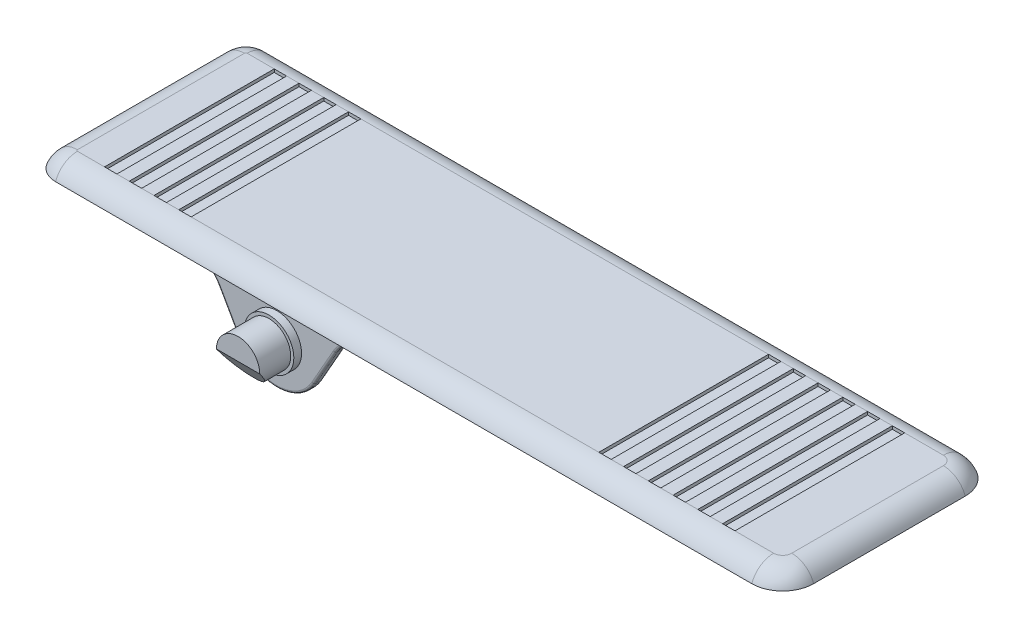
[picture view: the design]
ISO-10303-21;
HEADER;
FILE_DESCRIPTION(('STEP AP214'),'2;1');
FILE_NAME('part.step','',(''),(''),'','','');
FILE_SCHEMA(('AUTOMOTIVE_DESIGN { 1 0 10303 214 1 1 1 1 }'));
ENDSEC;
DATA;
#1=APPLICATION_CONTEXT('core data for automotive mechanical design processes');
#2=APPLICATION_PROTOCOL_DEFINITION('international standard','automotive_design',2000,#1);
#3=PRODUCT_CONTEXT('',#1,'mechanical');
#4=PRODUCT('Part','Part','',(#3));
#5=PRODUCT_RELATED_PRODUCT_CATEGORY('part','',(#4));
#6=PRODUCT_DEFINITION_FORMATION('','',#4);
#7=PRODUCT_DEFINITION_CONTEXT('part definition',#1,'design');
#8=PRODUCT_DEFINITION('design','',#6,#7);
#9=PRODUCT_DEFINITION_SHAPE('','',#8);
#10=(LENGTH_UNIT() NAMED_UNIT(*) SI_UNIT(.MILLI.,.METRE.));
#11=(NAMED_UNIT(*) PLANE_ANGLE_UNIT() SI_UNIT($,.RADIAN.));
#12=(NAMED_UNIT(*) SI_UNIT($,.STERADIAN.) SOLID_ANGLE_UNIT());
#13=UNCERTAINTY_MEASURE_WITH_UNIT(LENGTH_MEASURE(1.E-05),#10,'distance_accuracy_value','');
#14=(GEOMETRIC_REPRESENTATION_CONTEXT(3) GLOBAL_UNCERTAINTY_ASSIGNED_CONTEXT((#13)) GLOBAL_UNIT_ASSIGNED_CONTEXT((#10,
#11,#12)) REPRESENTATION_CONTEXT('',''));
#15=CARTESIAN_POINT('',(0.,0.,0.));
#16=DIRECTION('',(0.,0.,1.));
#17=DIRECTION('',(1.,0.,0.));
#18=AXIS2_PLACEMENT_3D('',#15,#16,#17);
#19=CARTESIAN_POINT('',(3.81,2.54,-3.81));
#20=DIRECTION('',(0.,1.,0.));
#21=DIRECTION('',(0.,0.,1.));
#22=AXIS2_PLACEMENT_3D('',#19,#20,#21);
#23=PLANE('',#22);
#24=DIRECTION('',(0.,0.,-1.));
#25=VECTOR('',#24,1.);
#26=CARTESIAN_POINT('',(22.479,2.54,-3.59210244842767));
#27=LINE('',#26,#25);
#28=CARTESIAN_POINT('',(22.479,2.54,-3.59210244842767));
#29=VERTEX_POINT('',#28);
#30=CARTESIAN_POINT('',(22.479,2.54,-31.4598975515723));
#31=VERTEX_POINT('',#30);
#32=EDGE_CURVE('E43',#29,#31,#27,.T.);
#33=ORIENTED_EDGE('',*,*,#32,.F.);
#34=DIRECTION('',(-1.,0.,0.));
#35=VECTOR('',#34,1.);
#36=CARTESIAN_POINT('',(118.11,2.54,-3.59210244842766));
#37=LINE('',#36,#35);
#38=CARTESIAN_POINT('',(89.408,2.54,-3.59210244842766));
#39=VERTEX_POINT('',#38);
#40=EDGE_CURVE('E1193',#29,#39,#37,.F.);
#41=ORIENTED_EDGE('',*,*,#40,.T.);
#42=DIRECTION('',(0.,0.,1.));
#43=VECTOR('',#42,1.);
#44=CARTESIAN_POINT('',(89.408,2.54,-31.4598975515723));
#45=LINE('',#44,#43);
#46=CARTESIAN_POINT('',(89.408,2.54,-31.4598975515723));
#47=VERTEX_POINT('',#46);
#48=EDGE_CURVE('E749',#47,#39,#45,.T.);
#49=ORIENTED_EDGE('',*,*,#48,.F.);
#50=DIRECTION('',(1.,0.,0.));
#51=VECTOR('',#50,1.);
#52=CARTESIAN_POINT('',(3.80999999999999,2.54,-31.4598975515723));
#53=LINE('',#52,#51);
#54=EDGE_CURVE('E690',#47,#31,#53,.F.);
#55=ORIENTED_EDGE('',*,*,#54,.T.);
#56=EDGE_LOOP('',(#33,#41,#49,#55));
#57=FACE_BOUND('',#56,.T.);
#58=ADVANCED_FACE('F28',(#57),#23,.T.);
#59=DIRECTION('',(0.,0.,1.));
#60=VECTOR('',#59,1.);
#61=CARTESIAN_POINT('',(20.447,2.54,-31.4598975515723));
#62=LINE('',#61,#60);
#63=CARTESIAN_POINT('',(20.447,2.54,-31.4598975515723));
#64=VERTEX_POINT('',#63);
#65=CARTESIAN_POINT('',(20.447,2.54,-3.59210244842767));
#66=VERTEX_POINT('',#65);
#67=EDGE_CURVE('E663',#64,#66,#62,.T.);
#68=ORIENTED_EDGE('',*,*,#67,.F.);
#69=CARTESIAN_POINT('',(18.415,2.54,-31.4598975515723));
#70=VERTEX_POINT('',#69);
#71=EDGE_CURVE('E51',#64,#70,#53,.F.);
#72=ORIENTED_EDGE('',*,*,#71,.T.);
#73=DIRECTION('',(0.,0.,-1.));
#74=VECTOR('',#73,1.);
#75=CARTESIAN_POINT('',(18.415,2.54,-3.59210244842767));
#76=LINE('',#75,#74);
#77=CARTESIAN_POINT('',(18.415,2.54,-3.59210244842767));
#78=VERTEX_POINT('',#77);
#79=EDGE_CURVE('E2952',#78,#70,#76,.T.);
#80=ORIENTED_EDGE('',*,*,#79,.F.);
#81=EDGE_CURVE('E682',#78,#66,#37,.F.);
#82=ORIENTED_EDGE('',*,*,#81,.T.);
#83=EDGE_LOOP('',(#68,#72,#80,#82));
#84=FACE_BOUND('',#83,.T.);
#85=ADVANCED_FACE('F680',(#84),#23,.T.);
#86=DIRECTION('',(0.,0.,1.));
#87=VECTOR('',#86,1.);
#88=CARTESIAN_POINT('',(16.383,2.54,-31.4598975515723));
#89=LINE('',#88,#87);
#90=CARTESIAN_POINT('',(16.383,2.54,-31.4598975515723));
#91=VERTEX_POINT('',#90);
#92=CARTESIAN_POINT('',(16.383,2.54,-3.59210244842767));
#93=VERTEX_POINT('',#92);
#94=EDGE_CURVE('E1310',#91,#93,#89,.T.);
#95=ORIENTED_EDGE('',*,*,#94,.F.);
#96=CARTESIAN_POINT('',(14.351,2.54,-31.4598975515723));
#97=VERTEX_POINT('',#96);
#98=EDGE_CURVE('E691',#91,#97,#53,.F.);
#99=ORIENTED_EDGE('',*,*,#98,.T.);
#100=DIRECTION('',(0.,0.,-1.));
#101=VECTOR('',#100,1.);
#102=CARTESIAN_POINT('',(14.351,2.54,-3.59210244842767));
#103=LINE('',#102,#101);
#104=CARTESIAN_POINT('',(14.351,2.54,-3.59210244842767));
#105=VERTEX_POINT('',#104);
#106=EDGE_CURVE('E1312',#105,#97,#103,.T.);
#107=ORIENTED_EDGE('',*,*,#106,.F.);
#108=EDGE_CURVE('E1302',#105,#93,#37,.F.);
#109=ORIENTED_EDGE('',*,*,#108,.T.);
#110=EDGE_LOOP('',(#95,#99,#107,#109));
#111=FACE_BOUND('',#110,.T.);
#112=ADVANCED_FACE('F1308',(#111),#23,.T.);
#113=DIRECTION('',(0.,0.,1.));
#114=VECTOR('',#113,1.);
#115=CARTESIAN_POINT('',(12.319,2.54,-31.4598975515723));
#116=LINE('',#115,#114);
#117=CARTESIAN_POINT('',(12.319,2.54,-31.4598975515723));
#118=VERTEX_POINT('',#117);
#119=CARTESIAN_POINT('',(12.319,2.54,-3.59210244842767));
#120=VERTEX_POINT('',#119);
#121=EDGE_CURVE('E1218',#118,#120,#116,.T.);
#122=ORIENTED_EDGE('',*,*,#121,.F.);
#123=CARTESIAN_POINT('',(10.287,2.54,-31.4598975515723));
#124=VERTEX_POINT('',#123);
#125=EDGE_CURVE('E696',#118,#124,#53,.F.);
#126=ORIENTED_EDGE('',*,*,#125,.T.);
#127=DIRECTION('',(0.,0.,-1.));
#128=VECTOR('',#127,1.);
#129=CARTESIAN_POINT('',(10.287,2.54,-3.59210244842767));
#130=LINE('',#129,#128);
#131=CARTESIAN_POINT('',(10.287,2.54,-3.59210244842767));
#132=VERTEX_POINT('',#131);
#133=EDGE_CURVE('E1215',#132,#124,#130,.T.);
#134=ORIENTED_EDGE('',*,*,#133,.F.);
#135=EDGE_CURVE('E1192',#132,#120,#37,.F.);
#136=ORIENTED_EDGE('',*,*,#135,.T.);
#137=EDGE_LOOP('',(#122,#126,#134,#136));
#138=FACE_BOUND('',#137,.T.);
#139=ADVANCED_FACE('F1213',(#138),#23,.T.);
#140=DIRECTION('',(0.,0.,-1.));
#141=VECTOR('',#140,1.);
#142=CARTESIAN_POINT('',(91.44,2.54,-3.59210244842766));
#143=LINE('',#142,#141);
#144=CARTESIAN_POINT('',(91.44,2.54,-3.59210244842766));
#145=VERTEX_POINT('',#144);
#146=CARTESIAN_POINT('',(91.44,2.54,-31.4598975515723));
#147=VERTEX_POINT('',#146);
#148=EDGE_CURVE('E736',#145,#147,#143,.T.);
#149=ORIENTED_EDGE('',*,*,#148,.F.);
#150=CARTESIAN_POINT('',(93.472,2.54,-3.59210244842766));
#151=VERTEX_POINT('',#150);
#152=EDGE_CURVE('E1300',#145,#151,#37,.F.);
#153=ORIENTED_EDGE('',*,*,#152,.T.);
#154=DIRECTION('',(0.,0.,1.));
#155=VECTOR('',#154,1.);
#156=CARTESIAN_POINT('',(93.472,2.54,-31.4598975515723));
#157=LINE('',#156,#155);
#158=CARTESIAN_POINT('',(93.472,2.54,-31.4598975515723));
#159=VERTEX_POINT('',#158);
#160=EDGE_CURVE('E739',#159,#151,#157,.T.);
#161=ORIENTED_EDGE('',*,*,#160,.F.);
#162=EDGE_CURVE('E694',#159,#147,#53,.F.);
#163=ORIENTED_EDGE('',*,*,#162,.T.);
#164=EDGE_LOOP('',(#149,#153,#161,#163));
#165=FACE_BOUND('',#164,.T.);
#166=ADVANCED_FACE('F735',(#165),#23,.T.);
#167=DIRECTION('',(0.,0.,-1.));
#168=VECTOR('',#167,1.);
#169=CARTESIAN_POINT('',(95.504,2.54,-3.59210244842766));
#170=LINE('',#169,#168);
#171=CARTESIAN_POINT('',(95.504,2.54,-3.59210244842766));
#172=VERTEX_POINT('',#171);
#173=CARTESIAN_POINT('',(95.504,2.54,-31.4598975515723));
#174=VERTEX_POINT('',#173);
#175=EDGE_CURVE('E773',#172,#174,#170,.T.);
#176=ORIENTED_EDGE('',*,*,#175,.F.);
#177=CARTESIAN_POINT('',(97.536,2.54,-3.59210244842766));
#178=VERTEX_POINT('',#177);
#179=EDGE_CURVE('E1298',#172,#178,#37,.F.);
#180=ORIENTED_EDGE('',*,*,#179,.T.);
#181=DIRECTION('',(0.,0.,1.));
#182=VECTOR('',#181,1.);
#183=CARTESIAN_POINT('',(97.536,2.54,-31.4598975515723));
#184=LINE('',#183,#182);
#185=CARTESIAN_POINT('',(97.536,2.54,-31.4598975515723));
#186=VERTEX_POINT('',#185);
#187=EDGE_CURVE('E811',#186,#178,#184,.T.);
#188=ORIENTED_EDGE('',*,*,#187,.F.);
#189=EDGE_CURVE('E720',#186,#174,#53,.F.);
#190=ORIENTED_EDGE('',*,*,#189,.T.);
#191=EDGE_LOOP('',(#176,#180,#188,#190));
#192=FACE_BOUND('',#191,.T.);
#193=ADVANCED_FACE('F2616',(#192),#23,.T.);
#194=DIRECTION('',(0.,0.,-1.));
#195=VECTOR('',#194,1.);
#196=CARTESIAN_POINT('',(99.568,2.54,-3.59210244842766));
#197=LINE('',#196,#195);
#198=CARTESIAN_POINT('',(99.568,2.54,-3.59210244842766));
#199=VERTEX_POINT('',#198);
#200=CARTESIAN_POINT('',(99.568,2.54,-31.4598975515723));
#201=VERTEX_POINT('',#200);
#202=EDGE_CURVE('E799',#199,#201,#197,.T.);
#203=ORIENTED_EDGE('',*,*,#202,.F.);
#204=CARTESIAN_POINT('',(101.6,2.54,-3.59210244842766));
#205=VERTEX_POINT('',#204);
#206=EDGE_CURVE('E1296',#199,#205,#37,.F.);
#207=ORIENTED_EDGE('',*,*,#206,.T.);
#208=DIRECTION('',(0.,0.,1.));
#209=VECTOR('',#208,1.);
#210=CARTESIAN_POINT('',(101.6,2.54,-31.4598975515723));
#211=LINE('',#210,#209);
#212=CARTESIAN_POINT('',(101.6,2.54,-31.4598975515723));
#213=VERTEX_POINT('',#212);
#214=EDGE_CURVE('E842',#213,#205,#211,.T.);
#215=ORIENTED_EDGE('',*,*,#214,.F.);
#216=EDGE_CURVE('E714',#213,#201,#53,.F.);
#217=ORIENTED_EDGE('',*,*,#216,.T.);
#218=EDGE_LOOP('',(#203,#207,#215,#217));
#219=FACE_BOUND('',#218,.T.);
#220=ADVANCED_FACE('F1426',(#219),#23,.T.);
#221=DIRECTION('',(0.,0.,-1.));
#222=VECTOR('',#221,1.);
#223=CARTESIAN_POINT('',(103.632,2.54,-3.59210244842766));
#224=LINE('',#223,#222);
#225=CARTESIAN_POINT('',(103.632,2.54,-3.59210244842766));
#226=VERTEX_POINT('',#225);
#227=CARTESIAN_POINT('',(103.632,2.54,-31.4598975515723));
#228=VERTEX_POINT('',#227);
#229=EDGE_CURVE('E830',#226,#228,#224,.T.);
#230=ORIENTED_EDGE('',*,*,#229,.F.);
#231=CARTESIAN_POINT('',(105.664,2.54,-3.59210244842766));
#232=VERTEX_POINT('',#231);
#233=EDGE_CURVE('E1294',#226,#232,#37,.F.);
#234=ORIENTED_EDGE('',*,*,#233,.T.);
#235=DIRECTION('',(0.,0.,1.));
#236=VECTOR('',#235,1.);
#237=CARTESIAN_POINT('',(105.664,2.54,-31.4598975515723));
#238=LINE('',#237,#236);
#239=CARTESIAN_POINT('',(105.664,2.54,-31.4598975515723));
#240=VERTEX_POINT('',#239);
#241=EDGE_CURVE('E873',#240,#232,#238,.T.);
#242=ORIENTED_EDGE('',*,*,#241,.F.);
#243=EDGE_CURVE('E708',#240,#228,#53,.F.);
#244=ORIENTED_EDGE('',*,*,#243,.T.);
#245=EDGE_LOOP('',(#230,#234,#242,#244));
#246=FACE_BOUND('',#245,.T.);
#247=ADVANCED_FACE('F1421',(#246),#23,.T.);
#248=DIRECTION('',(0.,0.,-1.));
#249=VECTOR('',#248,1.);
#250=CARTESIAN_POINT('',(107.696,2.54,-3.59210244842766));
#251=LINE('',#250,#249);
#252=CARTESIAN_POINT('',(107.696,2.54,-3.59210244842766));
#253=VERTEX_POINT('',#252);
#254=CARTESIAN_POINT('',(107.696,2.54,-31.4598975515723));
#255=VERTEX_POINT('',#254);
#256=EDGE_CURVE('E861',#253,#255,#251,.T.);
#257=ORIENTED_EDGE('',*,*,#256,.F.);
#258=CARTESIAN_POINT('',(109.728,2.54,-3.59210244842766));
#259=VERTEX_POINT('',#258);
#260=EDGE_CURVE('E1293',#253,#259,#37,.F.);
#261=ORIENTED_EDGE('',*,*,#260,.T.);
#262=DIRECTION('',(0.,0.,1.));
#263=VECTOR('',#262,1.);
#264=CARTESIAN_POINT('',(109.728,2.54,-31.4598975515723));
#265=LINE('',#264,#263);
#266=CARTESIAN_POINT('',(109.728,2.54,-31.4598975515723));
#267=VERTEX_POINT('',#266);
#268=EDGE_CURVE('E904',#267,#259,#265,.T.);
#269=ORIENTED_EDGE('',*,*,#268,.F.);
#270=EDGE_CURVE('E701',#267,#255,#53,.F.);
#271=ORIENTED_EDGE('',*,*,#270,.T.);
#272=EDGE_LOOP('',(#257,#261,#269,#271));
#273=FACE_BOUND('',#272,.T.);
#274=ADVANCED_FACE('F1411',(#273),#23,.T.);
#275=DIRECTION('',(0.,0.,-1.));
#276=VECTOR('',#275,1.);
#277=CARTESIAN_POINT('',(111.76,2.54,-3.59210244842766));
#278=LINE('',#277,#276);
#279=CARTESIAN_POINT('',(111.76,2.54,-3.59210244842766));
#280=VERTEX_POINT('',#279);
#281=CARTESIAN_POINT('',(111.76,2.54,-31.4598975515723));
#282=VERTEX_POINT('',#281);
#283=EDGE_CURVE('E892',#280,#282,#278,.T.);
#284=ORIENTED_EDGE('',*,*,#283,.F.);
#285=CARTESIAN_POINT('',(118.11,2.54,-3.59210244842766));
#286=VERTEX_POINT('',#285);
#287=EDGE_CURVE('E1187',#280,#286,#37,.F.);
#288=ORIENTED_EDGE('',*,*,#287,.T.);
#289=CARTESIAN_POINT('',(118.11,2.54,-5.08));
#290=DIRECTION('',(0.,1.,0.));
#291=DIRECTION('',(0.,0.,1.));
#292=AXIS2_PLACEMENT_3D('',#289,#290,#291);
#293=CIRCLE('',#292,1.48789755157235);
#294=CARTESIAN_POINT('',(119.597897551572,2.54,-5.08));
#295=VERTEX_POINT('',#294);
#296=EDGE_CURVE('E1191',#286,#295,#293,.T.);
#297=ORIENTED_EDGE('',*,*,#296,.T.);
#298=DIRECTION('',(0.,0.,-1.));
#299=VECTOR('',#298,1.);
#300=CARTESIAN_POINT('',(119.597897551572,2.54,-29.972));
#301=LINE('',#300,#299);
#302=CARTESIAN_POINT('',(119.597897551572,2.54,-29.972));
#303=VERTEX_POINT('',#302);
#304=EDGE_CURVE('E1197',#295,#303,#301,.T.);
#305=ORIENTED_EDGE('',*,*,#304,.T.);
#306=CARTESIAN_POINT('',(118.11,2.54,-29.972));
#307=DIRECTION('',(0.,1.,0.));
#308=DIRECTION('',(0.,0.,1.));
#309=AXIS2_PLACEMENT_3D('',#306,#307,#308);
#310=CIRCLE('',#309,1.48789755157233);
#311=CARTESIAN_POINT('',(118.11,2.54,-31.4598975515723));
#312=VERTEX_POINT('',#311);
#313=EDGE_CURVE('E1201',#303,#312,#310,.T.);
#314=ORIENTED_EDGE('',*,*,#313,.T.);
#315=EDGE_CURVE('E693',#312,#282,#53,.F.);
#316=ORIENTED_EDGE('',*,*,#315,.T.);
#317=EDGE_LOOP('',(#284,#288,#297,#305,#314,#316));
#318=FACE_BOUND('',#317,.T.);
#319=ADVANCED_FACE('F1291',(#318),#23,.T.);
#320=CARTESIAN_POINT('',(3.81,0.,-3.81));
#321=DIRECTION('',(0.,1.,0.));
#322=DIRECTION('',(0.,0.,1.));
#323=AXIS2_PLACEMENT_3D('',#320,#321,#322);
#324=PLANE('',#323);
#325=CARTESIAN_POINT('',(14.605,0.,-17.526));
#326=DIRECTION('',(0.,1.,0.));
#327=DIRECTION('',(0.,0.,1.));
#328=AXIS2_PLACEMENT_3D('',#325,#326,#327);
#329=CIRCLE('',#328,9.652);
#330=CARTESIAN_POINT('',(14.605,0.,-7.87400000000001));
#331=VERTEX_POINT('',#330);
#332=EDGE_CURVE('E1982',#331,#331,#329,.T.);
#333=ORIENTED_EDGE('',*,*,#332,.T.);
#334=EDGE_LOOP('',(#333));
#335=FACE_BOUND('',#334,.T.);
#336=CARTESIAN_POINT('',(5.842,0.,-4.064));
#337=DIRECTION('',(0.,1.,0.));
#338=DIRECTION('',(0.,0.,1.));
#339=AXIS2_PLACEMENT_3D('',#336,#337,#338);
#340=CIRCLE('',#339,1.143);
#341=CARTESIAN_POINT('',(4.699,0.,-4.064));
#342=VERTEX_POINT('',#341);
#343=CARTESIAN_POINT('',(5.842,0.,-2.921));
#344=VERTEX_POINT('',#343);
#345=EDGE_CURVE('E1988',#342,#344,#340,.T.);
#346=ORIENTED_EDGE('',*,*,#345,.T.);
#347=DIRECTION('',(1.,0.,0.));
#348=VECTOR('',#347,1.);
#349=CARTESIAN_POINT('',(110.236,0.,-2.921));
#350=LINE('',#349,#348);
#351=CARTESIAN_POINT('',(110.236,0.,-2.921));
#352=VERTEX_POINT('',#351);
#353=EDGE_CURVE('E1985',#344,#352,#350,.T.);
#354=ORIENTED_EDGE('',*,*,#353,.T.);
#355=CARTESIAN_POINT('',(110.236,0.,-4.064));
#356=DIRECTION('',(0.,1.,0.));
#357=DIRECTION('',(0.,0.,1.));
#358=AXIS2_PLACEMENT_3D('',#355,#356,#357);
#359=CIRCLE('',#358,1.143);
#360=CARTESIAN_POINT('',(111.379,0.,-4.064));
#361=VERTEX_POINT('',#360);
#362=EDGE_CURVE('E1990',#352,#361,#359,.T.);
#363=ORIENTED_EDGE('',*,*,#362,.T.);
#364=CARTESIAN_POINT('',(110.236,0.,-4.064));
#365=DIRECTION('',(0.,1.,0.));
#366=DIRECTION('',(0.,0.,1.));
#367=AXIS2_PLACEMENT_3D('',#364,#365,#366);
#368=CIRCLE('',#367,1.143);
#369=CARTESIAN_POINT('',(110.236,0.,-5.207));
#370=VERTEX_POINT('',#369);
#371=EDGE_CURVE('E1994',#361,#370,#368,.T.);
#372=ORIENTED_EDGE('',*,*,#371,.T.);
#373=DIRECTION('',(1.,0.,0.));
#374=VECTOR('',#373,1.);
#375=CARTESIAN_POINT('',(3.81,0.,-5.207));
#376=LINE('',#375,#374);
#377=CARTESIAN_POINT('',(5.842,0.,-5.207));
#378=VERTEX_POINT('',#377);
#379=EDGE_CURVE('E1996',#370,#378,#376,.F.);
#380=ORIENTED_EDGE('',*,*,#379,.T.);
#381=CARTESIAN_POINT('',(5.842,0.,-4.064));
#382=DIRECTION('',(0.,1.,0.));
#383=DIRECTION('',(0.,0.,1.));
#384=AXIS2_PLACEMENT_3D('',#381,#382,#383);
#385=CIRCLE('',#384,1.143);
#386=EDGE_CURVE('E1992',#378,#342,#385,.T.);
#387=ORIENTED_EDGE('',*,*,#386,.T.);
#388=EDGE_LOOP('',(#346,#354,#363,#372,#380,#387));
#389=FACE_BOUND('',#388,.T.);
#390=CARTESIAN_POINT('',(5.842,0.,-30.988));
#391=DIRECTION('',(0.,1.,0.));
#392=DIRECTION('',(0.,0.,1.));
#393=AXIS2_PLACEMENT_3D('',#390,#391,#392);
#394=CIRCLE('',#393,1.143);
#395=CARTESIAN_POINT('',(4.699,0.,-30.988));
#396=VERTEX_POINT('',#395);
#397=CARTESIAN_POINT('',(5.842,0.,-29.845));
#398=VERTEX_POINT('',#397);
#399=EDGE_CURVE('E2001',#396,#398,#394,.T.);
#400=ORIENTED_EDGE('',*,*,#399,.T.);
#401=DIRECTION('',(1.,0.,0.));
#402=VECTOR('',#401,1.);
#403=CARTESIAN_POINT('',(3.81,0.,-29.845));
#404=LINE('',#403,#402);
#405=CARTESIAN_POINT('',(110.236,0.,-29.845));
#406=VERTEX_POINT('',#405);
#407=EDGE_CURVE('E1998',#398,#406,#404,.T.);
#408=ORIENTED_EDGE('',*,*,#407,.T.);
#409=CARTESIAN_POINT('',(110.236,0.,-30.988));
#410=DIRECTION('',(0.,1.,0.));
#411=DIRECTION('',(0.,0.,1.));
#412=AXIS2_PLACEMENT_3D('',#409,#410,#411);
#413=CIRCLE('',#412,1.143);
#414=CARTESIAN_POINT('',(111.379,0.,-30.988));
#415=VERTEX_POINT('',#414);
#416=EDGE_CURVE('E2003',#406,#415,#413,.T.);
#417=ORIENTED_EDGE('',*,*,#416,.T.);
#418=CARTESIAN_POINT('',(110.236,0.,-30.988));
#419=DIRECTION('',(0.,1.,0.));
#420=DIRECTION('',(0.,0.,1.));
#421=AXIS2_PLACEMENT_3D('',#418,#419,#420);
#422=CIRCLE('',#421,1.143);
#423=CARTESIAN_POINT('',(110.236,0.,-32.131));
#424=VERTEX_POINT('',#423);
#425=EDGE_CURVE('E2007',#415,#424,#422,.T.);
#426=ORIENTED_EDGE('',*,*,#425,.T.);
#427=DIRECTION('',(1.,0.,0.));
#428=VECTOR('',#427,1.);
#429=CARTESIAN_POINT('',(5.842,0.,-32.131));
#430=LINE('',#429,#428);
#431=CARTESIAN_POINT('',(5.842,0.,-32.131));
#432=VERTEX_POINT('',#431);
#433=EDGE_CURVE('E2009',#424,#432,#430,.F.);
#434=ORIENTED_EDGE('',*,*,#433,.T.);
#435=CARTESIAN_POINT('',(5.842,0.,-30.988));
#436=DIRECTION('',(0.,1.,0.));
#437=DIRECTION('',(0.,0.,1.));
#438=AXIS2_PLACEMENT_3D('',#435,#436,#437);
#439=CIRCLE('',#438,1.143);
#440=EDGE_CURVE('E2005',#432,#396,#439,.T.);
#441=ORIENTED_EDGE('',*,*,#440,.T.);
#442=EDGE_LOOP('',(#400,#408,#417,#426,#434,#441));
#443=FACE_BOUND('',#442,.T.);
#444=DIRECTION('',(0.,0.,1.));
#445=VECTOR('',#444,1.);
#446=CARTESIAN_POINT('',(119.634,0.,-30.988));
#447=LINE('',#446,#445);
#448=CARTESIAN_POINT('',(119.634,0.,-30.988));
#449=VERTEX_POINT('',#448);
#450=CARTESIAN_POINT('',(119.634,0.,-4.064));
#451=VERTEX_POINT('',#450);
#452=EDGE_CURVE('E1067',#449,#451,#447,.T.);
#453=ORIENTED_EDGE('',*,*,#452,.F.);
#454=CARTESIAN_POINT('',(118.872,0.,-30.988));
#455=DIRECTION('',(0.,1.,0.));
#456=DIRECTION('',(0.,0.,1.));
#457=AXIS2_PLACEMENT_3D('',#454,#455,#456);
#458=CIRCLE('',#457,0.761999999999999);
#459=CARTESIAN_POINT('',(118.11,0.,-30.988));
#460=VERTEX_POINT('',#459);
#461=EDGE_CURVE('E1075',#449,#460,#458,.T.);
#462=ORIENTED_EDGE('',*,*,#461,.T.);
#463=DIRECTION('',(0.,0.,-1.));
#464=VECTOR('',#463,1.);
#465=CARTESIAN_POINT('',(118.11,0.,-4.064));
#466=LINE('',#465,#464);
#467=CARTESIAN_POINT('',(118.11,0.,-4.064));
#468=VERTEX_POINT('',#467);
#469=EDGE_CURVE('E1076',#468,#460,#466,.T.);
#470=ORIENTED_EDGE('',*,*,#469,.F.);
#471=CARTESIAN_POINT('',(118.872,0.,-4.064));
#472=DIRECTION('',(0.,1.,0.));
#473=DIRECTION('',(0.,0.,1.));
#474=AXIS2_PLACEMENT_3D('',#471,#472,#473);
#475=CIRCLE('',#474,0.761999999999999);
#476=EDGE_CURVE('E1072',#468,#451,#475,.T.);
#477=ORIENTED_EDGE('',*,*,#476,.T.);
#478=EDGE_LOOP('',(#453,#462,#470,#477));
#479=FACE_BOUND('',#478,.T.);
#480=CARTESIAN_POINT('',(3.81,0.,-3.81));
#481=DIRECTION('',(0.,1.,0.));
#482=DIRECTION('',(0.,0.,1.));
#483=AXIS2_PLACEMENT_3D('',#480,#481,#482);
#484=CIRCLE('',#483,3.81);
#485=CARTESIAN_POINT('',(0.,0.,-3.81000000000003));
#486=VERTEX_POINT('',#485);
#487=CARTESIAN_POINT('',(3.81000000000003,0.,0.));
#488=VERTEX_POINT('',#487);
#489=EDGE_CURVE('E1166',#486,#488,#484,.T.);
#490=ORIENTED_EDGE('',*,*,#489,.F.);
#491=DIRECTION('',(0.,0.,-1.));
#492=VECTOR('',#491,1.);
#493=CARTESIAN_POINT('',(0.,0.,-3.81000000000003));
#494=LINE('',#493,#492);
#495=CARTESIAN_POINT('',(0.,0.,-31.242));
#496=VERTEX_POINT('',#495);
#497=EDGE_CURVE('E1185',#486,#496,#494,.T.);
#498=ORIENTED_EDGE('',*,*,#497,.T.);
#499=CARTESIAN_POINT('',(3.81,0.,-31.242));
#500=DIRECTION('',(0.,1.,0.));
#501=DIRECTION('',(0.,0.,1.));
#502=AXIS2_PLACEMENT_3D('',#499,#500,#501);
#503=CIRCLE('',#502,3.81);
#504=CARTESIAN_POINT('',(3.81,0.,-35.052));
#505=VERTEX_POINT('',#504);
#506=EDGE_CURVE('E1182',#505,#496,#503,.T.);
#507=ORIENTED_EDGE('',*,*,#506,.F.);
#508=DIRECTION('',(-1.,0.,0.));
#509=VECTOR('',#508,1.);
#510=CARTESIAN_POINT('',(118.11,0.,-35.052));
#511=LINE('',#510,#509);
#512=CARTESIAN_POINT('',(118.11,0.,-35.052));
#513=VERTEX_POINT('',#512);
#514=EDGE_CURVE('E1179',#513,#505,#511,.T.);
#515=ORIENTED_EDGE('',*,*,#514,.F.);
#516=CARTESIAN_POINT('',(118.11,0.,-29.972));
#517=DIRECTION('',(0.,1.,0.));
#518=DIRECTION('',(0.,0.,1.));
#519=AXIS2_PLACEMENT_3D('',#516,#517,#518);
#520=CIRCLE('',#519,5.07999999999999);
#521=CARTESIAN_POINT('',(123.19,0.,-29.972));
#522=VERTEX_POINT('',#521);
#523=EDGE_CURVE('E1176',#522,#513,#520,.T.);
#524=ORIENTED_EDGE('',*,*,#523,.F.);
#525=DIRECTION('',(0.,0.,1.));
#526=VECTOR('',#525,1.);
#527=CARTESIAN_POINT('',(123.19,0.,-29.972));
#528=LINE('',#527,#526);
#529=CARTESIAN_POINT('',(123.19,0.,-5.08));
#530=VERTEX_POINT('',#529);
#531=EDGE_CURVE('E1174',#522,#530,#528,.T.);
#532=ORIENTED_EDGE('',*,*,#531,.T.);
#533=CARTESIAN_POINT('',(118.11,0.,-5.08));
#534=DIRECTION('',(0.,-1.,0.));
#535=DIRECTION('',(0.,0.,-1.));
#536=AXIS2_PLACEMENT_3D('',#533,#534,#535);
#537=CIRCLE('',#536,5.08000000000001);
#538=CARTESIAN_POINT('',(118.11,0.,0.));
#539=VERTEX_POINT('',#538);
#540=EDGE_CURVE('E1172',#530,#539,#537,.T.);
#541=ORIENTED_EDGE('',*,*,#540,.T.);
#542=DIRECTION('',(1.,0.,0.));
#543=VECTOR('',#542,1.);
#544=CARTESIAN_POINT('',(3.81000000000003,0.,0.));
#545=LINE('',#544,#543);
#546=EDGE_CURVE('E1169',#488,#539,#545,.T.);
#547=ORIENTED_EDGE('',*,*,#546,.F.);
#548=EDGE_LOOP('',(#490,#498,#507,#515,#524,#532,#541,#547));
#549=FACE_BOUND('',#548,.T.);
#550=ADVANCED_FACE('F1281',(#335,#389,#443,#479,#549),#324,.F.);
#551=CARTESIAN_POINT('',(36.83,-7.5184,3.048));
#552=DIRECTION('',(0.,0.,-1.));
#553=DIRECTION('',(-1.,0.,0.));
#554=AXIS2_PLACEMENT_3D('',#551,#552,#553);
#555=CYLINDRICAL_SURFACE('',#554,3.55600000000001);
#556=CARTESIAN_POINT('',(36.83,-7.5184,-2.032));
#557=DIRECTION('',(0.,0.,1.));
#558=DIRECTION('',(1.,0.,0.));
#559=AXIS2_PLACEMENT_3D('',#556,#557,#558);
#560=CIRCLE('',#559,3.55600000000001);
#561=CARTESIAN_POINT('',(40.386,-7.5184,-2.032));
#562=VERTEX_POINT('',#561);
#563=EDGE_CURVE('E1127',#562,#562,#560,.F.);
#564=ORIENTED_EDGE('',*,*,#563,.F.);
#565=EDGE_LOOP('',(#564));
#566=FACE_BOUND('',#565,.T.);
#567=CARTESIAN_POINT('',(36.83,-7.5184,3.048));
#568=DIRECTION('',(0.,0.,1.));
#569=DIRECTION('',(1.,0.,0.));
#570=AXIS2_PLACEMENT_3D('',#567,#568,#569);
#571=CIRCLE('',#570,3.55600000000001);
#572=CARTESIAN_POINT('',(40.386,-7.5184,3.048));
#573=VERTEX_POINT('',#572);
#574=CARTESIAN_POINT('',(33.274,-7.5184,3.048));
#575=VERTEX_POINT('',#574);
#576=EDGE_CURVE('E1124',#573,#575,#571,.T.);
#577=ORIENTED_EDGE('',*,*,#576,.F.);
#578=CARTESIAN_POINT('',(36.83,-7.5184,3.048));
#579=DIRECTION('',(0.,-0.581238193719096,0.813733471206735));
#580=DIRECTION('',(0.,-0.813733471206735,-0.581238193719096));
#581=AXIS2_PLACEMENT_3D('',#578,#579,#580);
#582=ELLIPSE('',#581,4.36998123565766,3.55600000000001);
#583=EDGE_CURVE('E1120',#575,#573,#582,.T.);
#584=ORIENTED_EDGE('',*,*,#583,.F.);
#585=EDGE_LOOP('',(#577,#584));
#586=FACE_BOUND('',#585,.T.);
#587=ADVANCED_FACE('F1417',(#566,#586),#555,.T.);
#588=CARTESIAN_POINT('',(36.83,-7.5184,3.048));
#589=DIRECTION('',(0.,0.,1.));
#590=DIRECTION('',(1.,0.,0.));
#591=AXIS2_PLACEMENT_3D('',#588,#589,#590);
#592=PLANE('',#591);
#593=ORIENTED_EDGE('',*,*,#576,.T.);
#594=DIRECTION('',(1.,0.,0.));
#595=VECTOR('',#594,1.);
#596=CARTESIAN_POINT('',(36.83,-7.5184,3.048));
#597=LINE('',#596,#595);
#598=EDGE_CURVE('E2164',#575,#573,#597,.T.);
#599=ORIENTED_EDGE('',*,*,#598,.T.);
#600=EDGE_LOOP('',(#593,#599));
#601=FACE_BOUND('',#600,.T.);
#602=ADVANCED_FACE('F1805',(#601),#592,.T.);
#603=CARTESIAN_POINT('',(36.83,-7.5184,-2.032));
#604=DIRECTION('',(0.,0.,1.));
#605=DIRECTION('',(1.,0.,0.));
#606=AXIS2_PLACEMENT_3D('',#603,#604,#605);
#607=PLANE('',#606);
#608=CARTESIAN_POINT('',(36.83,-7.5184,-2.032));
#609=DIRECTION('',(0.,0.,1.));
#610=DIRECTION('',(1.,0.,0.));
#611=AXIS2_PLACEMENT_3D('',#608,#609,#610);
#612=CIRCLE('',#611,4.064);
#613=CARTESIAN_POINT('',(40.894,-7.5184,-2.032));
#614=VERTEX_POINT('',#613);
#615=EDGE_CURVE('E1128',#614,#614,#612,.T.);
#616=ORIENTED_EDGE('',*,*,#615,.T.);
#617=EDGE_LOOP('',(#616));
#618=FACE_BOUND('',#617,.T.);
#619=ORIENTED_EDGE('',*,*,#563,.T.);
#620=EDGE_LOOP('',(#619));
#621=FACE_BOUND('',#620,.T.);
#622=ADVANCED_FACE('F1407',(#618,#621),#607,.T.);
#623=CARTESIAN_POINT('',(36.83,-7.5184,-3.302));
#624=DIRECTION('',(0.,0.,-1.));
#625=DIRECTION('',(-1.,0.,0.));
#626=AXIS2_PLACEMENT_3D('',#623,#624,#625);
#627=PLANE('',#626);
#628=DIRECTION('',(0.,-1.,0.));
#629=VECTOR('',#628,1.);
#630=CARTESIAN_POINT('',(110.236,-7.5184,-3.302));
#631=LINE('',#630,#629);
#632=CARTESIAN_POINT('',(110.236,-1.143,-3.302));
#633=VERTEX_POINT('',#632);
#634=CARTESIAN_POINT('',(110.236,-0.381,-3.302));
#635=VERTEX_POINT('',#634);
#636=EDGE_CURVE('E2175',#633,#635,#631,.F.);
#637=ORIENTED_EDGE('',*,*,#636,.T.);
#638=DIRECTION('',(1.,0.,0.));
#639=VECTOR('',#638,1.);
#640=CARTESIAN_POINT('',(5.842,-0.381,-3.302));
#641=LINE('',#640,#639);
#642=CARTESIAN_POINT('',(5.842,-0.381,-3.302));
#643=VERTEX_POINT('',#642);
#644=EDGE_CURVE('E2075',#635,#643,#641,.F.);
#645=ORIENTED_EDGE('',*,*,#644,.T.);
#646=DIRECTION('',(0.,-1.,0.));
#647=VECTOR('',#646,1.);
#648=CARTESIAN_POINT('',(5.842,-1.524,-3.302));
#649=LINE('',#648,#647);
#650=CARTESIAN_POINT('',(5.842,-1.143,-3.302));
#651=VERTEX_POINT('',#650);
#652=EDGE_CURVE('E2172',#643,#651,#649,.T.);
#653=ORIENTED_EDGE('',*,*,#652,.T.);
#654=DIRECTION('',(1.,0.,0.));
#655=VECTOR('',#654,1.);
#656=CARTESIAN_POINT('',(21.7012517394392,-1.143,-3.302));
#657=LINE('',#656,#655);
#658=CARTESIAN_POINT('',(21.7012517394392,-1.143,-3.302));
#659=VERTEX_POINT('',#658);
#660=EDGE_CURVE('E2078',#651,#659,#657,.T.);
#661=ORIENTED_EDGE('',*,*,#660,.T.);
#662=CARTESIAN_POINT('',(21.7012517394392,-7.874,-3.302));
#663=DIRECTION('',(0.,0.,-1.));
#664=DIRECTION('',(-1.,0.,0.));
#665=AXIS2_PLACEMENT_3D('',#662,#663,#664);
#666=CIRCLE('',#665,6.731);
#667=CARTESIAN_POINT('',(27.5561355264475,-4.55335294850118,-3.302));
#668=VERTEX_POINT('',#667);
#669=EDGE_CURVE('E2080',#659,#668,#666,.T.);
#670=ORIENTED_EDGE('',*,*,#669,.T.);
#671=DIRECTION('',(-0.493336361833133,0.869838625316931,0.));
#672=VECTOR('',#671,1.);
#673=CARTESIAN_POINT('',(31.085585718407,-10.776393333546,-3.302));
#674=LINE('',#673,#672);
#675=CARTESIAN_POINT('',(31.085585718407,-10.776393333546,-3.302));
#676=VERTEX_POINT('',#675);
#677=EDGE_CURVE('E2082',#668,#676,#674,.F.);
#678=ORIENTED_EDGE('',*,*,#677,.T.);
#679=CARTESIAN_POINT('',(36.83,-7.5184,-3.302));
#680=DIRECTION('',(0.,0.,-1.));
#681=DIRECTION('',(-1.,0.,0.));
#682=AXIS2_PLACEMENT_3D('',#679,#680,#681);
#683=CIRCLE('',#682,6.60399999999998);
#684=CARTESIAN_POINT('',(42.574414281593,-10.776393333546,-3.302));
#685=VERTEX_POINT('',#684);
#686=EDGE_CURVE('E2084',#676,#685,#683,.F.);
#687=ORIENTED_EDGE('',*,*,#686,.T.);
#688=DIRECTION('',(0.493336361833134,0.86983862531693,0.));
#689=VECTOR('',#688,1.);
#690=CARTESIAN_POINT('',(46.1038644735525,-4.55335294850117,-3.302));
#691=LINE('',#690,#689);
#692=CARTESIAN_POINT('',(46.1038644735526,-4.55335294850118,-3.302));
#693=VERTEX_POINT('',#692);
#694=EDGE_CURVE('E2086',#685,#693,#691,.T.);
#695=ORIENTED_EDGE('',*,*,#694,.T.);
#696=CARTESIAN_POINT('',(51.9587482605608,-7.874,-3.302));
#697=DIRECTION('',(0.,0.,-1.));
#698=DIRECTION('',(-1.,0.,0.));
#699=AXIS2_PLACEMENT_3D('',#696,#697,#698);
#700=CIRCLE('',#699,6.731);
#701=CARTESIAN_POINT('',(51.9587482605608,-1.143,-3.302));
#702=VERTEX_POINT('',#701);
#703=EDGE_CURVE('E2090',#693,#702,#700,.T.);
#704=ORIENTED_EDGE('',*,*,#703,.T.);
#705=DIRECTION('',(1.,0.,0.));
#706=VECTOR('',#705,1.);
#707=CARTESIAN_POINT('',(110.236,-1.143,-3.302));
#708=LINE('',#707,#706);
#709=EDGE_CURVE('E2088',#702,#633,#708,.T.);
#710=ORIENTED_EDGE('',*,*,#709,.T.);
#711=EDGE_LOOP('',(#637,#645,#653,#661,#670,#678,#687,#695,#704,#710));
#712=FACE_BOUND('',#711,.T.);
#713=CARTESIAN_POINT('',(36.83,-7.5184,-3.302));
#714=DIRECTION('',(0.,0.,-1.));
#715=DIRECTION('',(-1.,0.,0.));
#716=AXIS2_PLACEMENT_3D('',#713,#714,#715);
#717=CIRCLE('',#716,4.064);
#718=CARTESIAN_POINT('',(32.766,-7.5184,-3.302));
#719=VERTEX_POINT('',#718);
#720=EDGE_CURVE('E2167',#719,#719,#717,.F.);
#721=ORIENTED_EDGE('',*,*,#720,.F.);
#722=EDGE_LOOP('',(#721));
#723=FACE_BOUND('',#722,.T.);
#724=ADVANCED_FACE('F1399',(#712,#723),#627,.F.);
#725=DIRECTION('',(0.,0.,1.));
#726=VECTOR('',#725,1.);
#727=CARTESIAN_POINT('',(8.255,2.54,-31.4598975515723));
#728=LINE('',#727,#726);
#729=CARTESIAN_POINT('',(8.255,2.54,-31.4598975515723));
#730=VERTEX_POINT('',#729);
#731=CARTESIAN_POINT('',(8.255,2.54,-3.59210244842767));
#732=VERTEX_POINT('',#731);
#733=EDGE_CURVE('E1239',#730,#732,#728,.T.);
#734=ORIENTED_EDGE('',*,*,#733,.F.);
#735=CARTESIAN_POINT('',(3.81,2.54,-31.4598975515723));
#736=VERTEX_POINT('',#735);
#737=EDGE_CURVE('E695',#730,#736,#53,.F.);
#738=ORIENTED_EDGE('',*,*,#737,.T.);
#739=CARTESIAN_POINT('',(3.81,2.54,-31.242));
#740=DIRECTION('',(0.,1.,0.));
#741=DIRECTION('',(0.,0.,1.));
#742=AXIS2_PLACEMENT_3D('',#739,#740,#741);
#743=CIRCLE('',#742,0.217897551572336);
#744=CARTESIAN_POINT('',(3.59210244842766,2.54,-31.242));
#745=VERTEX_POINT('',#744);
#746=EDGE_CURVE('E1202',#736,#745,#743,.T.);
#747=ORIENTED_EDGE('',*,*,#746,.T.);
#748=DIRECTION('',(0.,0.,1.));
#749=VECTOR('',#748,1.);
#750=CARTESIAN_POINT('',(3.59210244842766,2.54,-3.81000000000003));
#751=LINE('',#750,#749);
#752=CARTESIAN_POINT('',(3.59210244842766,2.54,-3.81));
#753=VERTEX_POINT('',#752);
#754=EDGE_CURVE('E1199',#745,#753,#751,.T.);
#755=ORIENTED_EDGE('',*,*,#754,.T.);
#756=CARTESIAN_POINT('',(3.81,2.54,-3.81));
#757=DIRECTION('',(0.,1.,0.));
#758=DIRECTION('',(0.,0.,1.));
#759=AXIS2_PLACEMENT_3D('',#756,#757,#758);
#760=CIRCLE('',#759,0.217897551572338);
#761=CARTESIAN_POINT('',(3.81000000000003,2.54,-3.59210244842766));
#762=VERTEX_POINT('',#761);
#763=EDGE_CURVE('E1195',#753,#762,#760,.T.);
#764=ORIENTED_EDGE('',*,*,#763,.T.);
#765=EDGE_CURVE('E1188',#762,#732,#37,.F.);
#766=ORIENTED_EDGE('',*,*,#765,.T.);
#767=EDGE_LOOP('',(#734,#738,#747,#755,#764,#766));
#768=FACE_BOUND('',#767,.T.);
#769=ADVANCED_FACE('F30',(#768),#23,.T.);
#770=CARTESIAN_POINT('',(3.81000000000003,-1.27,-3.59210244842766));
#771=DIRECTION('',(1.,0.,0.));
#772=DIRECTION('',(0.,0.,-1.));
#773=AXIS2_PLACEMENT_3D('',#770,#771,#772);
#774=CYLINDRICAL_SURFACE('',#773,3.81);
#775=CARTESIAN_POINT('',(3.81000000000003,-1.27,-3.59210244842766));
#776=DIRECTION('',(-1.,0.,0.));
#777=DIRECTION('',(0.,0.,1.));
#778=AXIS2_PLACEMENT_3D('',#775,#776,#777);
#779=CIRCLE('',#778,3.81);
#780=EDGE_CURVE('E1160',#488,#762,#779,.T.);
#781=ORIENTED_EDGE('',*,*,#780,.F.);
#782=ORIENTED_EDGE('',*,*,#546,.T.);
#783=CARTESIAN_POINT('',(118.11,-1.27,-3.59210244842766));
#784=DIRECTION('',(1.,0.,0.));
#785=DIRECTION('',(0.,0.,-1.));
#786=AXIS2_PLACEMENT_3D('',#783,#784,#785);
#787=CIRCLE('',#786,3.81);
#788=EDGE_CURVE('E1163',#286,#539,#787,.T.);
#789=ORIENTED_EDGE('',*,*,#788,.F.);
#790=ORIENTED_EDGE('',*,*,#287,.F.);
#791=DIRECTION('',(-1.,0.,0.));
#792=VECTOR('',#791,1.);
#793=CARTESIAN_POINT('',(111.76,2.54,-3.59210244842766));
#794=LINE('',#793,#792);
#795=EDGE_CURVE('E907',#280,#259,#794,.T.);
#796=ORIENTED_EDGE('',*,*,#795,.T.);
#797=ORIENTED_EDGE('',*,*,#260,.F.);
#798=DIRECTION('',(-1.,0.,0.));
#799=VECTOR('',#798,1.);
#800=CARTESIAN_POINT('',(107.696,2.54,-3.59210244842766));
#801=LINE('',#800,#799);
#802=EDGE_CURVE('E876',#253,#232,#801,.T.);
#803=ORIENTED_EDGE('',*,*,#802,.T.);
#804=ORIENTED_EDGE('',*,*,#233,.F.);
#805=DIRECTION('',(-1.,0.,0.));
#806=VECTOR('',#805,1.);
#807=CARTESIAN_POINT('',(103.632,2.54,-3.59210244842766));
#808=LINE('',#807,#806);
#809=EDGE_CURVE('E845',#226,#205,#808,.T.);
#810=ORIENTED_EDGE('',*,*,#809,.T.);
#811=ORIENTED_EDGE('',*,*,#206,.F.);
#812=DIRECTION('',(-1.,0.,0.));
#813=VECTOR('',#812,1.);
#814=CARTESIAN_POINT('',(99.568,2.54,-3.59210244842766));
#815=LINE('',#814,#813);
#816=EDGE_CURVE('E814',#199,#178,#815,.T.);
#817=ORIENTED_EDGE('',*,*,#816,.T.);
#818=ORIENTED_EDGE('',*,*,#179,.F.);
#819=DIRECTION('',(-1.,0.,0.));
#820=VECTOR('',#819,1.);
#821=CARTESIAN_POINT('',(95.504,2.54,-3.59210244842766));
#822=LINE('',#821,#820);
#823=EDGE_CURVE('E783',#172,#151,#822,.T.);
#824=ORIENTED_EDGE('',*,*,#823,.T.);
#825=ORIENTED_EDGE('',*,*,#152,.F.);
#826=DIRECTION('',(-1.,0.,0.));
#827=VECTOR('',#826,1.);
#828=CARTESIAN_POINT('',(91.44,2.54,-3.59210244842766));
#829=LINE('',#828,#827);
#830=EDGE_CURVE('E752',#145,#39,#829,.T.);
#831=ORIENTED_EDGE('',*,*,#830,.T.);
#832=ORIENTED_EDGE('',*,*,#40,.F.);
#833=DIRECTION('',(-1.,0.,0.));
#834=VECTOR('',#833,1.);
#835=CARTESIAN_POINT('',(22.479,2.54,-3.59210244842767));
#836=LINE('',#835,#834);
#837=EDGE_CURVE('E683',#29,#66,#836,.T.);
#838=ORIENTED_EDGE('',*,*,#837,.T.);
#839=ORIENTED_EDGE('',*,*,#81,.F.);
#840=DIRECTION('',(-1.,0.,0.));
#841=VECTOR('',#840,1.);
#842=CARTESIAN_POINT('',(18.415,2.54,-3.59210244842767));
#843=LINE('',#842,#841);
#844=EDGE_CURVE('E1317',#78,#93,#843,.T.);
#845=ORIENTED_EDGE('',*,*,#844,.T.);
#846=ORIENTED_EDGE('',*,*,#108,.F.);
#847=DIRECTION('',(-1.,0.,0.));
#848=VECTOR('',#847,1.);
#849=CARTESIAN_POINT('',(14.351,2.54,-3.59210244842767));
#850=LINE('',#849,#848);
#851=EDGE_CURVE('E1315',#105,#120,#850,.T.);
#852=ORIENTED_EDGE('',*,*,#851,.T.);
#853=ORIENTED_EDGE('',*,*,#135,.F.);
#854=DIRECTION('',(-1.,0.,0.));
#855=VECTOR('',#854,1.);
#856=CARTESIAN_POINT('',(10.287,2.54,-3.59210244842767));
#857=LINE('',#856,#855);
#858=EDGE_CURVE('E1242',#132,#732,#857,.T.);
#859=ORIENTED_EDGE('',*,*,#858,.T.);
#860=ORIENTED_EDGE('',*,*,#765,.F.);
#861=EDGE_LOOP('',(#781,#782,#789,#790,#796,#797,#803,#804,#810,#811,#817,#818,#824,#825,#831,
#832,#838,#839,#845,#846,#852,#853,#859,#860));
#862=FACE_BOUND('',#861,.T.);
#863=ADVANCED_FACE('F1270',(#862),#774,.T.);
#864=CARTESIAN_POINT('',(118.11,-1.27,-5.08));
#865=DIRECTION('',(0.,-1.,0.));
#866=DIRECTION('',(0.,0.,-1.));
#867=AXIS2_PLACEMENT_3D('',#864,#865,#866);
#868=DEGENERATE_TOROIDAL_SURFACE('',#867,1.48789755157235,3.81,.T.);
#869=ORIENTED_EDGE('',*,*,#788,.T.);
#870=ORIENTED_EDGE('',*,*,#540,.F.);
#871=CARTESIAN_POINT('',(119.597897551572,-1.27,-5.08));
#872=DIRECTION('',(0.,0.,-1.));
#873=DIRECTION('',(-1.,0.,0.));
#874=AXIS2_PLACEMENT_3D('',#871,#872,#873);
#875=CIRCLE('',#874,3.81);
#876=EDGE_CURVE('E1157',#295,#530,#875,.T.);
#877=ORIENTED_EDGE('',*,*,#876,.F.);
#878=ORIENTED_EDGE('',*,*,#296,.F.);
#879=EDGE_LOOP('',(#869,#870,#877,#878));
#880=FACE_BOUND('',#879,.T.);
#881=ADVANCED_FACE('F1288',(#880),#868,.T.);
#882=CARTESIAN_POINT('',(3.81,-1.27,-3.81));
#883=DIRECTION('',(0.,-1.,0.));
#884=DIRECTION('',(0.,0.,-1.));
#885=AXIS2_PLACEMENT_3D('',#882,#883,#884);
#886=DEGENERATE_TOROIDAL_SURFACE('',#885,0.217897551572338,3.81,.T.);
#887=ORIENTED_EDGE('',*,*,#780,.T.);
#888=ORIENTED_EDGE('',*,*,#763,.F.);
#889=CARTESIAN_POINT('',(3.59210244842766,-1.27,-3.81));
#890=DIRECTION('',(0.,0.,-1.));
#891=DIRECTION('',(-1.,0.,0.));
#892=AXIS2_PLACEMENT_3D('',#889,#890,#891);
#893=CIRCLE('',#892,3.81);
#894=EDGE_CURVE('E1154',#486,#753,#893,.T.);
#895=ORIENTED_EDGE('',*,*,#894,.F.);
#896=ORIENTED_EDGE('',*,*,#489,.T.);
#897=EDGE_LOOP('',(#887,#888,#895,#896));
#898=FACE_BOUND('',#897,.T.);
#899=ADVANCED_FACE('F1275',(#898),#886,.T.);
#900=CARTESIAN_POINT('',(119.597897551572,-1.27,-29.972));
#901=DIRECTION('',(0.,0.,1.));
#902=DIRECTION('',(1.,0.,0.));
#903=AXIS2_PLACEMENT_3D('',#900,#901,#902);
#904=CYLINDRICAL_SURFACE('',#903,3.81);
#905=ORIENTED_EDGE('',*,*,#876,.T.);
#906=ORIENTED_EDGE('',*,*,#531,.F.);
#907=CARTESIAN_POINT('',(119.597897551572,-1.27,-29.972));
#908=DIRECTION('',(0.,0.,-1.));
#909=DIRECTION('',(-1.,0.,0.));
#910=AXIS2_PLACEMENT_3D('',#907,#908,#909);
#911=CIRCLE('',#910,3.81);
#912=EDGE_CURVE('E1151',#303,#522,#911,.T.);
#913=ORIENTED_EDGE('',*,*,#912,.F.);
#914=ORIENTED_EDGE('',*,*,#304,.F.);
#915=EDGE_LOOP('',(#905,#906,#913,#914));
#916=FACE_BOUND('',#915,.T.);
#917=ADVANCED_FACE('F1870',(#916),#904,.T.);
#918=CARTESIAN_POINT('',(3.59210244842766,-1.27,-3.81000000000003));
#919=DIRECTION('',(0.,0.,-1.));
#920=DIRECTION('',(-1.,0.,0.));
#921=AXIS2_PLACEMENT_3D('',#918,#919,#920);
#922=CYLINDRICAL_SURFACE('',#921,3.81);
#923=ORIENTED_EDGE('',*,*,#894,.T.);
#924=ORIENTED_EDGE('',*,*,#754,.F.);
#925=CARTESIAN_POINT('',(3.59210244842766,-1.27,-31.242));
#926=DIRECTION('',(0.,0.,-1.));
#927=DIRECTION('',(-1.,0.,0.));
#928=AXIS2_PLACEMENT_3D('',#925,#926,#927);
#929=CIRCLE('',#928,3.81);
#930=EDGE_CURVE('E1148',#496,#745,#929,.T.);
#931=ORIENTED_EDGE('',*,*,#930,.F.);
#932=ORIENTED_EDGE('',*,*,#497,.F.);
#933=EDGE_LOOP('',(#923,#924,#931,#932));
#934=FACE_BOUND('',#933,.T.);
#935=ADVANCED_FACE('F1278',(#934),#922,.T.);
#936=CARTESIAN_POINT('',(118.11,-1.27,-29.972));
#937=DIRECTION('',(0.,-1.,0.));
#938=DIRECTION('',(0.,0.,-1.));
#939=AXIS2_PLACEMENT_3D('',#936,#937,#938);
#940=DEGENERATE_TOROIDAL_SURFACE('',#939,1.48789755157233,3.81,.T.);
#941=ORIENTED_EDGE('',*,*,#912,.T.);
#942=ORIENTED_EDGE('',*,*,#523,.T.);
#943=CARTESIAN_POINT('',(118.11,-1.27,-31.4598975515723));
#944=DIRECTION('',(-1.,0.,0.));
#945=DIRECTION('',(0.,0.,1.));
#946=AXIS2_PLACEMENT_3D('',#943,#944,#945);
#947=CIRCLE('',#946,3.81);
#948=EDGE_CURVE('E1146',#312,#513,#947,.T.);
#949=ORIENTED_EDGE('',*,*,#948,.F.);
#950=ORIENTED_EDGE('',*,*,#313,.F.);
#951=EDGE_LOOP('',(#941,#942,#949,#950));
#952=FACE_BOUND('',#951,.T.);
#953=ADVANCED_FACE('F1863',(#952),#940,.T.);
#954=CARTESIAN_POINT('',(3.81,-1.27,-31.242));
#955=DIRECTION('',(0.,-1.,0.));
#956=DIRECTION('',(0.,0.,-1.));
#957=AXIS2_PLACEMENT_3D('',#954,#955,#956);
#958=DEGENERATE_TOROIDAL_SURFACE('',#957,0.217897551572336,3.81,.T.);
#959=ORIENTED_EDGE('',*,*,#930,.T.);
#960=ORIENTED_EDGE('',*,*,#746,.F.);
#961=CARTESIAN_POINT('',(3.81,-1.27,-31.4598975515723));
#962=DIRECTION('',(1.,0.,0.));
#963=DIRECTION('',(0.,0.,-1.));
#964=AXIS2_PLACEMENT_3D('',#961,#962,#963);
#965=CIRCLE('',#964,3.81);
#966=EDGE_CURVE('E1141',#505,#736,#965,.T.);
#967=ORIENTED_EDGE('',*,*,#966,.F.);
#968=ORIENTED_EDGE('',*,*,#506,.T.);
#969=EDGE_LOOP('',(#959,#960,#967,#968));
#970=FACE_BOUND('',#969,.T.);
#971=ADVANCED_FACE('F1860',(#970),#958,.T.);
#972=CARTESIAN_POINT('',(118.11,-1.27,-31.4598975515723));
#973=DIRECTION('',(-1.,0.,0.));
#974=DIRECTION('',(0.,0.,1.));
#975=AXIS2_PLACEMENT_3D('',#972,#973,#974);
#976=CYLINDRICAL_SURFACE('',#975,3.81);
#977=ORIENTED_EDGE('',*,*,#948,.T.);
#978=ORIENTED_EDGE('',*,*,#514,.T.);
#979=ORIENTED_EDGE('',*,*,#966,.T.);
#980=ORIENTED_EDGE('',*,*,#737,.F.);
#981=DIRECTION('',(1.,0.,0.));
#982=VECTOR('',#981,1.);
#983=CARTESIAN_POINT('',(8.255,2.54,-31.4598975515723));
#984=LINE('',#983,#982);
#985=EDGE_CURVE('E1229',#730,#124,#984,.T.);
#986=ORIENTED_EDGE('',*,*,#985,.T.);
#987=ORIENTED_EDGE('',*,*,#125,.F.);
#988=DIRECTION('',(1.,0.,0.));
#989=VECTOR('',#988,1.);
#990=CARTESIAN_POINT('',(12.319,2.54,-31.4598975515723));
#991=LINE('',#990,#989);
#992=EDGE_CURVE('E1343',#118,#97,#991,.T.);
#993=ORIENTED_EDGE('',*,*,#992,.T.);
#994=ORIENTED_EDGE('',*,*,#98,.F.);
#995=DIRECTION('',(1.,0.,0.));
#996=VECTOR('',#995,1.);
#997=CARTESIAN_POINT('',(16.383,2.54,-31.4598975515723));
#998=LINE('',#997,#996);
#999=EDGE_CURVE('E689',#91,#70,#998,.T.);
#1000=ORIENTED_EDGE('',*,*,#999,.T.);
#1001=ORIENTED_EDGE('',*,*,#71,.F.);
#1002=DIRECTION('',(1.,0.,0.));
#1003=VECTOR('',#1002,1.);
#1004=CARTESIAN_POINT('',(20.447,2.54,-31.4598975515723));
#1005=LINE('',#1004,#1003);
#1006=EDGE_CURVE('E673',#64,#31,#1005,.T.);
#1007=ORIENTED_EDGE('',*,*,#1006,.T.);
#1008=ORIENTED_EDGE('',*,*,#54,.F.);
#1009=DIRECTION('',(1.,0.,0.));
#1010=VECTOR('',#1009,1.);
#1011=CARTESIAN_POINT('',(89.408,2.54,-31.4598975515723));
#1012=LINE('',#1011,#1010);
#1013=EDGE_CURVE('E745',#47,#147,#1012,.T.);
#1014=ORIENTED_EDGE('',*,*,#1013,.T.);
#1015=ORIENTED_EDGE('',*,*,#162,.F.);
#1016=DIRECTION('',(1.,0.,0.));
#1017=VECTOR('',#1016,1.);
#1018=CARTESIAN_POINT('',(93.472,2.54,-31.4598975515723));
#1019=LINE('',#1018,#1017);
#1020=EDGE_CURVE('E743',#159,#174,#1019,.T.);
#1021=ORIENTED_EDGE('',*,*,#1020,.T.);
#1022=ORIENTED_EDGE('',*,*,#189,.F.);
#1023=DIRECTION('',(1.,0.,0.));
#1024=VECTOR('',#1023,1.);
#1025=CARTESIAN_POINT('',(97.536,2.54,-31.4598975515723));
#1026=LINE('',#1025,#1024);
#1027=EDGE_CURVE('E808',#186,#201,#1026,.T.);
#1028=ORIENTED_EDGE('',*,*,#1027,.T.);
#1029=ORIENTED_EDGE('',*,*,#216,.F.);
#1030=DIRECTION('',(1.,0.,0.));
#1031=VECTOR('',#1030,1.);
#1032=CARTESIAN_POINT('',(101.6,2.54,-31.4598975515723));
#1033=LINE('',#1032,#1031);
#1034=EDGE_CURVE('E839',#213,#228,#1033,.T.);
#1035=ORIENTED_EDGE('',*,*,#1034,.T.);
#1036=ORIENTED_EDGE('',*,*,#243,.F.);
#1037=DIRECTION('',(1.,0.,0.));
#1038=VECTOR('',#1037,1.);
#1039=CARTESIAN_POINT('',(105.664,2.54,-31.4598975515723));
#1040=LINE('',#1039,#1038);
#1041=EDGE_CURVE('E870',#240,#255,#1040,.T.);
#1042=ORIENTED_EDGE('',*,*,#1041,.T.);
#1043=ORIENTED_EDGE('',*,*,#270,.F.);
#1044=DIRECTION('',(1.,0.,0.));
#1045=VECTOR('',#1044,1.);
#1046=CARTESIAN_POINT('',(109.728,2.54,-31.4598975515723));
#1047=LINE('',#1046,#1045);
#1048=EDGE_CURVE('E901',#267,#282,#1047,.T.);
#1049=ORIENTED_EDGE('',*,*,#1048,.T.);
#1050=ORIENTED_EDGE('',*,*,#315,.F.);
#1051=EDGE_LOOP('',(#977,#978,#979,#980,#986,#987,#993,#994,#1000,#1001,#1007,#1008,#1014,#1015,
#1021,#1022,#1028,#1029,#1035,#1036,#1042,#1043,#1049,#1050));
#1052=FACE_BOUND('',#1051,.T.);
#1053=ADVANCED_FACE('F686',(#1052),#976,.T.);
#1054=CARTESIAN_POINT('',(48.26,-1.524,-4.826));
#1055=DIRECTION('',(0.,-1.,0.));
#1056=DIRECTION('',(1.,0.,0.));
#1057=AXIS2_PLACEMENT_3D('',#1054,#1055,#1056);
#1058=PLANE('',#1057);
#1059=CARTESIAN_POINT('',(110.236,-1.524,-4.064));
#1060=DIRECTION('',(0.,-1.,0.));
#1061=DIRECTION('',(1.,0.,0.));
#1062=AXIS2_PLACEMENT_3D('',#1059,#1060,#1061);
#1063=CIRCLE('',#1062,0.381);
#1064=CARTESIAN_POINT('',(110.617,-1.524,-4.064));
#1065=VERTEX_POINT('',#1064);
#1066=CARTESIAN_POINT('',(110.236,-1.524,-3.683));
#1067=VERTEX_POINT('',#1066);
#1068=EDGE_CURVE('E1972',#1065,#1067,#1063,.T.);
#1069=ORIENTED_EDGE('',*,*,#1068,.T.);
#1070=DIRECTION('',(1.,0.,0.));
#1071=VECTOR('',#1070,1.);
#1072=CARTESIAN_POINT('',(51.9587482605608,-1.524,-3.683));
#1073=LINE('',#1072,#1071);
#1074=CARTESIAN_POINT('',(51.9587482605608,-1.524,-3.683));
#1075=VERTEX_POINT('',#1074);
#1076=EDGE_CURVE('E1970',#1067,#1075,#1073,.F.);
#1077=ORIENTED_EDGE('',*,*,#1076,.T.);
#1078=DIRECTION('',(0.,0.,1.));
#1079=VECTOR('',#1078,1.);
#1080=CARTESIAN_POINT('',(51.9587482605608,-1.524,-4.826));
#1081=LINE('',#1080,#1079);
#1082=CARTESIAN_POINT('',(51.9587482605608,-1.524,-4.445));
#1083=VERTEX_POINT('',#1082);
#1084=EDGE_CURVE('E2152',#1075,#1083,#1081,.F.);
#1085=ORIENTED_EDGE('',*,*,#1084,.T.);
#1086=DIRECTION('',(1.,0.,0.));
#1087=VECTOR('',#1086,1.);
#1088=CARTESIAN_POINT('',(48.26,-1.524,-4.445));
#1089=LINE('',#1088,#1087);
#1090=CARTESIAN_POINT('',(110.236,-1.524,-4.445));
#1091=VERTEX_POINT('',#1090);
#1092=EDGE_CURVE('E1976',#1083,#1091,#1089,.T.);
#1093=ORIENTED_EDGE('',*,*,#1092,.T.);
#1094=CARTESIAN_POINT('',(110.236,-1.524,-4.064));
#1095=DIRECTION('',(0.,-1.,0.));
#1096=DIRECTION('',(1.,0.,0.));
#1097=AXIS2_PLACEMENT_3D('',#1094,#1095,#1096);
#1098=CIRCLE('',#1097,0.381);
#1099=EDGE_CURVE('E1974',#1091,#1065,#1098,.T.);
#1100=ORIENTED_EDGE('',*,*,#1099,.T.);
#1101=EDGE_LOOP('',(#1069,#1077,#1085,#1093,#1100));
#1102=FACE_BOUND('',#1101,.T.);
#1103=ADVANCED_FACE('F1839',(#1102),#1058,.T.);
#1104=CARTESIAN_POINT('',(42.9058227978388,-10.9643544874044,-4.826));
#1105=DIRECTION('',(0.86983862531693,-0.493336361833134,0.));
#1106=DIRECTION('',(0.493336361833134,0.86983862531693,0.));
#1107=AXIS2_PLACEMENT_3D('',#1104,#1105,#1106);
#1108=PLANE('',#1107);
#1109=DIRECTION('',(0.,0.,1.));
#1110=VECTOR('',#1109,1.);
#1111=CARTESIAN_POINT('',(46.4352729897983,-4.7413141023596,-3.302));
#1112=LINE('',#1111,#1110);
#1113=CARTESIAN_POINT('',(46.4352729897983,-4.7413141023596,-4.445));
#1114=VERTEX_POINT('',#1113);
#1115=CARTESIAN_POINT('',(46.4352729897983,-4.7413141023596,-3.683));
#1116=VERTEX_POINT('',#1115);
#1117=EDGE_CURVE('E2155',#1114,#1116,#1112,.T.);
#1118=ORIENTED_EDGE('',*,*,#1117,.T.);
#1119=DIRECTION('',(0.493336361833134,0.86983862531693,0.));
#1120=VECTOR('',#1119,1.);
#1121=CARTESIAN_POINT('',(42.9058227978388,-10.9643544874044,-3.683));
#1122=LINE('',#1121,#1120);
#1123=CARTESIAN_POINT('',(42.9058227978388,-10.9643544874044,-3.683));
#1124=VERTEX_POINT('',#1123);
#1125=EDGE_CURVE('E1929',#1116,#1124,#1122,.F.);
#1126=ORIENTED_EDGE('',*,*,#1125,.T.);
#1127=DIRECTION('',(0.,0.,1.));
#1128=VECTOR('',#1127,1.);
#1129=CARTESIAN_POINT('',(42.9058227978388,-10.9643544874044,-4.826));
#1130=LINE('',#1129,#1128);
#1131=CARTESIAN_POINT('',(42.9058227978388,-10.9643544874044,-4.445));
#1132=VERTEX_POINT('',#1131);
#1133=EDGE_CURVE('E1138',#1132,#1124,#1130,.T.);
#1134=ORIENTED_EDGE('',*,*,#1133,.F.);
#1135=DIRECTION('',(0.493336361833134,0.86983862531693,0.));
#1136=VECTOR('',#1135,1.);
#1137=CARTESIAN_POINT('',(42.9058227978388,-10.9643544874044,-4.445));
#1138=LINE('',#1137,#1136);
#1139=EDGE_CURVE('E1932',#1132,#1114,#1138,.T.);
#1140=ORIENTED_EDGE('',*,*,#1139,.T.);
#1141=EDGE_LOOP('',(#1118,#1126,#1134,#1140));
#1142=FACE_BOUND('',#1141,.T.);
#1143=ADVANCED_FACE('F1842',(#1142),#1108,.T.);
#1144=CARTESIAN_POINT('',(36.83,-7.5184,-4.826));
#1145=DIRECTION('',(0.,0.,1.));
#1146=DIRECTION('',(1.,0.,0.));
#1147=AXIS2_PLACEMENT_3D('',#1144,#1145,#1146);
#1148=CYLINDRICAL_SURFACE('',#1147,6.98499999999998);
#1149=ORIENTED_EDGE('',*,*,#1133,.T.);
#1150=CARTESIAN_POINT('',(36.83,-7.5184,-3.683));
#1151=DIRECTION('',(0.,0.,-1.));
#1152=DIRECTION('',(-1.,0.,0.));
#1153=AXIS2_PLACEMENT_3D('',#1150,#1151,#1152);
#1154=CIRCLE('',#1153,6.98499999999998);
#1155=CARTESIAN_POINT('',(30.7541772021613,-10.9643544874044,-3.683));
#1156=VERTEX_POINT('',#1155);
#1157=EDGE_CURVE('E1978',#1124,#1156,#1154,.T.);
#1158=ORIENTED_EDGE('',*,*,#1157,.T.);
#1159=DIRECTION('',(0.,0.,1.));
#1160=VECTOR('',#1159,1.);
#1161=CARTESIAN_POINT('',(30.7541772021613,-10.9643544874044,-4.826));
#1162=LINE('',#1161,#1160);
#1163=CARTESIAN_POINT('',(30.7541772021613,-10.9643544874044,-4.445));
#1164=VERTEX_POINT('',#1163);
#1165=EDGE_CURVE('E1137',#1164,#1156,#1162,.T.);
#1166=ORIENTED_EDGE('',*,*,#1165,.F.);
#1167=CARTESIAN_POINT('',(36.83,-7.5184,-4.445));
#1168=DIRECTION('',(0.,0.,-1.));
#1169=DIRECTION('',(-1.,0.,0.));
#1170=AXIS2_PLACEMENT_3D('',#1167,#1168,#1169);
#1171=CIRCLE('',#1170,6.98499999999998);
#1172=EDGE_CURVE('E1980',#1164,#1132,#1171,.F.);
#1173=ORIENTED_EDGE('',*,*,#1172,.T.);
#1174=EDGE_LOOP('',(#1149,#1158,#1166,#1173));
#1175=FACE_BOUND('',#1174,.T.);
#1176=ADVANCED_FACE('F1846',(#1175),#1148,.T.);
#1177=CARTESIAN_POINT('',(30.7541772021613,-10.9643544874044,-4.826));
#1178=DIRECTION('',(0.869838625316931,0.493336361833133,0.));
#1179=DIRECTION('',(-0.493336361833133,0.869838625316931,0.));
#1180=AXIS2_PLACEMENT_3D('',#1177,#1178,#1179);
#1181=PLANE('',#1180);
#1182=ORIENTED_EDGE('',*,*,#1165,.T.);
#1183=DIRECTION('',(-0.493336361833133,0.869838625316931,0.));
#1184=VECTOR('',#1183,1.);
#1185=CARTESIAN_POINT('',(30.7541772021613,-10.9643544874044,-3.683));
#1186=LINE('',#1185,#1184);
#1187=CARTESIAN_POINT('',(27.2247270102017,-4.7413141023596,-3.683));
#1188=VERTEX_POINT('',#1187);
#1189=EDGE_CURVE('E2015',#1156,#1188,#1186,.T.);
#1190=ORIENTED_EDGE('',*,*,#1189,.T.);
#1191=DIRECTION('',(0.,0.,1.));
#1192=VECTOR('',#1191,1.);
#1193=CARTESIAN_POINT('',(27.2247270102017,-4.7413141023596,-4.826));
#1194=LINE('',#1193,#1192);
#1195=CARTESIAN_POINT('',(27.2247270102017,-4.7413141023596,-4.445));
#1196=VERTEX_POINT('',#1195);
#1197=EDGE_CURVE('E2158',#1188,#1196,#1194,.F.);
#1198=ORIENTED_EDGE('',*,*,#1197,.T.);
#1199=DIRECTION('',(-0.493336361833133,0.869838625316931,0.));
#1200=VECTOR('',#1199,1.);
#1201=CARTESIAN_POINT('',(30.7541772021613,-10.9643544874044,-4.445));
#1202=LINE('',#1201,#1200);
#1203=EDGE_CURVE('E2017',#1196,#1164,#1202,.F.);
#1204=ORIENTED_EDGE('',*,*,#1203,.T.);
#1205=EDGE_LOOP('',(#1182,#1190,#1198,#1204));
#1206=FACE_BOUND('',#1205,.T.);
#1207=ADVANCED_FACE('F1850',(#1206),#1181,.F.);
#1208=CARTESIAN_POINT('',(5.08,-1.524,-4.826));
#1209=DIRECTION('',(0.,-1.,0.));
#1210=DIRECTION('',(1.,0.,0.));
#1211=AXIS2_PLACEMENT_3D('',#1208,#1209,#1210);
#1212=PLANE('',#1211);
#1213=DIRECTION('',(0.,0.,1.));
#1214=VECTOR('',#1213,1.);
#1215=CARTESIAN_POINT('',(21.7012517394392,-1.524,-4.826));
#1216=LINE('',#1215,#1214);
#1217=CARTESIAN_POINT('',(21.7012517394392,-1.524,-4.445));
#1218=VERTEX_POINT('',#1217);
#1219=CARTESIAN_POINT('',(21.7012517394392,-1.524,-3.683));
#1220=VERTEX_POINT('',#1219);
#1221=EDGE_CURVE('E2161',#1218,#1220,#1216,.T.);
#1222=ORIENTED_EDGE('',*,*,#1221,.T.);
#1223=DIRECTION('',(1.,0.,0.));
#1224=VECTOR('',#1223,1.);
#1225=CARTESIAN_POINT('',(5.842,-1.524,-3.683));
#1226=LINE('',#1225,#1224);
#1227=CARTESIAN_POINT('',(5.842,-1.524,-3.683));
#1228=VERTEX_POINT('',#1227);
#1229=EDGE_CURVE('E2119',#1220,#1228,#1226,.F.);
#1230=ORIENTED_EDGE('',*,*,#1229,.T.);
#1231=CARTESIAN_POINT('',(5.842,-1.524,-4.064));
#1232=DIRECTION('',(0.,-1.,0.));
#1233=DIRECTION('',(1.,0.,0.));
#1234=AXIS2_PLACEMENT_3D('',#1231,#1232,#1233);
#1235=CIRCLE('',#1234,0.381);
#1236=CARTESIAN_POINT('',(5.461,-1.524,-4.064));
#1237=VERTEX_POINT('',#1236);
#1238=EDGE_CURVE('E2121',#1228,#1237,#1235,.T.);
#1239=ORIENTED_EDGE('',*,*,#1238,.T.);
#1240=CARTESIAN_POINT('',(5.842,-1.524,-4.064));
#1241=DIRECTION('',(0.,-1.,0.));
#1242=DIRECTION('',(1.,0.,0.));
#1243=AXIS2_PLACEMENT_3D('',#1240,#1241,#1242);
#1244=CIRCLE('',#1243,0.381);
#1245=CARTESIAN_POINT('',(5.842,-1.524,-4.445));
#1246=VERTEX_POINT('',#1245);
#1247=EDGE_CURVE('E2124',#1237,#1246,#1244,.T.);
#1248=ORIENTED_EDGE('',*,*,#1247,.T.);
#1249=DIRECTION('',(1.,0.,0.));
#1250=VECTOR('',#1249,1.);
#1251=CARTESIAN_POINT('',(5.08,-1.524,-4.445));
#1252=LINE('',#1251,#1250);
#1253=EDGE_CURVE('E1922',#1246,#1218,#1252,.T.);
#1254=ORIENTED_EDGE('',*,*,#1253,.T.);
#1255=EDGE_LOOP('',(#1222,#1230,#1239,#1248,#1254));
#1256=FACE_BOUND('',#1255,.T.);
#1257=ADVANCED_FACE('F1837',(#1256),#1212,.T.);
#1258=CARTESIAN_POINT('',(36.83,-7.5184,-4.826));
#1259=DIRECTION('',(0.,0.,-1.));
#1260=DIRECTION('',(-1.,0.,0.));
#1261=AXIS2_PLACEMENT_3D('',#1258,#1259,#1260);
#1262=PLANE('',#1261);
#1263=CARTESIAN_POINT('',(21.7012517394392,-7.874,-4.826));
#1264=DIRECTION('',(0.,0.,-1.));
#1265=DIRECTION('',(-1.,0.,0.));
#1266=AXIS2_PLACEMENT_3D('',#1263,#1264,#1265);
#1267=CIRCLE('',#1266,6.731);
#1268=CARTESIAN_POINT('',(27.5561355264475,-4.55335294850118,-4.826));
#1269=VERTEX_POINT('',#1268);
#1270=CARTESIAN_POINT('',(21.7012517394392,-1.143,-4.826));
#1271=VERTEX_POINT('',#1270);
#1272=EDGE_CURVE('E2061',#1269,#1271,#1267,.F.);
#1273=ORIENTED_EDGE('',*,*,#1272,.T.);
#1274=DIRECTION('',(1.,0.,0.));
#1275=VECTOR('',#1274,1.);
#1276=CARTESIAN_POINT('',(36.83,-1.143,-4.826));
#1277=LINE('',#1276,#1275);
#1278=CARTESIAN_POINT('',(5.842,-1.143,-4.826));
#1279=VERTEX_POINT('',#1278);
#1280=EDGE_CURVE('E2059',#1271,#1279,#1277,.F.);
#1281=ORIENTED_EDGE('',*,*,#1280,.T.);
#1282=DIRECTION('',(0.,-1.,0.));
#1283=VECTOR('',#1282,1.);
#1284=CARTESIAN_POINT('',(5.842,-7.51839999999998,-4.826));
#1285=LINE('',#1284,#1283);
#1286=CARTESIAN_POINT('',(5.842,-0.381,-4.826));
#1287=VERTEX_POINT('',#1286);
#1288=EDGE_CURVE('E706',#1279,#1287,#1285,.F.);
#1289=ORIENTED_EDGE('',*,*,#1288,.T.);
#1290=DIRECTION('',(1.,0.,0.));
#1291=VECTOR('',#1290,1.);
#1292=CARTESIAN_POINT('',(36.83,-0.381,-4.826));
#1293=LINE('',#1292,#1291);
#1294=CARTESIAN_POINT('',(110.236,-0.381,-4.826));
#1295=VERTEX_POINT('',#1294);
#1296=EDGE_CURVE('E2073',#1287,#1295,#1293,.T.);
#1297=ORIENTED_EDGE('',*,*,#1296,.T.);
#1298=DIRECTION('',(0.,-1.,0.));
#1299=VECTOR('',#1298,1.);
#1300=CARTESIAN_POINT('',(110.236,-1.524,-4.826));
#1301=LINE('',#1300,#1299);
#1302=CARTESIAN_POINT('',(110.236,-1.143,-4.826));
#1303=VERTEX_POINT('',#1302);
#1304=EDGE_CURVE('E700',#1295,#1303,#1301,.T.);
#1305=ORIENTED_EDGE('',*,*,#1304,.T.);
#1306=DIRECTION('',(1.,0.,0.));
#1307=VECTOR('',#1306,1.);
#1308=CARTESIAN_POINT('',(36.83,-1.143,-4.826));
#1309=LINE('',#1308,#1307);
#1310=CARTESIAN_POINT('',(51.9587482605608,-1.143,-4.826));
#1311=VERTEX_POINT('',#1310);
#1312=EDGE_CURVE('E2067',#1303,#1311,#1309,.F.);
#1313=ORIENTED_EDGE('',*,*,#1312,.T.);
#1314=CARTESIAN_POINT('',(51.9587482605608,-7.874,-4.826));
#1315=DIRECTION('',(0.,0.,-1.));
#1316=DIRECTION('',(-1.,0.,0.));
#1317=AXIS2_PLACEMENT_3D('',#1314,#1315,#1316);
#1318=CIRCLE('',#1317,6.731);
#1319=CARTESIAN_POINT('',(46.1038644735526,-4.55335294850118,-4.826));
#1320=VERTEX_POINT('',#1319);
#1321=EDGE_CURVE('E2071',#1311,#1320,#1318,.F.);
#1322=ORIENTED_EDGE('',*,*,#1321,.T.);
#1323=DIRECTION('',(0.493336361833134,0.86983862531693,0.));
#1324=VECTOR('',#1323,1.);
#1325=CARTESIAN_POINT('',(42.574414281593,-10.776393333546,-4.826));
#1326=LINE('',#1325,#1324);
#1327=CARTESIAN_POINT('',(42.574414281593,-10.776393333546,-4.826));
#1328=VERTEX_POINT('',#1327);
#1329=EDGE_CURVE('E2069',#1320,#1328,#1326,.F.);
#1330=ORIENTED_EDGE('',*,*,#1329,.T.);
#1331=CARTESIAN_POINT('',(36.83,-7.5184,-4.826));
#1332=DIRECTION('',(0.,0.,-1.));
#1333=DIRECTION('',(-1.,0.,0.));
#1334=AXIS2_PLACEMENT_3D('',#1331,#1332,#1333);
#1335=CIRCLE('',#1334,6.60399999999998);
#1336=CARTESIAN_POINT('',(31.085585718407,-10.776393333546,-4.826));
#1337=VERTEX_POINT('',#1336);
#1338=EDGE_CURVE('E2065',#1328,#1337,#1335,.T.);
#1339=ORIENTED_EDGE('',*,*,#1338,.T.);
#1340=DIRECTION('',(-0.493336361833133,0.869838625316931,0.));
#1341=VECTOR('',#1340,1.);
#1342=CARTESIAN_POINT('',(27.5561355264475,-4.55335294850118,-4.826));
#1343=LINE('',#1342,#1341);
#1344=EDGE_CURVE('E2063',#1337,#1269,#1343,.T.);
#1345=ORIENTED_EDGE('',*,*,#1344,.T.);
#1346=EDGE_LOOP('',(#1273,#1281,#1289,#1297,#1305,#1313,#1322,#1330,#1339,#1345));
#1347=FACE_BOUND('',#1346,.T.);
#1348=ADVANCED_FACE('F1832',(#1347),#1262,.T.);
#1349=CARTESIAN_POINT('',(5.842,-7.51839999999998,-4.064));
#1350=DIRECTION('',(0.,1.,0.));
#1351=DIRECTION('',(-1.,0.,0.));
#1352=AXIS2_PLACEMENT_3D('',#1349,#1350,#1351);
#1353=CYLINDRICAL_SURFACE('',#1352,0.762);
#1354=DIRECTION('',(0.,-1.,0.));
#1355=VECTOR('',#1354,1.);
#1356=CARTESIAN_POINT('',(5.08,0.,-4.064));
#1357=LINE('',#1356,#1355);
#1358=CARTESIAN_POINT('',(5.08,-1.143,-4.064));
#1359=VERTEX_POINT('',#1358);
#1360=CARTESIAN_POINT('',(5.08,-0.381,-4.064));
#1361=VERTEX_POINT('',#1360);
#1362=EDGE_CURVE('E1134',#1359,#1361,#1357,.F.);
#1363=ORIENTED_EDGE('',*,*,#1362,.F.);
#1364=CARTESIAN_POINT('',(5.842,-1.143,-4.064));
#1365=DIRECTION('',(0.,-1.,0.));
#1366=DIRECTION('',(1.,0.,0.));
#1367=AXIS2_PLACEMENT_3D('',#1364,#1365,#1366);
#1368=CIRCLE('',#1367,0.762);
#1369=EDGE_CURVE('E2114',#1359,#651,#1368,.F.);
#1370=ORIENTED_EDGE('',*,*,#1369,.T.);
#1371=ORIENTED_EDGE('',*,*,#652,.F.);
#1372=CARTESIAN_POINT('',(5.842,-0.381,-4.064));
#1373=DIRECTION('',(0.,1.,0.));
#1374=DIRECTION('',(0.,0.,1.));
#1375=AXIS2_PLACEMENT_3D('',#1372,#1373,#1374);
#1376=CIRCLE('',#1375,0.762);
#1377=EDGE_CURVE('E2117',#643,#1361,#1376,.F.);
#1378=ORIENTED_EDGE('',*,*,#1377,.T.);
#1379=EDGE_LOOP('',(#1363,#1370,#1371,#1378));
#1380=FACE_BOUND('',#1379,.T.);
#1381=ADVANCED_FACE('F1829',(#1380),#1353,.T.);
#1382=CARTESIAN_POINT('',(5.842,0.,-4.064));
#1383=DIRECTION('',(0.,-1.,0.));
#1384=DIRECTION('',(1.,0.,0.));
#1385=AXIS2_PLACEMENT_3D('',#1382,#1383,#1384);
#1386=CYLINDRICAL_SURFACE('',#1385,0.762);
#1387=ORIENTED_EDGE('',*,*,#1288,.F.);
#1388=CARTESIAN_POINT('',(5.842,-1.143,-4.064));
#1389=DIRECTION('',(0.,-1.,0.));
#1390=DIRECTION('',(1.,0.,0.));
#1391=AXIS2_PLACEMENT_3D('',#1388,#1389,#1390);
#1392=CIRCLE('',#1391,0.762);
#1393=EDGE_CURVE('E2110',#1279,#1359,#1392,.F.);
#1394=ORIENTED_EDGE('',*,*,#1393,.T.);
#1395=ORIENTED_EDGE('',*,*,#1362,.T.);
#1396=CARTESIAN_POINT('',(5.842,-0.381,-4.064));
#1397=DIRECTION('',(0.,1.,0.));
#1398=DIRECTION('',(0.,0.,1.));
#1399=AXIS2_PLACEMENT_3D('',#1396,#1397,#1398);
#1400=CIRCLE('',#1399,0.762);
#1401=EDGE_CURVE('E2112',#1361,#1287,#1400,.F.);
#1402=ORIENTED_EDGE('',*,*,#1401,.T.);
#1403=EDGE_LOOP('',(#1387,#1394,#1395,#1402));
#1404=FACE_BOUND('',#1403,.T.);
#1405=ADVANCED_FACE('F1825',(#1404),#1386,.T.);
#1406=CARTESIAN_POINT('',(110.236,-7.5184,-4.064));
#1407=DIRECTION('',(0.,1.,0.));
#1408=DIRECTION('',(0.,0.,1.));
#1409=AXIS2_PLACEMENT_3D('',#1406,#1407,#1408);
#1410=CYLINDRICAL_SURFACE('',#1409,0.762);
#1411=DIRECTION('',(0.,-1.,0.));
#1412=VECTOR('',#1411,1.);
#1413=CARTESIAN_POINT('',(110.998,0.,-4.064));
#1414=LINE('',#1413,#1412);
#1415=CARTESIAN_POINT('',(110.998,-1.143,-4.064));
#1416=VERTEX_POINT('',#1415);
#1417=CARTESIAN_POINT('',(110.998,-0.381,-4.064));
#1418=VERTEX_POINT('',#1417);
#1419=EDGE_CURVE('E1131',#1416,#1418,#1414,.F.);
#1420=ORIENTED_EDGE('',*,*,#1419,.F.);
#1421=CARTESIAN_POINT('',(110.236,-1.143,-4.064));
#1422=DIRECTION('',(0.,-1.,0.));
#1423=DIRECTION('',(1.,0.,0.));
#1424=AXIS2_PLACEMENT_3D('',#1421,#1422,#1423);
#1425=CIRCLE('',#1424,0.762);
#1426=EDGE_CURVE('E1962',#1416,#1303,#1425,.F.);
#1427=ORIENTED_EDGE('',*,*,#1426,.T.);
#1428=ORIENTED_EDGE('',*,*,#1304,.F.);
#1429=CARTESIAN_POINT('',(110.236,-0.381,-4.064));
#1430=DIRECTION('',(0.,1.,0.));
#1431=DIRECTION('',(0.,0.,1.));
#1432=AXIS2_PLACEMENT_3D('',#1429,#1430,#1431);
#1433=CIRCLE('',#1432,0.762);
#1434=EDGE_CURVE('E1964',#1295,#1418,#1433,.F.);
#1435=ORIENTED_EDGE('',*,*,#1434,.T.);
#1436=EDGE_LOOP('',(#1420,#1427,#1428,#1435));
#1437=FACE_BOUND('',#1436,.T.);
#1438=ADVANCED_FACE('F1821',(#1437),#1410,.T.);
#1439=CARTESIAN_POINT('',(110.236,0.,-4.064));
#1440=DIRECTION('',(0.,-1.,0.));
#1441=DIRECTION('',(0.,0.,-1.));
#1442=AXIS2_PLACEMENT_3D('',#1439,#1440,#1441);
#1443=CYLINDRICAL_SURFACE('',#1442,0.762);
#1444=ORIENTED_EDGE('',*,*,#636,.F.);
#1445=CARTESIAN_POINT('',(110.236,-1.143,-4.064));
#1446=DIRECTION('',(0.,-1.,0.));
#1447=DIRECTION('',(1.,0.,0.));
#1448=AXIS2_PLACEMENT_3D('',#1445,#1446,#1447);
#1449=CIRCLE('',#1448,0.762);
#1450=EDGE_CURVE('E1966',#633,#1416,#1449,.F.);
#1451=ORIENTED_EDGE('',*,*,#1450,.T.);
#1452=ORIENTED_EDGE('',*,*,#1419,.T.);
#1453=CARTESIAN_POINT('',(110.236,-0.381,-4.064));
#1454=DIRECTION('',(0.,1.,0.));
#1455=DIRECTION('',(0.,0.,1.));
#1456=AXIS2_PLACEMENT_3D('',#1453,#1454,#1455);
#1457=CIRCLE('',#1456,0.762);
#1458=EDGE_CURVE('E1968',#1418,#635,#1457,.F.);
#1459=ORIENTED_EDGE('',*,*,#1458,.T.);
#1460=EDGE_LOOP('',(#1444,#1451,#1452,#1459));
#1461=FACE_BOUND('',#1460,.T.);
#1462=ADVANCED_FACE('F1817',(#1461),#1443,.T.);
#1463=CARTESIAN_POINT('',(36.83,-7.5184,-2.032));
#1464=DIRECTION('',(0.,0.,-1.));
#1465=DIRECTION('',(-1.,0.,0.));
#1466=AXIS2_PLACEMENT_3D('',#1463,#1464,#1465);
#1467=CYLINDRICAL_SURFACE('',#1466,4.064);
#1468=ORIENTED_EDGE('',*,*,#615,.F.);
#1469=EDGE_LOOP('',(#1468));
#1470=FACE_BOUND('',#1469,.T.);
#1471=ORIENTED_EDGE('',*,*,#720,.T.);
#1472=EDGE_LOOP('',(#1471));
#1473=FACE_BOUND('',#1472,.T.);
#1474=ADVANCED_FACE('F1803',(#1470,#1473),#1467,.T.);
#1475=CARTESIAN_POINT('',(0.,-7.5184,3.048));
#1476=DIRECTION('',(0.,-0.581238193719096,0.813733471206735));
#1477=DIRECTION('',(0.,-0.813733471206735,-0.581238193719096));
#1478=AXIS2_PLACEMENT_3D('',#1475,#1476,#1477);
#1479=PLANE('',#1478);
#1480=ORIENTED_EDGE('',*,*,#583,.T.);
#1481=ORIENTED_EDGE('',*,*,#598,.F.);
#1482=EDGE_LOOP('',(#1480,#1481));
#1483=FACE_BOUND('',#1482,.T.);
#1484=ADVANCED_FACE('F1799',(#1483),#1479,.T.);
#1485=CARTESIAN_POINT('',(21.7012517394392,-7.874,-4.826));
#1486=DIRECTION('',(0.,0.,1.));
#1487=DIRECTION('',(1.,0.,0.));
#1488=AXIS2_PLACEMENT_3D('',#1485,#1486,#1487);
#1489=CYLINDRICAL_SURFACE('',#1488,6.35);
#1490=ORIENTED_EDGE('',*,*,#1197,.F.);
#1491=CARTESIAN_POINT('',(21.7012517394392,-7.874,-3.683));
#1492=DIRECTION('',(0.,0.,-1.));
#1493=DIRECTION('',(-1.,0.,0.));
#1494=AXIS2_PLACEMENT_3D('',#1491,#1492,#1493);
#1495=CIRCLE('',#1494,6.35);
#1496=EDGE_CURVE('E2023',#1188,#1220,#1495,.F.);
#1497=ORIENTED_EDGE('',*,*,#1496,.T.);
#1498=ORIENTED_EDGE('',*,*,#1221,.F.);
#1499=CARTESIAN_POINT('',(21.7012517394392,-7.874,-4.445));
#1500=DIRECTION('',(0.,0.,-1.));
#1501=DIRECTION('',(-1.,0.,0.));
#1502=AXIS2_PLACEMENT_3D('',#1499,#1500,#1501);
#1503=CIRCLE('',#1502,6.35);
#1504=EDGE_CURVE('E2025',#1218,#1196,#1503,.T.);
#1505=ORIENTED_EDGE('',*,*,#1504,.T.);
#1506=EDGE_LOOP('',(#1490,#1497,#1498,#1505));
#1507=FACE_BOUND('',#1506,.T.);
#1508=ADVANCED_FACE('F1795',(#1507),#1489,.F.);
#1509=CARTESIAN_POINT('',(51.9587482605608,-7.874,-4.826));
#1510=DIRECTION('',(0.,0.,-1.));
#1511=DIRECTION('',(-1.,0.,0.));
#1512=AXIS2_PLACEMENT_3D('',#1509,#1510,#1511);
#1513=CYLINDRICAL_SURFACE('',#1512,6.35);
#1514=ORIENTED_EDGE('',*,*,#1084,.F.);
#1515=CARTESIAN_POINT('',(51.9587482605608,-7.874,-3.683));
#1516=DIRECTION('',(0.,0.,-1.));
#1517=DIRECTION('',(-1.,0.,0.));
#1518=AXIS2_PLACEMENT_3D('',#1515,#1516,#1517);
#1519=CIRCLE('',#1518,6.35);
#1520=EDGE_CURVE('E1906',#1075,#1116,#1519,.F.);
#1521=ORIENTED_EDGE('',*,*,#1520,.T.);
#1522=ORIENTED_EDGE('',*,*,#1117,.F.);
#1523=CARTESIAN_POINT('',(51.9587482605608,-7.874,-4.445));
#1524=DIRECTION('',(0.,0.,-1.));
#1525=DIRECTION('',(-1.,0.,0.));
#1526=AXIS2_PLACEMENT_3D('',#1523,#1524,#1525);
#1527=CIRCLE('',#1526,6.35);
#1528=EDGE_CURVE('E1904',#1114,#1083,#1527,.T.);
#1529=ORIENTED_EDGE('',*,*,#1528,.T.);
#1530=EDGE_LOOP('',(#1514,#1521,#1522,#1529));
#1531=FACE_BOUND('',#1530,.T.);
#1532=ADVANCED_FACE('F1777',(#1531),#1513,.F.);
#1533=CARTESIAN_POINT('',(5.08,-1.524,-30.226));
#1534=DIRECTION('',(0.,1.,0.));
#1535=DIRECTION('',(-1.,0.,0.));
#1536=AXIS2_PLACEMENT_3D('',#1533,#1534,#1535);
#1537=PLANE('',#1536);
#1538=CARTESIAN_POINT('',(5.842,-1.524,-30.988));
#1539=DIRECTION('',(0.,1.,0.));
#1540=DIRECTION('',(-1.,0.,0.));
#1541=AXIS2_PLACEMENT_3D('',#1538,#1539,#1540);
#1542=CIRCLE('',#1541,0.381);
#1543=CARTESIAN_POINT('',(5.461,-1.524,-30.988));
#1544=VERTEX_POINT('',#1543);
#1545=CARTESIAN_POINT('',(5.842,-1.524,-31.369));
#1546=VERTEX_POINT('',#1545);
#1547=EDGE_CURVE('E2103',#1544,#1546,#1542,.F.);
#1548=ORIENTED_EDGE('',*,*,#1547,.T.);
#1549=DIRECTION('',(1.,0.,0.));
#1550=VECTOR('',#1549,1.);
#1551=CARTESIAN_POINT('',(5.08,-1.524,-31.369));
#1552=LINE('',#1551,#1550);
#1553=CARTESIAN_POINT('',(21.7012517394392,-1.524,-31.369));
#1554=VERTEX_POINT('',#1553);
#1555=EDGE_CURVE('E2101',#1546,#1554,#1552,.T.);
#1556=ORIENTED_EDGE('',*,*,#1555,.T.);
#1557=DIRECTION('',(0.,0.,-1.));
#1558=VECTOR('',#1557,1.);
#1559=CARTESIAN_POINT('',(21.7012517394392,-1.524,-30.226));
#1560=LINE('',#1559,#1558);
#1561=CARTESIAN_POINT('',(21.7012517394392,-1.524,-30.607));
#1562=VERTEX_POINT('',#1561);
#1563=EDGE_CURVE('E2128',#1554,#1562,#1560,.F.);
#1564=ORIENTED_EDGE('',*,*,#1563,.T.);
#1565=DIRECTION('',(1.,0.,0.));
#1566=VECTOR('',#1565,1.);
#1567=CARTESIAN_POINT('',(5.842,-1.524,-30.607));
#1568=LINE('',#1567,#1566);
#1569=CARTESIAN_POINT('',(5.842,-1.524,-30.607));
#1570=VERTEX_POINT('',#1569);
#1571=EDGE_CURVE('E2108',#1562,#1570,#1568,.F.);
#1572=ORIENTED_EDGE('',*,*,#1571,.T.);
#1573=CARTESIAN_POINT('',(5.842,-1.524,-30.988));
#1574=DIRECTION('',(0.,1.,0.));
#1575=DIRECTION('',(-1.,0.,0.));
#1576=AXIS2_PLACEMENT_3D('',#1573,#1574,#1575);
#1577=CIRCLE('',#1576,0.381);
#1578=EDGE_CURVE('E2106',#1570,#1544,#1577,.F.);
#1579=ORIENTED_EDGE('',*,*,#1578,.T.);
#1580=EDGE_LOOP('',(#1548,#1556,#1564,#1572,#1579));
#1581=FACE_BOUND('',#1580,.T.);
#1582=ADVANCED_FACE('F1773',(#1581),#1537,.F.);
#1583=CARTESIAN_POINT('',(30.7541772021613,-10.9643544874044,-30.226));
#1584=DIRECTION('',(-0.869838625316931,-0.493336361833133,0.));
#1585=DIRECTION('',(0.493336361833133,-0.869838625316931,0.));
#1586=AXIS2_PLACEMENT_3D('',#1583,#1584,#1585);
#1587=PLANE('',#1586);
#1588=DIRECTION('',(0.,0.,-1.));
#1589=VECTOR('',#1588,1.);
#1590=CARTESIAN_POINT('',(27.2247270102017,-4.7413141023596,-30.226));
#1591=LINE('',#1590,#1589);
#1592=CARTESIAN_POINT('',(27.2247270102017,-4.7413141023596,-30.607));
#1593=VERTEX_POINT('',#1592);
#1594=CARTESIAN_POINT('',(27.2247270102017,-4.7413141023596,-31.369));
#1595=VERTEX_POINT('',#1594);
#1596=EDGE_CURVE('E2131',#1593,#1595,#1591,.T.);
#1597=ORIENTED_EDGE('',*,*,#1596,.T.);
#1598=DIRECTION('',(-0.493336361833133,0.869838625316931,0.));
#1599=VECTOR('',#1598,1.);
#1600=CARTESIAN_POINT('',(30.7541772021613,-10.9643544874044,-31.369));
#1601=LINE('',#1600,#1599);
#1602=CARTESIAN_POINT('',(30.7541772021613,-10.9643544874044,-31.369));
#1603=VERTEX_POINT('',#1602);
#1604=EDGE_CURVE('E2011',#1595,#1603,#1601,.F.);
#1605=ORIENTED_EDGE('',*,*,#1604,.T.);
#1606=DIRECTION('',(0.,0.,-1.));
#1607=VECTOR('',#1606,1.);
#1608=CARTESIAN_POINT('',(30.7541772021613,-10.9643544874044,-30.226));
#1609=LINE('',#1608,#1607);
#1610=CARTESIAN_POINT('',(30.7541772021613,-10.9643544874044,-30.607));
#1611=VERTEX_POINT('',#1610);
#1612=EDGE_CURVE('E1117',#1611,#1603,#1609,.T.);
#1613=ORIENTED_EDGE('',*,*,#1612,.F.);
#1614=DIRECTION('',(-0.493336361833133,0.869838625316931,0.));
#1615=VECTOR('',#1614,1.);
#1616=CARTESIAN_POINT('',(30.7541772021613,-10.9643544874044,-30.607));
#1617=LINE('',#1616,#1615);
#1618=EDGE_CURVE('E2013',#1611,#1593,#1617,.T.);
#1619=ORIENTED_EDGE('',*,*,#1618,.T.);
#1620=EDGE_LOOP('',(#1597,#1605,#1613,#1619));
#1621=FACE_BOUND('',#1620,.T.);
#1622=ADVANCED_FACE('F1776',(#1621),#1587,.T.);
#1623=CARTESIAN_POINT('',(36.83,-7.5184,-30.226));
#1624=DIRECTION('',(0.,0.,-1.));
#1625=DIRECTION('',(-1.,0.,0.));
#1626=AXIS2_PLACEMENT_3D('',#1623,#1624,#1625);
#1627=CYLINDRICAL_SURFACE('',#1626,6.98499999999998);
#1628=ORIENTED_EDGE('',*,*,#1612,.T.);
#1629=CARTESIAN_POINT('',(36.83,-7.5184,-31.369));
#1630=DIRECTION('',(0.,0.,1.));
#1631=DIRECTION('',(1.,0.,0.));
#1632=AXIS2_PLACEMENT_3D('',#1629,#1630,#1631);
#1633=CIRCLE('',#1632,6.98499999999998);
#1634=CARTESIAN_POINT('',(42.9058227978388,-10.9643544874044,-31.369));
#1635=VERTEX_POINT('',#1634);
#1636=EDGE_CURVE('E1946',#1603,#1635,#1633,.T.);
#1637=ORIENTED_EDGE('',*,*,#1636,.T.);
#1638=DIRECTION('',(0.,0.,-1.));
#1639=VECTOR('',#1638,1.);
#1640=CARTESIAN_POINT('',(42.9058227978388,-10.9643544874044,-30.226));
#1641=LINE('',#1640,#1639);
#1642=CARTESIAN_POINT('',(42.9058227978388,-10.9643544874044,-30.607));
#1643=VERTEX_POINT('',#1642);
#1644=EDGE_CURVE('E1116',#1643,#1635,#1641,.T.);
#1645=ORIENTED_EDGE('',*,*,#1644,.F.);
#1646=CARTESIAN_POINT('',(36.83,-7.5184,-30.607));
#1647=DIRECTION('',(0.,0.,1.));
#1648=DIRECTION('',(1.,0.,0.));
#1649=AXIS2_PLACEMENT_3D('',#1646,#1647,#1648);
#1650=CIRCLE('',#1649,6.98499999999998);
#1651=EDGE_CURVE('E1948',#1643,#1611,#1650,.F.);
#1652=ORIENTED_EDGE('',*,*,#1651,.T.);
#1653=EDGE_LOOP('',(#1628,#1637,#1645,#1652));
#1654=FACE_BOUND('',#1653,.T.);
#1655=ADVANCED_FACE('F1781',(#1654),#1627,.T.);
#1656=CARTESIAN_POINT('',(42.9058227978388,-10.9643544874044,-30.226));
#1657=DIRECTION('',(-0.86983862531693,0.493336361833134,0.));
#1658=DIRECTION('',(-0.493336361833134,-0.86983862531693,0.));
#1659=AXIS2_PLACEMENT_3D('',#1656,#1657,#1658);
#1660=PLANE('',#1659);
#1661=ORIENTED_EDGE('',*,*,#1644,.T.);
#1662=DIRECTION('',(0.493336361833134,0.86983862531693,0.));
#1663=VECTOR('',#1662,1.);
#1664=CARTESIAN_POINT('',(42.9058227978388,-10.9643544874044,-31.369));
#1665=LINE('',#1664,#1663);
#1666=CARTESIAN_POINT('',(46.4352729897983,-4.7413141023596,-31.369));
#1667=VERTEX_POINT('',#1666);
#1668=EDGE_CURVE('E1921',#1635,#1667,#1665,.T.);
#1669=ORIENTED_EDGE('',*,*,#1668,.T.);
#1670=DIRECTION('',(0.,0.,-1.));
#1671=VECTOR('',#1670,1.);
#1672=CARTESIAN_POINT('',(46.4352729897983,-4.7413141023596,-30.226));
#1673=LINE('',#1672,#1671);
#1674=CARTESIAN_POINT('',(46.4352729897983,-4.7413141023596,-30.607));
#1675=VERTEX_POINT('',#1674);
#1676=EDGE_CURVE('E1911',#1667,#1675,#1673,.F.);
#1677=ORIENTED_EDGE('',*,*,#1676,.T.);
#1678=DIRECTION('',(0.493336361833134,0.86983862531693,0.));
#1679=VECTOR('',#1678,1.);
#1680=CARTESIAN_POINT('',(42.9058227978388,-10.9643544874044,-30.607));
#1681=LINE('',#1680,#1679);
#1682=EDGE_CURVE('E1918',#1675,#1643,#1681,.F.);
#1683=ORIENTED_EDGE('',*,*,#1682,.T.);
#1684=EDGE_LOOP('',(#1661,#1669,#1677,#1683));
#1685=FACE_BOUND('',#1684,.T.);
#1686=ADVANCED_FACE('F1785',(#1685),#1660,.F.);
#1687=CARTESIAN_POINT('',(48.26,-1.524,-30.226));
#1688=DIRECTION('',(0.,1.,0.));
#1689=DIRECTION('',(-1.,0.,0.));
#1690=AXIS2_PLACEMENT_3D('',#1687,#1688,#1689);
#1691=PLANE('',#1690);
#1692=DIRECTION('',(0.,0.,-1.));
#1693=VECTOR('',#1692,1.);
#1694=CARTESIAN_POINT('',(51.9587482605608,-1.524,-31.75));
#1695=LINE('',#1694,#1693);
#1696=CARTESIAN_POINT('',(51.9587482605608,-1.524,-30.607));
#1697=VERTEX_POINT('',#1696);
#1698=CARTESIAN_POINT('',(51.9587482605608,-1.524,-31.369));
#1699=VERTEX_POINT('',#1698);
#1700=EDGE_CURVE('E1914',#1697,#1699,#1695,.T.);
#1701=ORIENTED_EDGE('',*,*,#1700,.T.);
#1702=DIRECTION('',(1.,0.,0.));
#1703=VECTOR('',#1702,1.);
#1704=CARTESIAN_POINT('',(48.26,-1.524,-31.369));
#1705=LINE('',#1704,#1703);
#1706=CARTESIAN_POINT('',(110.236,-1.524,-31.369));
#1707=VERTEX_POINT('',#1706);
#1708=EDGE_CURVE('E1954',#1699,#1707,#1705,.T.);
#1709=ORIENTED_EDGE('',*,*,#1708,.T.);
#1710=CARTESIAN_POINT('',(110.236,-1.524,-30.988));
#1711=DIRECTION('',(0.,1.,0.));
#1712=DIRECTION('',(-1.,0.,0.));
#1713=AXIS2_PLACEMENT_3D('',#1710,#1711,#1712);
#1714=CIRCLE('',#1713,0.381);
#1715=CARTESIAN_POINT('',(110.617,-1.524,-30.988));
#1716=VERTEX_POINT('',#1715);
#1717=EDGE_CURVE('E1956',#1707,#1716,#1714,.F.);
#1718=ORIENTED_EDGE('',*,*,#1717,.T.);
#1719=CARTESIAN_POINT('',(110.236,-1.524,-30.988));
#1720=DIRECTION('',(0.,1.,0.));
#1721=DIRECTION('',(-1.,0.,0.));
#1722=AXIS2_PLACEMENT_3D('',#1719,#1720,#1721);
#1723=CIRCLE('',#1722,0.381);
#1724=CARTESIAN_POINT('',(110.236,-1.524,-30.607));
#1725=VERTEX_POINT('',#1724);
#1726=EDGE_CURVE('E1958',#1716,#1725,#1723,.F.);
#1727=ORIENTED_EDGE('',*,*,#1726,.T.);
#1728=DIRECTION('',(1.,0.,0.));
#1729=VECTOR('',#1728,1.);
#1730=CARTESIAN_POINT('',(51.9587482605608,-1.524,-30.607));
#1731=LINE('',#1730,#1729);
#1732=EDGE_CURVE('E1960',#1725,#1697,#1731,.F.);
#1733=ORIENTED_EDGE('',*,*,#1732,.T.);
#1734=EDGE_LOOP('',(#1701,#1709,#1718,#1727,#1733));
#1735=FACE_BOUND('',#1734,.T.);
#1736=ADVANCED_FACE('F1771',(#1735),#1691,.F.);
#1737=CARTESIAN_POINT('',(36.83,-7.5184,-30.226));
#1738=DIRECTION('',(0.,0.,1.));
#1739=DIRECTION('',(-1.,0.,0.));
#1740=AXIS2_PLACEMENT_3D('',#1737,#1738,#1739);
#1741=PLANE('',#1740);
#1742=DIRECTION('',(0.,-1.,0.));
#1743=VECTOR('',#1742,1.);
#1744=CARTESIAN_POINT('',(110.236,-7.5184,-30.226));
#1745=LINE('',#1744,#1743);
#1746=CARTESIAN_POINT('',(110.236,-1.143,-30.226));
#1747=VERTEX_POINT('',#1746);
#1748=CARTESIAN_POINT('',(110.236,-0.381,-30.226));
#1749=VERTEX_POINT('',#1748);
#1750=EDGE_CURVE('E2149',#1747,#1749,#1745,.F.);
#1751=ORIENTED_EDGE('',*,*,#1750,.T.);
#1752=DIRECTION('',(1.,0.,0.));
#1753=VECTOR('',#1752,1.);
#1754=CARTESIAN_POINT('',(36.83,-0.381,-30.226));
#1755=LINE('',#1754,#1753);
#1756=CARTESIAN_POINT('',(5.842,-0.381,-30.226));
#1757=VERTEX_POINT('',#1756);
#1758=EDGE_CURVE('E2027',#1749,#1757,#1755,.F.);
#1759=ORIENTED_EDGE('',*,*,#1758,.T.);
#1760=DIRECTION('',(0.,-1.,0.));
#1761=VECTOR('',#1760,1.);
#1762=CARTESIAN_POINT('',(5.842,-1.524,-30.226));
#1763=LINE('',#1762,#1761);
#1764=CARTESIAN_POINT('',(5.842,-1.143,-30.226));
#1765=VERTEX_POINT('',#1764);
#1766=EDGE_CURVE('E2146',#1757,#1765,#1763,.T.);
#1767=ORIENTED_EDGE('',*,*,#1766,.T.);
#1768=DIRECTION('',(1.,0.,0.));
#1769=VECTOR('',#1768,1.);
#1770=CARTESIAN_POINT('',(21.7012517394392,-1.143,-30.226));
#1771=LINE('',#1770,#1769);
#1772=CARTESIAN_POINT('',(21.7012517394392,-1.143,-30.226));
#1773=VERTEX_POINT('',#1772);
#1774=EDGE_CURVE('E2030',#1765,#1773,#1771,.T.);
#1775=ORIENTED_EDGE('',*,*,#1774,.T.);
#1776=CARTESIAN_POINT('',(21.7012517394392,-7.874,-30.226));
#1777=DIRECTION('',(0.,0.,1.));
#1778=DIRECTION('',(1.,0.,0.));
#1779=AXIS2_PLACEMENT_3D('',#1776,#1777,#1778);
#1780=CIRCLE('',#1779,6.731);
#1781=CARTESIAN_POINT('',(27.5561355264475,-4.55335294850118,-30.226));
#1782=VERTEX_POINT('',#1781);
#1783=EDGE_CURVE('E2032',#1773,#1782,#1780,.F.);
#1784=ORIENTED_EDGE('',*,*,#1783,.T.);
#1785=DIRECTION('',(-0.493336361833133,0.869838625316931,0.));
#1786=VECTOR('',#1785,1.);
#1787=CARTESIAN_POINT('',(31.085585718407,-10.776393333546,-30.226));
#1788=LINE('',#1787,#1786);
#1789=CARTESIAN_POINT('',(31.085585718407,-10.776393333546,-30.226));
#1790=VERTEX_POINT('',#1789);
#1791=EDGE_CURVE('E2034',#1782,#1790,#1788,.F.);
#1792=ORIENTED_EDGE('',*,*,#1791,.T.);
#1793=CARTESIAN_POINT('',(36.83,-7.5184,-30.226));
#1794=DIRECTION('',(0.,0.,1.));
#1795=DIRECTION('',(1.,0.,0.));
#1796=AXIS2_PLACEMENT_3D('',#1793,#1794,#1795);
#1797=CIRCLE('',#1796,6.60399999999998);
#1798=CARTESIAN_POINT('',(42.574414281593,-10.776393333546,-30.226));
#1799=VERTEX_POINT('',#1798);
#1800=EDGE_CURVE('E2036',#1790,#1799,#1797,.T.);
#1801=ORIENTED_EDGE('',*,*,#1800,.T.);
#1802=DIRECTION('',(0.493336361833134,0.86983862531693,0.));
#1803=VECTOR('',#1802,1.);
#1804=CARTESIAN_POINT('',(46.1038644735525,-4.55335294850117,-30.226));
#1805=LINE('',#1804,#1803);
#1806=CARTESIAN_POINT('',(46.1038644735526,-4.55335294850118,-30.226));
#1807=VERTEX_POINT('',#1806);
#1808=EDGE_CURVE('E2038',#1799,#1807,#1805,.T.);
#1809=ORIENTED_EDGE('',*,*,#1808,.T.);
#1810=CARTESIAN_POINT('',(51.9587482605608,-7.874,-30.226));
#1811=DIRECTION('',(0.,0.,1.));
#1812=DIRECTION('',(1.,0.,0.));
#1813=AXIS2_PLACEMENT_3D('',#1810,#1811,#1812);
#1814=CIRCLE('',#1813,6.731);
#1815=CARTESIAN_POINT('',(51.9587482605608,-1.143,-30.226));
#1816=VERTEX_POINT('',#1815);
#1817=EDGE_CURVE('E1925',#1807,#1816,#1814,.F.);
#1818=ORIENTED_EDGE('',*,*,#1817,.T.);
#1819=DIRECTION('',(1.,0.,0.));
#1820=VECTOR('',#1819,1.);
#1821=CARTESIAN_POINT('',(110.236,-1.143,-30.226));
#1822=LINE('',#1821,#1820);
#1823=EDGE_CURVE('E2040',#1816,#1747,#1822,.T.);
#1824=ORIENTED_EDGE('',*,*,#1823,.T.);
#1825=EDGE_LOOP('',(#1751,#1759,#1767,#1775,#1784,#1792,#1801,#1809,#1818,#1824));
#1826=FACE_BOUND('',#1825,.T.);
#1827=ADVANCED_FACE('F1767',(#1826),#1741,.T.);
#1828=CARTESIAN_POINT('',(36.83,-7.5184,-31.75));
#1829=DIRECTION('',(0.,0.,1.));
#1830=DIRECTION('',(-1.,0.,0.));
#1831=AXIS2_PLACEMENT_3D('',#1828,#1829,#1830);
#1832=PLANE('',#1831);
#1833=CARTESIAN_POINT('',(36.83,-7.5184,-31.75));
#1834=DIRECTION('',(0.,0.,1.));
#1835=DIRECTION('',(1.,0.,0.));
#1836=AXIS2_PLACEMENT_3D('',#1833,#1834,#1835);
#1837=CIRCLE('',#1836,4.064);
#1838=CARTESIAN_POINT('',(40.894,-7.5184,-31.75));
#1839=VERTEX_POINT('',#1838);
#1840=EDGE_CURVE('E1104',#1839,#1839,#1837,.T.);
#1841=ORIENTED_EDGE('',*,*,#1840,.T.);
#1842=EDGE_LOOP('',(#1841));
#1843=FACE_BOUND('',#1842,.T.);
#1844=CARTESIAN_POINT('',(21.7012517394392,-7.874,-31.75));
#1845=DIRECTION('',(0.,0.,1.));
#1846=DIRECTION('',(1.,0.,0.));
#1847=AXIS2_PLACEMENT_3D('',#1844,#1845,#1846);
#1848=CIRCLE('',#1847,6.731);
#1849=CARTESIAN_POINT('',(27.5561355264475,-4.55335294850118,-31.75));
#1850=VERTEX_POINT('',#1849);
#1851=CARTESIAN_POINT('',(21.7012517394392,-1.143,-31.75));
#1852=VERTEX_POINT('',#1851);
#1853=EDGE_CURVE('E2045',#1850,#1852,#1848,.T.);
#1854=ORIENTED_EDGE('',*,*,#1853,.T.);
#1855=DIRECTION('',(1.,0.,0.));
#1856=VECTOR('',#1855,1.);
#1857=CARTESIAN_POINT('',(36.83,-1.143,-31.75));
#1858=LINE('',#1857,#1856);
#1859=CARTESIAN_POINT('',(5.842,-1.143,-31.75));
#1860=VERTEX_POINT('',#1859);
#1861=EDGE_CURVE('E2043',#1852,#1860,#1858,.F.);
#1862=ORIENTED_EDGE('',*,*,#1861,.T.);
#1863=DIRECTION('',(0.,-1.,0.));
#1864=VECTOR('',#1863,1.);
#1865=CARTESIAN_POINT('',(5.842,-7.51839999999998,-31.75));
#1866=LINE('',#1865,#1864);
#1867=CARTESIAN_POINT('',(5.842,-0.381,-31.75));
#1868=VERTEX_POINT('',#1867);
#1869=EDGE_CURVE('E2140',#1860,#1868,#1866,.F.);
#1870=ORIENTED_EDGE('',*,*,#1869,.T.);
#1871=DIRECTION('',(1.,0.,0.));
#1872=VECTOR('',#1871,1.);
#1873=CARTESIAN_POINT('',(110.236,-0.381,-31.75));
#1874=LINE('',#1873,#1872);
#1875=CARTESIAN_POINT('',(110.236,-0.381,-31.75));
#1876=VERTEX_POINT('',#1875);
#1877=EDGE_CURVE('E2057',#1868,#1876,#1874,.T.);
#1878=ORIENTED_EDGE('',*,*,#1877,.T.);
#1879=DIRECTION('',(0.,-1.,0.));
#1880=VECTOR('',#1879,1.);
#1881=CARTESIAN_POINT('',(110.236,-1.524,-31.75));
#1882=LINE('',#1881,#1880);
#1883=CARTESIAN_POINT('',(110.236,-1.143,-31.75));
#1884=VERTEX_POINT('',#1883);
#1885=EDGE_CURVE('E2143',#1876,#1884,#1882,.T.);
#1886=ORIENTED_EDGE('',*,*,#1885,.T.);
#1887=DIRECTION('',(1.,0.,0.));
#1888=VECTOR('',#1887,1.);
#1889=CARTESIAN_POINT('',(36.83,-1.143,-31.75));
#1890=LINE('',#1889,#1888);
#1891=CARTESIAN_POINT('',(51.9587482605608,-1.143,-31.75));
#1892=VERTEX_POINT('',#1891);
#1893=EDGE_CURVE('E2051',#1884,#1892,#1890,.F.);
#1894=ORIENTED_EDGE('',*,*,#1893,.T.);
#1895=CARTESIAN_POINT('',(51.9587482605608,-7.874,-31.75));
#1896=DIRECTION('',(0.,0.,1.));
#1897=DIRECTION('',(1.,0.,0.));
#1898=AXIS2_PLACEMENT_3D('',#1895,#1896,#1897);
#1899=CIRCLE('',#1898,6.731);
#1900=CARTESIAN_POINT('',(46.1038644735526,-4.55335294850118,-31.75));
#1901=VERTEX_POINT('',#1900);
#1902=EDGE_CURVE('E2055',#1892,#1901,#1899,.T.);
#1903=ORIENTED_EDGE('',*,*,#1902,.T.);
#1904=DIRECTION('',(0.493336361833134,0.86983862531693,0.));
#1905=VECTOR('',#1904,1.);
#1906=CARTESIAN_POINT('',(42.574414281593,-10.776393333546,-31.75));
#1907=LINE('',#1906,#1905);
#1908=CARTESIAN_POINT('',(42.574414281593,-10.776393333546,-31.75));
#1909=VERTEX_POINT('',#1908);
#1910=EDGE_CURVE('E2053',#1901,#1909,#1907,.F.);
#1911=ORIENTED_EDGE('',*,*,#1910,.T.);
#1912=CARTESIAN_POINT('',(36.83,-7.5184,-31.75));
#1913=DIRECTION('',(0.,0.,1.));
#1914=DIRECTION('',(1.,0.,0.));
#1915=AXIS2_PLACEMENT_3D('',#1912,#1913,#1914);
#1916=CIRCLE('',#1915,6.60399999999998);
#1917=CARTESIAN_POINT('',(31.085585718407,-10.776393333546,-31.75));
#1918=VERTEX_POINT('',#1917);
#1919=EDGE_CURVE('E2049',#1909,#1918,#1916,.F.);
#1920=ORIENTED_EDGE('',*,*,#1919,.T.);
#1921=DIRECTION('',(-0.493336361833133,0.869838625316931,0.));
#1922=VECTOR('',#1921,1.);
#1923=CARTESIAN_POINT('',(27.5561355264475,-4.55335294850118,-31.75));
#1924=LINE('',#1923,#1922);
#1925=EDGE_CURVE('E2047',#1918,#1850,#1924,.T.);
#1926=ORIENTED_EDGE('',*,*,#1925,.T.);
#1927=EDGE_LOOP('',(#1854,#1862,#1870,#1878,#1886,#1894,#1903,#1911,#1920,#1926));
#1928=FACE_BOUND('',#1927,.T.);
#1929=ADVANCED_FACE('F1763',(#1843,#1928),#1832,.F.);
#1930=CARTESIAN_POINT('',(5.842,0.,-30.988));
#1931=DIRECTION('',(0.,-1.,0.));
#1932=DIRECTION('',(1.,0.,0.));
#1933=AXIS2_PLACEMENT_3D('',#1930,#1931,#1932);
#1934=CYLINDRICAL_SURFACE('',#1933,0.762);
#1935=ORIENTED_EDGE('',*,*,#1869,.F.);
#1936=CARTESIAN_POINT('',(5.842,-1.143,-30.988));
#1937=DIRECTION('',(0.,1.,0.));
#1938=DIRECTION('',(-1.,0.,0.));
#1939=AXIS2_PLACEMENT_3D('',#1936,#1937,#1938);
#1940=CIRCLE('',#1939,0.762);
#1941=CARTESIAN_POINT('',(5.08,-1.143,-30.988));
#1942=VERTEX_POINT('',#1941);
#1943=EDGE_CURVE('E2096',#1860,#1942,#1940,.T.);
#1944=ORIENTED_EDGE('',*,*,#1943,.T.);
#1945=DIRECTION('',(0.,-1.,0.));
#1946=VECTOR('',#1945,1.);
#1947=CARTESIAN_POINT('',(5.08,0.,-30.988));
#1948=LINE('',#1947,#1946);
#1949=CARTESIAN_POINT('',(5.08,-0.381,-30.988));
#1950=VERTEX_POINT('',#1949);
#1951=EDGE_CURVE('E1113',#1950,#1942,#1948,.T.);
#1952=ORIENTED_EDGE('',*,*,#1951,.F.);
#1953=CARTESIAN_POINT('',(5.842,-0.381,-30.988));
#1954=DIRECTION('',(0.,1.,0.));
#1955=DIRECTION('',(0.,0.,1.));
#1956=AXIS2_PLACEMENT_3D('',#1953,#1954,#1955);
#1957=CIRCLE('',#1956,0.762);
#1958=EDGE_CURVE('E2099',#1950,#1868,#1957,.F.);
#1959=ORIENTED_EDGE('',*,*,#1958,.T.);
#1960=EDGE_LOOP('',(#1935,#1944,#1952,#1959));
#1961=FACE_BOUND('',#1960,.T.);
#1962=ADVANCED_FACE('F1759',(#1961),#1934,.T.);
#1963=CARTESIAN_POINT('',(5.842,-7.51839999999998,-30.988));
#1964=DIRECTION('',(0.,1.,0.));
#1965=DIRECTION('',(-1.,0.,0.));
#1966=AXIS2_PLACEMENT_3D('',#1963,#1964,#1965);
#1967=CYLINDRICAL_SURFACE('',#1966,0.762);
#1968=ORIENTED_EDGE('',*,*,#1951,.T.);
#1969=CARTESIAN_POINT('',(5.842,-1.143,-30.988));
#1970=DIRECTION('',(0.,1.,0.));
#1971=DIRECTION('',(-1.,0.,0.));
#1972=AXIS2_PLACEMENT_3D('',#1969,#1970,#1971);
#1973=CIRCLE('',#1972,0.762);
#1974=EDGE_CURVE('E2092',#1942,#1765,#1973,.T.);
#1975=ORIENTED_EDGE('',*,*,#1974,.T.);
#1976=ORIENTED_EDGE('',*,*,#1766,.F.);
#1977=CARTESIAN_POINT('',(5.842,-0.381,-30.988));
#1978=DIRECTION('',(0.,1.,0.));
#1979=DIRECTION('',(0.,0.,1.));
#1980=AXIS2_PLACEMENT_3D('',#1977,#1978,#1979);
#1981=CIRCLE('',#1980,0.762);
#1982=EDGE_CURVE('E2094',#1757,#1950,#1981,.F.);
#1983=ORIENTED_EDGE('',*,*,#1982,.T.);
#1984=EDGE_LOOP('',(#1968,#1975,#1976,#1983));
#1985=FACE_BOUND('',#1984,.T.);
#1986=ADVANCED_FACE('F1755',(#1985),#1967,.T.);
#1987=CARTESIAN_POINT('',(110.236,0.,-30.988));
#1988=DIRECTION('',(0.,-1.,0.));
#1989=DIRECTION('',(0.,0.,-1.));
#1990=AXIS2_PLACEMENT_3D('',#1987,#1988,#1989);
#1991=CYLINDRICAL_SURFACE('',#1990,0.762);
#1992=ORIENTED_EDGE('',*,*,#1750,.F.);
#1993=CARTESIAN_POINT('',(110.236,-1.143,-30.988));
#1994=DIRECTION('',(0.,1.,0.));
#1995=DIRECTION('',(-1.,0.,0.));
#1996=AXIS2_PLACEMENT_3D('',#1993,#1994,#1995);
#1997=CIRCLE('',#1996,0.762);
#1998=CARTESIAN_POINT('',(110.998,-1.143,-30.988));
#1999=VERTEX_POINT('',#1998);
#2000=EDGE_CURVE('E1942',#1747,#1999,#1997,.T.);
#2001=ORIENTED_EDGE('',*,*,#2000,.T.);
#2002=DIRECTION('',(0.,-1.,0.));
#2003=VECTOR('',#2002,1.);
#2004=CARTESIAN_POINT('',(110.998,0.,-30.988));
#2005=LINE('',#2004,#2003);
#2006=CARTESIAN_POINT('',(110.998,-0.381,-30.988));
#2007=VERTEX_POINT('',#2006);
#2008=EDGE_CURVE('E1110',#2007,#1999,#2005,.T.);
#2009=ORIENTED_EDGE('',*,*,#2008,.F.);
#2010=CARTESIAN_POINT('',(110.236,-0.381,-30.988));
#2011=DIRECTION('',(0.,1.,0.));
#2012=DIRECTION('',(0.,0.,1.));
#2013=AXIS2_PLACEMENT_3D('',#2010,#2011,#2012);
#2014=CIRCLE('',#2013,0.762);
#2015=EDGE_CURVE('E1944',#2007,#1749,#2014,.F.);
#2016=ORIENTED_EDGE('',*,*,#2015,.T.);
#2017=EDGE_LOOP('',(#1992,#2001,#2009,#2016));
#2018=FACE_BOUND('',#2017,.T.);
#2019=ADVANCED_FACE('F1751',(#2018),#1991,.T.);
#2020=CARTESIAN_POINT('',(110.236,-7.5184,-30.988));
#2021=DIRECTION('',(0.,1.,0.));
#2022=DIRECTION('',(0.,0.,1.));
#2023=AXIS2_PLACEMENT_3D('',#2020,#2021,#2022);
#2024=CYLINDRICAL_SURFACE('',#2023,0.762);
#2025=ORIENTED_EDGE('',*,*,#2008,.T.);
#2026=CARTESIAN_POINT('',(110.236,-1.143,-30.988));
#2027=DIRECTION('',(0.,1.,0.));
#2028=DIRECTION('',(-1.,0.,0.));
#2029=AXIS2_PLACEMENT_3D('',#2026,#2027,#2028);
#2030=CIRCLE('',#2029,0.762);
#2031=EDGE_CURVE('E1950',#1999,#1884,#2030,.T.);
#2032=ORIENTED_EDGE('',*,*,#2031,.T.);
#2033=ORIENTED_EDGE('',*,*,#1885,.F.);
#2034=CARTESIAN_POINT('',(110.236,-0.381,-30.988));
#2035=DIRECTION('',(0.,1.,0.));
#2036=DIRECTION('',(0.,0.,1.));
#2037=AXIS2_PLACEMENT_3D('',#2034,#2035,#2036);
#2038=CIRCLE('',#2037,0.762);
#2039=EDGE_CURVE('E1952',#1876,#2007,#2038,.F.);
#2040=ORIENTED_EDGE('',*,*,#2039,.T.);
#2041=EDGE_LOOP('',(#2025,#2032,#2033,#2040));
#2042=FACE_BOUND('',#2041,.T.);
#2043=ADVANCED_FACE('F1747',(#2042),#2024,.T.);
#2044=CARTESIAN_POINT('',(36.83,-7.5184,-33.02));
#2045=DIRECTION('',(0.,0.,1.));
#2046=DIRECTION('',(1.,0.,0.));
#2047=AXIS2_PLACEMENT_3D('',#2044,#2045,#2046);
#2048=CYLINDRICAL_SURFACE('',#2047,4.064);
#2049=CARTESIAN_POINT('',(36.83,-7.5184,-33.02));
#2050=DIRECTION('',(0.,0.,1.));
#2051=DIRECTION('',(1.,0.,0.));
#2052=AXIS2_PLACEMENT_3D('',#2049,#2050,#2051);
#2053=CIRCLE('',#2052,4.064);
#2054=CARTESIAN_POINT('',(40.894,-7.5184,-33.02));
#2055=VERTEX_POINT('',#2054);
#2056=EDGE_CURVE('E1107',#2055,#2055,#2053,.T.);
#2057=ORIENTED_EDGE('',*,*,#2056,.T.);
#2058=EDGE_LOOP('',(#2057));
#2059=FACE_BOUND('',#2058,.T.);
#2060=ORIENTED_EDGE('',*,*,#1840,.F.);
#2061=EDGE_LOOP('',(#2060));
#2062=FACE_BOUND('',#2061,.T.);
#2063=ADVANCED_FACE('F1743',(#2059,#2062),#2048,.T.);
#2064=CARTESIAN_POINT('',(36.83,-7.5184,-33.02));
#2065=DIRECTION('',(0.,0.,-1.));
#2066=DIRECTION('',(1.,0.,0.));
#2067=AXIS2_PLACEMENT_3D('',#2064,#2065,#2066);
#2068=PLANE('',#2067);
#2069=CARTESIAN_POINT('',(36.83,-7.5184,-33.02));
#2070=DIRECTION('',(0.,0.,-1.));
#2071=DIRECTION('',(-1.,0.,0.));
#2072=AXIS2_PLACEMENT_3D('',#2069,#2070,#2071);
#2073=CIRCLE('',#2072,3.55600000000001);
#2074=CARTESIAN_POINT('',(33.274,-7.5184,-33.02));
#2075=VERTEX_POINT('',#2074);
#2076=EDGE_CURVE('E2137',#2075,#2075,#2073,.T.);
#2077=ORIENTED_EDGE('',*,*,#2076,.F.);
#2078=EDGE_LOOP('',(#2077));
#2079=FACE_BOUND('',#2078,.T.);
#2080=ORIENTED_EDGE('',*,*,#2056,.F.);
#2081=EDGE_LOOP('',(#2080));
#2082=FACE_BOUND('',#2081,.T.);
#2083=ADVANCED_FACE('F1739',(#2079,#2082),#2068,.T.);
#2084=CARTESIAN_POINT('',(36.83,-7.5184,-38.1));
#2085=DIRECTION('',(0.,0.,1.));
#2086=DIRECTION('',(1.,0.,0.));
#2087=AXIS2_PLACEMENT_3D('',#2084,#2085,#2086);
#2088=CYLINDRICAL_SURFACE('',#2087,3.55600000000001);
#2089=CARTESIAN_POINT('',(36.83,-7.5184,-38.1));
#2090=DIRECTION('',(0.,0.,1.));
#2091=DIRECTION('',(1.,0.,0.));
#2092=AXIS2_PLACEMENT_3D('',#2089,#2090,#2091);
#2093=CIRCLE('',#2092,3.55600000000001);
#2094=CARTESIAN_POINT('',(40.386,-7.5184,-38.1));
#2095=VERTEX_POINT('',#2094);
#2096=CARTESIAN_POINT('',(33.274,-7.5184,-38.1));
#2097=VERTEX_POINT('',#2096);
#2098=EDGE_CURVE('E1101',#2095,#2097,#2093,.T.);
#2099=ORIENTED_EDGE('',*,*,#2098,.T.);
#2100=CARTESIAN_POINT('',(36.83,-7.5184,-38.1));
#2101=DIRECTION('',(0.,0.581238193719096,0.813733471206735));
#2102=DIRECTION('',(0.,-0.813733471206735,0.581238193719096));
#2103=AXIS2_PLACEMENT_3D('',#2100,#2101,#2102);
#2104=ELLIPSE('',#2103,4.36998123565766,3.55600000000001);
#2105=EDGE_CURVE('E1091',#2095,#2097,#2104,.F.);
#2106=ORIENTED_EDGE('',*,*,#2105,.F.);
#2107=EDGE_LOOP('',(#2099,#2106));
#2108=FACE_BOUND('',#2107,.T.);
#2109=ORIENTED_EDGE('',*,*,#2076,.T.);
#2110=EDGE_LOOP('',(#2109));
#2111=FACE_BOUND('',#2110,.T.);
#2112=ADVANCED_FACE('F1735',(#2108,#2111),#2088,.T.);
#2113=CARTESIAN_POINT('',(36.83,-7.5184,-38.1));
#2114=DIRECTION('',(0.,0.,-1.));
#2115=DIRECTION('',(1.,0.,0.));
#2116=AXIS2_PLACEMENT_3D('',#2113,#2114,#2115);
#2117=PLANE('',#2116);
#2118=DIRECTION('',(1.,0.,0.));
#2119=VECTOR('',#2118,1.);
#2120=CARTESIAN_POINT('',(36.83,-7.5184,-38.1));
#2121=LINE('',#2120,#2119);
#2122=EDGE_CURVE('E2134',#2097,#2095,#2121,.T.);
#2123=ORIENTED_EDGE('',*,*,#2122,.F.);
#2124=ORIENTED_EDGE('',*,*,#2098,.F.);
#2125=EDGE_LOOP('',(#2123,#2124));
#2126=FACE_BOUND('',#2125,.T.);
#2127=ADVANCED_FACE('F1731',(#2126),#2117,.T.);
#2128=CARTESIAN_POINT('',(0.,-7.5184,-38.1));
#2129=DIRECTION('',(0.,0.581238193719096,0.813733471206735));
#2130=DIRECTION('',(0.,-0.813733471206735,0.581238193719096));
#2131=AXIS2_PLACEMENT_3D('',#2128,#2129,#2130);
#2132=PLANE('',#2131);
#2133=ORIENTED_EDGE('',*,*,#2105,.T.);
#2134=ORIENTED_EDGE('',*,*,#2122,.T.);
#2135=EDGE_LOOP('',(#2133,#2134));
#2136=FACE_BOUND('',#2135,.T.);
#2137=ADVANCED_FACE('F1727',(#2136),#2132,.F.);
#2138=CARTESIAN_POINT('',(21.7012517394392,-7.874,-30.226));
#2139=DIRECTION('',(0.,0.,-1.));
#2140=DIRECTION('',(-1.,0.,0.));
#2141=AXIS2_PLACEMENT_3D('',#2138,#2139,#2140);
#2142=CYLINDRICAL_SURFACE('',#2141,6.35);
#2143=ORIENTED_EDGE('',*,*,#1563,.F.);
#2144=CARTESIAN_POINT('',(21.7012517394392,-7.874,-31.369));
#2145=DIRECTION('',(0.,0.,1.));
#2146=DIRECTION('',(1.,0.,0.));
#2147=AXIS2_PLACEMENT_3D('',#2144,#2145,#2146);
#2148=CIRCLE('',#2147,6.35);
#2149=EDGE_CURVE('E2019',#1554,#1595,#2148,.F.);
#2150=ORIENTED_EDGE('',*,*,#2149,.T.);
#2151=ORIENTED_EDGE('',*,*,#1596,.F.);
#2152=CARTESIAN_POINT('',(21.7012517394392,-7.874,-30.607));
#2153=DIRECTION('',(0.,0.,1.));
#2154=DIRECTION('',(1.,0.,0.));
#2155=AXIS2_PLACEMENT_3D('',#2152,#2153,#2154);
#2156=CIRCLE('',#2155,6.35);
#2157=EDGE_CURVE('E2021',#1593,#1562,#2156,.T.);
#2158=ORIENTED_EDGE('',*,*,#2157,.T.);
#2159=EDGE_LOOP('',(#2143,#2150,#2151,#2158));
#2160=FACE_BOUND('',#2159,.T.);
#2161=ADVANCED_FACE('F1723',(#2160),#2142,.F.);
#2162=CARTESIAN_POINT('',(51.9587482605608,-7.874,-30.226));
#2163=DIRECTION('',(0.,0.,1.));
#2164=DIRECTION('',(1.,0.,0.));
#2165=AXIS2_PLACEMENT_3D('',#2162,#2163,#2164);
#2166=CYLINDRICAL_SURFACE('',#2165,6.35);
#2167=ORIENTED_EDGE('',*,*,#1676,.F.);
#2168=CARTESIAN_POINT('',(51.9587482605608,-7.874,-31.369));
#2169=DIRECTION('',(0.,0.,1.));
#2170=DIRECTION('',(1.,0.,0.));
#2171=AXIS2_PLACEMENT_3D('',#2168,#2169,#2170);
#2172=CIRCLE('',#2171,6.35);
#2173=EDGE_CURVE('E11',#1667,#1699,#2172,.F.);
#2174=ORIENTED_EDGE('',*,*,#2173,.T.);
#2175=ORIENTED_EDGE('',*,*,#1700,.F.);
#2176=CARTESIAN_POINT('',(51.9587482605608,-7.874,-30.607));
#2177=DIRECTION('',(0.,0.,1.));
#2178=DIRECTION('',(1.,0.,0.));
#2179=AXIS2_PLACEMENT_3D('',#2176,#2177,#2178);
#2180=CIRCLE('',#2179,6.35);
#2181=EDGE_CURVE('E36',#1697,#1675,#2180,.T.);
#2182=ORIENTED_EDGE('',*,*,#2181,.T.);
#2183=EDGE_LOOP('',(#2167,#2174,#2175,#2182));
#2184=FACE_BOUND('',#2183,.T.);
#2185=ADVANCED_FACE('F1716',(#2184),#2166,.F.);
#2186=CARTESIAN_POINT('',(118.872,-30.0127921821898,-30.988));
#2187=DIRECTION('',(0.,1.,0.));
#2188=DIRECTION('',(0.,0.,1.));
#2189=AXIS2_PLACEMENT_3D('',#2186,#2187,#2188);
#2190=CYLINDRICAL_SURFACE('',#2189,0.761999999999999);
#2191=DIRECTION('',(0.,1.,0.));
#2192=VECTOR('',#2191,1.);
#2193=CARTESIAN_POINT('',(119.634,-30.0127921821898,-30.988));
#2194=LINE('',#2193,#2192);
#2195=CARTESIAN_POINT('',(119.634,-1.524,-30.988));
#2196=VERTEX_POINT('',#2195);
#2197=EDGE_CURVE('E1071',#2196,#449,#2194,.T.);
#2198=ORIENTED_EDGE('',*,*,#2197,.F.);
#2199=CARTESIAN_POINT('',(118.872,-1.524,-30.988));
#2200=DIRECTION('',(0.,-1.,0.));
#2201=DIRECTION('',(1.,0.,0.));
#2202=AXIS2_PLACEMENT_3D('',#2199,#2200,#2201);
#2203=CIRCLE('',#2202,0.761999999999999);
#2204=CARTESIAN_POINT('',(118.11,-1.524,-30.988));
#2205=VERTEX_POINT('',#2204);
#2206=EDGE_CURVE('E1066',#2196,#2205,#2203,.F.);
#2207=ORIENTED_EDGE('',*,*,#2206,.T.);
#2208=DIRECTION('',(0.,1.,0.));
#2209=VECTOR('',#2208,1.);
#2210=CARTESIAN_POINT('',(118.11,-30.0127921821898,-30.988));
#2211=LINE('',#2210,#2209);
#2212=EDGE_CURVE('E1088',#2205,#460,#2211,.T.);
#2213=ORIENTED_EDGE('',*,*,#2212,.T.);
#2214=ORIENTED_EDGE('',*,*,#461,.F.);
#2215=EDGE_LOOP('',(#2198,#2207,#2213,#2214));
#2216=FACE_BOUND('',#2215,.T.);
#2217=ADVANCED_FACE('F1712',(#2216),#2190,.T.);
#2218=CARTESIAN_POINT('',(119.634,-30.0127921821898,-30.988));
#2219=DIRECTION('',(-1.,0.,0.));
#2220=DIRECTION('',(0.,0.,1.));
#2221=AXIS2_PLACEMENT_3D('',#2218,#2219,#2220);
#2222=PLANE('',#2221);
#2223=DIRECTION('',(0.,0.,1.));
#2224=VECTOR('',#2223,1.);
#2225=CARTESIAN_POINT('',(119.634,-1.524,-30.988));
#2226=LINE('',#2225,#2224);
#2227=CARTESIAN_POINT('',(119.634,-1.524,-4.064));
#2228=VERTEX_POINT('',#2227);
#2229=EDGE_CURVE('E1074',#2196,#2228,#2226,.T.);
#2230=ORIENTED_EDGE('',*,*,#2229,.F.);
#2231=ORIENTED_EDGE('',*,*,#2197,.T.);
#2232=ORIENTED_EDGE('',*,*,#452,.T.);
#2233=DIRECTION('',(0.,1.,0.));
#2234=VECTOR('',#2233,1.);
#2235=CARTESIAN_POINT('',(119.634,-30.0127921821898,-4.064));
#2236=LINE('',#2235,#2234);
#2237=EDGE_CURVE('E1082',#2228,#451,#2236,.T.);
#2238=ORIENTED_EDGE('',*,*,#2237,.F.);
#2239=EDGE_LOOP('',(#2230,#2231,#2232,#2238));
#2240=FACE_BOUND('',#2239,.T.);
#2241=ADVANCED_FACE('F1708',(#2240),#2222,.F.);
#2242=CARTESIAN_POINT('',(118.872,-30.0127921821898,-4.064));
#2243=DIRECTION('',(0.,1.,0.));
#2244=DIRECTION('',(0.,0.,1.));
#2245=AXIS2_PLACEMENT_3D('',#2242,#2243,#2244);
#2246=CYLINDRICAL_SURFACE('',#2245,0.761999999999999);
#2247=DIRECTION('',(0.,1.,0.));
#2248=VECTOR('',#2247,1.);
#2249=CARTESIAN_POINT('',(118.11,-30.0127921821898,-4.064));
#2250=LINE('',#2249,#2248);
#2251=CARTESIAN_POINT('',(118.11,-1.524,-4.064));
#2252=VERTEX_POINT('',#2251);
#2253=EDGE_CURVE('E1079',#2252,#468,#2250,.T.);
#2254=ORIENTED_EDGE('',*,*,#2253,.F.);
#2255=CARTESIAN_POINT('',(118.872,-1.524,-4.064));
#2256=DIRECTION('',(0.,-1.,0.));
#2257=DIRECTION('',(1.,0.,0.));
#2258=AXIS2_PLACEMENT_3D('',#2255,#2256,#2257);
#2259=CIRCLE('',#2258,0.761999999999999);
#2260=EDGE_CURVE('E1070',#2252,#2228,#2259,.F.);
#2261=ORIENTED_EDGE('',*,*,#2260,.T.);
#2262=ORIENTED_EDGE('',*,*,#2237,.T.);
#2263=ORIENTED_EDGE('',*,*,#476,.F.);
#2264=EDGE_LOOP('',(#2254,#2261,#2262,#2263));
#2265=FACE_BOUND('',#2264,.T.);
#2266=ADVANCED_FACE('F1704',(#2265),#2246,.T.);
#2267=CARTESIAN_POINT('',(118.11,-30.0127921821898,-4.064));
#2268=DIRECTION('',(1.,0.,0.));
#2269=DIRECTION('',(0.,0.,-1.));
#2270=AXIS2_PLACEMENT_3D('',#2267,#2268,#2269);
#2271=PLANE('',#2270);
#2272=DIRECTION('',(0.,0.,-1.));
#2273=VECTOR('',#2272,1.);
#2274=CARTESIAN_POINT('',(118.11,-1.524,-4.064));
#2275=LINE('',#2274,#2273);
#2276=EDGE_CURVE('E1085',#2252,#2205,#2275,.T.);
#2277=ORIENTED_EDGE('',*,*,#2276,.F.);
#2278=ORIENTED_EDGE('',*,*,#2253,.T.);
#2279=ORIENTED_EDGE('',*,*,#469,.T.);
#2280=ORIENTED_EDGE('',*,*,#2212,.F.);
#2281=EDGE_LOOP('',(#2277,#2278,#2279,#2280));
#2282=FACE_BOUND('',#2281,.T.);
#2283=ADVANCED_FACE('F1701',(#2282),#2271,.F.);
#2284=CARTESIAN_POINT('',(48.26,-1.524,-4.826));
#2285=DIRECTION('',(0.,-1.,0.));
#2286=DIRECTION('',(1.,0.,0.));
#2287=AXIS2_PLACEMENT_3D('',#2284,#2285,#2286);
#2288=PLANE('',#2287);
#2289=ORIENTED_EDGE('',*,*,#2206,.F.);
#2290=ORIENTED_EDGE('',*,*,#2229,.T.);
#2291=ORIENTED_EDGE('',*,*,#2260,.F.);
#2292=ORIENTED_EDGE('',*,*,#2276,.T.);
#2293=EDGE_LOOP('',(#2289,#2290,#2291,#2292));
#2294=FACE_BOUND('',#2293,.T.);
#2295=ADVANCED_FACE('F1699',(#2294),#2288,.T.);
#2296=CARTESIAN_POINT('',(48.26,-1.524,-4.826));
#2297=DIRECTION('',(0.,-1.,0.));
#2298=DIRECTION('',(1.,0.,0.));
#2299=AXIS2_PLACEMENT_3D('',#2296,#2297,#2298);
#2300=PLANE('',#2299);
#2301=CARTESIAN_POINT('',(14.605,-1.524,-17.526));
#2302=DIRECTION('',(0.,-1.,0.));
#2303=DIRECTION('',(1.,0.,0.));
#2304=AXIS2_PLACEMENT_3D('',#2301,#2302,#2303);
#2305=CIRCLE('',#2304,8.382);
#2306=CARTESIAN_POINT('',(22.987,-1.524,-17.526));
#2307=VERTEX_POINT('',#2306);
#2308=EDGE_CURVE('E1901',#2307,#2307,#2305,.F.);
#2309=ORIENTED_EDGE('',*,*,#2308,.T.);
#2310=EDGE_LOOP('',(#2309));
#2311=FACE_BOUND('',#2310,.T.);
#2312=CARTESIAN_POINT('',(14.605,-1.524,-17.526));
#2313=DIRECTION('',(0.,-1.,0.));
#2314=DIRECTION('',(1.,0.,0.));
#2315=AXIS2_PLACEMENT_3D('',#2312,#2313,#2314);
#2316=CIRCLE('',#2315,8.89);
#2317=CARTESIAN_POINT('',(23.495,-1.524,-17.526));
#2318=VERTEX_POINT('',#2317);
#2319=EDGE_CURVE('E1898',#2318,#2318,#2316,.T.);
#2320=ORIENTED_EDGE('',*,*,#2319,.T.);
#2321=EDGE_LOOP('',(#2320));
#2322=FACE_BOUND('',#2321,.T.);
#2323=ADVANCED_FACE('F1695',(#2311,#2322),#2300,.T.);
#2324=CARTESIAN_POINT('',(14.605,-27.7463478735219,-17.526));
#2325=DIRECTION('',(0.,1.,0.));
#2326=DIRECTION('',(0.,0.,1.));
#2327=AXIS2_PLACEMENT_3D('',#2324,#2325,#2326);
#2328=CYLINDRICAL_SURFACE('',#2327,9.271);
#2329=CARTESIAN_POINT('',(14.605,-0.381,-17.526));
#2330=DIRECTION('',(0.,1.,0.));
#2331=DIRECTION('',(0.,0.,1.));
#2332=AXIS2_PLACEMENT_3D('',#2329,#2330,#2331);
#2333=CIRCLE('',#2332,9.271);
#2334=CARTESIAN_POINT('',(14.605,-0.381,-8.25500000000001));
#2335=VERTEX_POINT('',#2334);
#2336=EDGE_CURVE('E1886',#2335,#2335,#2333,.F.);
#2337=ORIENTED_EDGE('',*,*,#2336,.T.);
#2338=EDGE_LOOP('',(#2337));
#2339=FACE_BOUND('',#2338,.T.);
#2340=CARTESIAN_POINT('',(14.605,-1.143,-17.526));
#2341=DIRECTION('',(0.,-1.,0.));
#2342=DIRECTION('',(1.,0.,0.));
#2343=AXIS2_PLACEMENT_3D('',#2340,#2341,#2342);
#2344=CIRCLE('',#2343,9.271);
#2345=CARTESIAN_POINT('',(23.876,-1.143,-17.526));
#2346=VERTEX_POINT('',#2345);
#2347=EDGE_CURVE('E1892',#2346,#2346,#2344,.F.);
#2348=ORIENTED_EDGE('',*,*,#2347,.T.);
#2349=EDGE_LOOP('',(#2348));
#2350=FACE_BOUND('',#2349,.T.);
#2351=ADVANCED_FACE('F1691',(#2339,#2350),#2328,.T.);
#2352=CARTESIAN_POINT('',(14.605,-27.7463478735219,-17.526));
#2353=DIRECTION('',(0.,1.,0.));
#2354=DIRECTION('',(0.,0.,1.));
#2355=AXIS2_PLACEMENT_3D('',#2352,#2353,#2354);
#2356=CYLINDRICAL_SURFACE('',#2355,8.001);
#2357=CARTESIAN_POINT('',(14.605,-0.381,-17.526));
#2358=DIRECTION('',(0.,1.,0.));
#2359=DIRECTION('',(0.,0.,1.));
#2360=AXIS2_PLACEMENT_3D('',#2357,#2358,#2359);
#2361=CIRCLE('',#2360,8.001);
#2362=CARTESIAN_POINT('',(14.605,-0.381,-9.52500000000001));
#2363=VERTEX_POINT('',#2362);
#2364=EDGE_CURVE('E1889',#2363,#2363,#2361,.T.);
#2365=ORIENTED_EDGE('',*,*,#2364,.T.);
#2366=EDGE_LOOP('',(#2365));
#2367=FACE_BOUND('',#2366,.T.);
#2368=CARTESIAN_POINT('',(14.605,-1.143,-17.526));
#2369=DIRECTION('',(0.,-1.,0.));
#2370=DIRECTION('',(1.,0.,0.));
#2371=AXIS2_PLACEMENT_3D('',#2368,#2369,#2370);
#2372=CIRCLE('',#2371,8.001);
#2373=CARTESIAN_POINT('',(22.606,-1.143,-17.526));
#2374=VERTEX_POINT('',#2373);
#2375=EDGE_CURVE('E1885',#2374,#2374,#2372,.T.);
#2376=ORIENTED_EDGE('',*,*,#2375,.T.);
#2377=EDGE_LOOP('',(#2376));
#2378=FACE_BOUND('',#2377,.T.);
#2379=ADVANCED_FACE('F1688',(#2367,#2378),#2356,.F.);
#2380=CARTESIAN_POINT('',(14.605,0.,-17.526));
#2381=DIRECTION('',(0.,1.,0.));
#2382=DIRECTION('',(0.,0.,1.));
#2383=AXIS2_PLACEMENT_3D('',#2380,#2381,#2382);
#2384=CIRCLE('',#2383,7.62);
#2385=CARTESIAN_POINT('',(14.605,0.,-9.90600000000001));
#2386=VERTEX_POINT('',#2385);
#2387=EDGE_CURVE('E1883',#2386,#2386,#2384,.F.);
#2388=ORIENTED_EDGE('',*,*,#2387,.T.);
#2389=EDGE_LOOP('',(#2388));
#2390=FACE_BOUND('',#2389,.T.);
#2391=ADVANCED_FACE('F1419',(#2390),#324,.F.);
#2392=CARTESIAN_POINT('',(110.236,-1.143,-4.064));
#2393=DIRECTION('',(0.,-1.,0.));
#2394=DIRECTION('',(1.,0.,0.));
#2395=AXIS2_PLACEMENT_3D('',#2392,#2393,#2394);
#2396=DEGENERATE_TOROIDAL_SURFACE('',#2395,0.381,0.381,.T.);
#2397=CARTESIAN_POINT('',(110.236,-1.143,-4.445));
#2398=DIRECTION('',(-1.,0.,0.));
#2399=DIRECTION('',(0.,0.,1.));
#2400=AXIS2_PLACEMENT_3D('',#2397,#2398,#2399);
#2401=CIRCLE('',#2400,0.381);
#2402=EDGE_CURVE('E1060',#1303,#1091,#2401,.T.);
#2403=ORIENTED_EDGE('',*,*,#2402,.F.);
#2404=ORIENTED_EDGE('',*,*,#1426,.F.);
#2405=CARTESIAN_POINT('',(110.617,-1.143,-4.064));
#2406=DIRECTION('',(0.,0.,1.));
#2407=DIRECTION('',(1.,0.,0.));
#2408=AXIS2_PLACEMENT_3D('',#2405,#2406,#2407);
#2409=CIRCLE('',#2408,0.381);
#2410=EDGE_CURVE('E1063',#1065,#1416,#2409,.T.);
#2411=ORIENTED_EDGE('',*,*,#2410,.F.);
#2412=ORIENTED_EDGE('',*,*,#1099,.F.);
#2413=EDGE_LOOP('',(#2403,#2404,#2411,#2412));
#2414=FACE_BOUND('',#2413,.T.);
#2415=ADVANCED_FACE('F1683',(#2414),#2396,.T.);
#2416=CARTESIAN_POINT('',(110.236,-1.143,-4.064));
#2417=DIRECTION('',(0.,-1.,0.));
#2418=DIRECTION('',(1.,0.,0.));
#2419=AXIS2_PLACEMENT_3D('',#2416,#2417,#2418);
#2420=DEGENERATE_TOROIDAL_SURFACE('',#2419,0.381,0.381,.T.);
#2421=ORIENTED_EDGE('',*,*,#2410,.T.);
#2422=ORIENTED_EDGE('',*,*,#1450,.F.);
#2423=CARTESIAN_POINT('',(110.236,-1.143,-3.683));
#2424=DIRECTION('',(-1.,0.,0.));
#2425=DIRECTION('',(0.,0.,1.));
#2426=AXIS2_PLACEMENT_3D('',#2423,#2424,#2425);
#2427=CIRCLE('',#2426,0.381);
#2428=EDGE_CURVE('E1057',#1067,#633,#2427,.T.);
#2429=ORIENTED_EDGE('',*,*,#2428,.F.);
#2430=ORIENTED_EDGE('',*,*,#1068,.F.);
#2431=EDGE_LOOP('',(#2421,#2422,#2429,#2430));
#2432=FACE_BOUND('',#2431,.T.);
#2433=ADVANCED_FACE('F1679',(#2432),#2420,.T.);
#2434=CARTESIAN_POINT('',(48.26,-1.143,-4.445));
#2435=DIRECTION('',(1.,0.,0.));
#2436=DIRECTION('',(0.,1.,0.));
#2437=AXIS2_PLACEMENT_3D('',#2434,#2435,#2436);
#2438=CYLINDRICAL_SURFACE('',#2437,0.381);
#2439=ORIENTED_EDGE('',*,*,#2402,.T.);
#2440=ORIENTED_EDGE('',*,*,#1092,.F.);
#2441=CARTESIAN_POINT('',(51.9587482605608,-1.143,-4.445));
#2442=DIRECTION('',(-1.,0.,0.));
#2443=DIRECTION('',(0.,0.,1.));
#2444=AXIS2_PLACEMENT_3D('',#2441,#2442,#2443);
#2445=CIRCLE('',#2444,0.381);
#2446=EDGE_CURVE('E1054',#1311,#1083,#2445,.T.);
#2447=ORIENTED_EDGE('',*,*,#2446,.F.);
#2448=ORIENTED_EDGE('',*,*,#1312,.F.);
#2449=EDGE_LOOP('',(#2439,#2440,#2447,#2448));
#2450=FACE_BOUND('',#2449,.T.);
#2451=ADVANCED_FACE('F1675',(#2450),#2438,.T.);
#2452=CARTESIAN_POINT('',(36.83,-1.143,-3.683));
#2453=DIRECTION('',(-1.,0.,0.));
#2454=DIRECTION('',(0.,-1.,0.));
#2455=AXIS2_PLACEMENT_3D('',#2452,#2453,#2454);
#2456=CYLINDRICAL_SURFACE('',#2455,0.381);
#2457=ORIENTED_EDGE('',*,*,#2428,.T.);
#2458=ORIENTED_EDGE('',*,*,#709,.F.);
#2459=CARTESIAN_POINT('',(51.9587482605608,-1.143,-3.683));
#2460=DIRECTION('',(-1.,0.,0.));
#2461=DIRECTION('',(0.,0.,1.));
#2462=AXIS2_PLACEMENT_3D('',#2459,#2460,#2461);
#2463=CIRCLE('',#2462,0.381);
#2464=EDGE_CURVE('E1051',#1075,#702,#2463,.T.);
#2465=ORIENTED_EDGE('',*,*,#2464,.F.);
#2466=ORIENTED_EDGE('',*,*,#1076,.F.);
#2467=EDGE_LOOP('',(#2457,#2458,#2465,#2466));
#2468=FACE_BOUND('',#2467,.T.);
#2469=ADVANCED_FACE('F1671',(#2468),#2456,.T.);
#2470=CARTESIAN_POINT('',(51.9587482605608,-7.874,-4.445));
#2471=DIRECTION('',(0.,0.,-1.));
#2472=DIRECTION('',(-1.,0.,0.));
#2473=AXIS2_PLACEMENT_3D('',#2470,#2471,#2472);
#2474=TOROIDAL_SURFACE('',#2473,6.731,0.381);
#2475=ORIENTED_EDGE('',*,*,#2446,.T.);
#2476=ORIENTED_EDGE('',*,*,#1528,.F.);
#2477=CARTESIAN_POINT('',(46.1038644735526,-4.55335294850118,-4.445));
#2478=DIRECTION('',(-0.493336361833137,-0.869838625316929,0.));
#2479=DIRECTION('',(0.869838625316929,-0.493336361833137,0.));
#2480=AXIS2_PLACEMENT_3D('',#2477,#2478,#2479);
#2481=CIRCLE('',#2480,0.381);
#2482=EDGE_CURVE('E1048',#1320,#1114,#2481,.T.);
#2483=ORIENTED_EDGE('',*,*,#2482,.F.);
#2484=ORIENTED_EDGE('',*,*,#1321,.F.);
#2485=EDGE_LOOP('',(#2475,#2476,#2483,#2484));
#2486=FACE_BOUND('',#2485,.T.);
#2487=ADVANCED_FACE('F1667',(#2486),#2474,.T.);
#2488=CARTESIAN_POINT('',(51.9587482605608,-7.874,-3.683));
#2489=DIRECTION('',(0.,0.,-1.));
#2490=DIRECTION('',(-1.,0.,0.));
#2491=AXIS2_PLACEMENT_3D('',#2488,#2489,#2490);
#2492=TOROIDAL_SURFACE('',#2491,6.731,0.381);
#2493=ORIENTED_EDGE('',*,*,#2464,.T.);
#2494=ORIENTED_EDGE('',*,*,#703,.F.);
#2495=CARTESIAN_POINT('',(46.1038644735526,-4.55335294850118,-3.683));
#2496=DIRECTION('',(-0.493336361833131,-0.869838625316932,0.));
#2497=DIRECTION('',(0.869838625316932,-0.493336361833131,0.));
#2498=AXIS2_PLACEMENT_3D('',#2495,#2496,#2497);
#2499=CIRCLE('',#2498,0.381);
#2500=EDGE_CURVE('E1045',#1116,#693,#2499,.T.);
#2501=ORIENTED_EDGE('',*,*,#2500,.F.);
#2502=ORIENTED_EDGE('',*,*,#1520,.F.);
#2503=EDGE_LOOP('',(#2493,#2494,#2501,#2502));
#2504=FACE_BOUND('',#2503,.T.);
#2505=ADVANCED_FACE('F1663',(#2504),#2492,.T.);
#2506=CARTESIAN_POINT('',(42.574414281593,-10.776393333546,-4.445));
#2507=DIRECTION('',(0.493336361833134,0.86983862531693,0.));
#2508=DIRECTION('',(-0.86983862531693,0.493336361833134,0.));
#2509=AXIS2_PLACEMENT_3D('',#2506,#2507,#2508);
#2510=CYLINDRICAL_SURFACE('',#2509,0.381);
#2511=ORIENTED_EDGE('',*,*,#2482,.T.);
#2512=ORIENTED_EDGE('',*,*,#1139,.F.);
#2513=CARTESIAN_POINT('',(42.574414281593,-10.776393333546,-4.445));
#2514=DIRECTION('',(-0.493336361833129,-0.869838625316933,0.));
#2515=DIRECTION('',(0.869838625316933,-0.493336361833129,0.));
#2516=AXIS2_PLACEMENT_3D('',#2513,#2514,#2515);
#2517=CIRCLE('',#2516,0.381);
#2518=EDGE_CURVE('E1042',#1328,#1132,#2517,.T.);
#2519=ORIENTED_EDGE('',*,*,#2518,.F.);
#2520=ORIENTED_EDGE('',*,*,#1329,.F.);
#2521=EDGE_LOOP('',(#2511,#2512,#2519,#2520));
#2522=FACE_BOUND('',#2521,.T.);
#2523=ADVANCED_FACE('F1659',(#2522),#2510,.T.);
#2524=CARTESIAN_POINT('',(42.574414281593,-10.776393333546,-3.683));
#2525=DIRECTION('',(-0.493336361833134,-0.86983862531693,0.));
#2526=DIRECTION('',(0.86983862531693,-0.493336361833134,0.));
#2527=AXIS2_PLACEMENT_3D('',#2524,#2525,#2526);
#2528=CYLINDRICAL_SURFACE('',#2527,0.381);
#2529=ORIENTED_EDGE('',*,*,#2500,.T.);
#2530=ORIENTED_EDGE('',*,*,#694,.F.);
#2531=CARTESIAN_POINT('',(42.574414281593,-10.776393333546,-3.683));
#2532=DIRECTION('',(-0.493336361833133,-0.869838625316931,0.));
#2533=DIRECTION('',(0.869838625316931,-0.493336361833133,0.));
#2534=AXIS2_PLACEMENT_3D('',#2531,#2532,#2533);
#2535=CIRCLE('',#2534,0.381);
#2536=EDGE_CURVE('E1039',#1124,#685,#2535,.T.);
#2537=ORIENTED_EDGE('',*,*,#2536,.F.);
#2538=ORIENTED_EDGE('',*,*,#1125,.F.);
#2539=EDGE_LOOP('',(#2529,#2530,#2537,#2538));
#2540=FACE_BOUND('',#2539,.T.);
#2541=ADVANCED_FACE('F1655',(#2540),#2528,.T.);
#2542=CARTESIAN_POINT('',(36.83,-7.5184,-4.445));
#2543=DIRECTION('',(0.,0.,-1.));
#2544=DIRECTION('',(-1.,0.,0.));
#2545=AXIS2_PLACEMENT_3D('',#2542,#2543,#2544);
#2546=TOROIDAL_SURFACE('',#2545,6.60399999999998,0.381);
#2547=ORIENTED_EDGE('',*,*,#2518,.T.);
#2548=ORIENTED_EDGE('',*,*,#1172,.F.);
#2549=CARTESIAN_POINT('',(31.085585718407,-10.776393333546,-4.445));
#2550=DIRECTION('',(-0.493336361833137,0.869838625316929,0.));
#2551=DIRECTION('',(-0.869838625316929,-0.493336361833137,0.));
#2552=AXIS2_PLACEMENT_3D('',#2549,#2550,#2551);
#2553=CIRCLE('',#2552,0.381);
#2554=EDGE_CURVE('E1036',#1337,#1164,#2553,.T.);
#2555=ORIENTED_EDGE('',*,*,#2554,.F.);
#2556=ORIENTED_EDGE('',*,*,#1338,.F.);
#2557=EDGE_LOOP('',(#2547,#2548,#2555,#2556));
#2558=FACE_BOUND('',#2557,.T.);
#2559=ADVANCED_FACE('F1651',(#2558),#2546,.T.);
#2560=CARTESIAN_POINT('',(36.83,-7.5184,-3.683));
#2561=DIRECTION('',(0.,0.,-1.));
#2562=DIRECTION('',(-1.,0.,0.));
#2563=AXIS2_PLACEMENT_3D('',#2560,#2561,#2562);
#2564=TOROIDAL_SURFACE('',#2563,6.60399999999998,0.381);
#2565=ORIENTED_EDGE('',*,*,#2536,.T.);
#2566=ORIENTED_EDGE('',*,*,#686,.F.);
#2567=CARTESIAN_POINT('',(31.085585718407,-10.776393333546,-3.683));
#2568=DIRECTION('',(-0.493336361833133,0.869838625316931,0.));
#2569=DIRECTION('',(-0.869838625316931,-0.493336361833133,0.));
#2570=AXIS2_PLACEMENT_3D('',#2567,#2568,#2569);
#2571=CIRCLE('',#2570,0.381);
#2572=EDGE_CURVE('E1033',#1156,#676,#2571,.T.);
#2573=ORIENTED_EDGE('',*,*,#2572,.F.);
#2574=ORIENTED_EDGE('',*,*,#1157,.F.);
#2575=EDGE_LOOP('',(#2565,#2566,#2573,#2574));
#2576=FACE_BOUND('',#2575,.T.);
#2577=ADVANCED_FACE('F1647',(#2576),#2564,.T.);
#2578=CARTESIAN_POINT('',(31.085585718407,-10.776393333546,-4.445));
#2579=DIRECTION('',(0.493336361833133,-0.869838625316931,0.));
#2580=DIRECTION('',(0.869838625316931,0.493336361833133,0.));
#2581=AXIS2_PLACEMENT_3D('',#2578,#2579,#2580);
#2582=CYLINDRICAL_SURFACE('',#2581,0.381);
#2583=ORIENTED_EDGE('',*,*,#2554,.T.);
#2584=ORIENTED_EDGE('',*,*,#1203,.F.);
#2585=CARTESIAN_POINT('',(27.5561355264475,-4.55335294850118,-4.445));
#2586=DIRECTION('',(-0.493336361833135,0.86983862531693,0.));
#2587=DIRECTION('',(-0.86983862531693,-0.493336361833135,0.));
#2588=AXIS2_PLACEMENT_3D('',#2585,#2586,#2587);
#2589=CIRCLE('',#2588,0.381);
#2590=EDGE_CURVE('E1030',#1269,#1196,#2589,.T.);
#2591=ORIENTED_EDGE('',*,*,#2590,.F.);
#2592=ORIENTED_EDGE('',*,*,#1344,.F.);
#2593=EDGE_LOOP('',(#2583,#2584,#2591,#2592));
#2594=FACE_BOUND('',#2593,.T.);
#2595=ADVANCED_FACE('F1643',(#2594),#2582,.T.);
#2596=CARTESIAN_POINT('',(31.085585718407,-10.776393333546,-3.683));
#2597=DIRECTION('',(-0.493336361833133,0.869838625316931,0.));
#2598=DIRECTION('',(-0.869838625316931,-0.493336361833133,0.));
#2599=AXIS2_PLACEMENT_3D('',#2596,#2597,#2598);
#2600=CYLINDRICAL_SURFACE('',#2599,0.381);
#2601=ORIENTED_EDGE('',*,*,#2572,.T.);
#2602=ORIENTED_EDGE('',*,*,#677,.F.);
#2603=CARTESIAN_POINT('',(27.5561355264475,-4.55335294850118,-3.683));
#2604=DIRECTION('',(-0.493336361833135,0.86983862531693,0.));
#2605=DIRECTION('',(-0.86983862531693,-0.493336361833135,0.));
#2606=AXIS2_PLACEMENT_3D('',#2603,#2604,#2605);
#2607=CIRCLE('',#2606,0.381);
#2608=EDGE_CURVE('E1027',#1188,#668,#2607,.T.);
#2609=ORIENTED_EDGE('',*,*,#2608,.F.);
#2610=ORIENTED_EDGE('',*,*,#1189,.F.);
#2611=EDGE_LOOP('',(#2601,#2602,#2609,#2610));
#2612=FACE_BOUND('',#2611,.T.);
#2613=ADVANCED_FACE('F1639',(#2612),#2600,.T.);
#2614=CARTESIAN_POINT('',(21.7012517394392,-7.874,-4.445));
#2615=DIRECTION('',(0.,0.,-1.));
#2616=DIRECTION('',(-1.,0.,0.));
#2617=AXIS2_PLACEMENT_3D('',#2614,#2615,#2616);
#2618=TOROIDAL_SURFACE('',#2617,6.731,0.381);
#2619=ORIENTED_EDGE('',*,*,#2590,.T.);
#2620=ORIENTED_EDGE('',*,*,#1504,.F.);
#2621=CARTESIAN_POINT('',(21.7012517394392,-1.143,-4.445));
#2622=DIRECTION('',(-1.,0.,0.));
#2623=DIRECTION('',(0.,0.,1.));
#2624=AXIS2_PLACEMENT_3D('',#2621,#2622,#2623);
#2625=CIRCLE('',#2624,0.381);
#2626=EDGE_CURVE('E1024',#1271,#1218,#2625,.T.);
#2627=ORIENTED_EDGE('',*,*,#2626,.F.);
#2628=ORIENTED_EDGE('',*,*,#1272,.F.);
#2629=EDGE_LOOP('',(#2619,#2620,#2627,#2628));
#2630=FACE_BOUND('',#2629,.T.);
#2631=ADVANCED_FACE('F1635',(#2630),#2618,.T.);
#2632=CARTESIAN_POINT('',(21.7012517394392,-7.874,-3.683));
#2633=DIRECTION('',(0.,0.,-1.));
#2634=DIRECTION('',(-1.,0.,0.));
#2635=AXIS2_PLACEMENT_3D('',#2632,#2633,#2634);
#2636=TOROIDAL_SURFACE('',#2635,6.731,0.381);
#2637=ORIENTED_EDGE('',*,*,#2608,.T.);
#2638=ORIENTED_EDGE('',*,*,#669,.F.);
#2639=CARTESIAN_POINT('',(21.7012517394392,-1.143,-3.683));
#2640=DIRECTION('',(-1.,0.,0.));
#2641=DIRECTION('',(0.,0.,1.));
#2642=AXIS2_PLACEMENT_3D('',#2639,#2640,#2641);
#2643=CIRCLE('',#2642,0.381);
#2644=EDGE_CURVE('E1021',#1220,#659,#2643,.T.);
#2645=ORIENTED_EDGE('',*,*,#2644,.F.);
#2646=ORIENTED_EDGE('',*,*,#1496,.F.);
#2647=EDGE_LOOP('',(#2637,#2638,#2645,#2646));
#2648=FACE_BOUND('',#2647,.T.);
#2649=ADVANCED_FACE('F1631',(#2648),#2636,.T.);
#2650=CARTESIAN_POINT('',(5.08,-1.143,-4.445));
#2651=DIRECTION('',(1.,0.,0.));
#2652=DIRECTION('',(0.,1.,0.));
#2653=AXIS2_PLACEMENT_3D('',#2650,#2651,#2652);
#2654=CYLINDRICAL_SURFACE('',#2653,0.381);
#2655=ORIENTED_EDGE('',*,*,#2626,.T.);
#2656=ORIENTED_EDGE('',*,*,#1253,.F.);
#2657=CARTESIAN_POINT('',(5.842,-1.143,-4.445));
#2658=DIRECTION('',(-1.,0.,0.));
#2659=DIRECTION('',(0.,0.,1.));
#2660=AXIS2_PLACEMENT_3D('',#2657,#2658,#2659);
#2661=CIRCLE('',#2660,0.381);
#2662=EDGE_CURVE('E1018',#1279,#1246,#2661,.T.);
#2663=ORIENTED_EDGE('',*,*,#2662,.F.);
#2664=ORIENTED_EDGE('',*,*,#1280,.F.);
#2665=EDGE_LOOP('',(#2655,#2656,#2663,#2664));
#2666=FACE_BOUND('',#2665,.T.);
#2667=ADVANCED_FACE('F1627',(#2666),#2654,.T.);
#2668=CARTESIAN_POINT('',(36.83,-1.143,-3.683));
#2669=DIRECTION('',(-1.,0.,0.));
#2670=DIRECTION('',(0.,-1.,0.));
#2671=AXIS2_PLACEMENT_3D('',#2668,#2669,#2670);
#2672=CYLINDRICAL_SURFACE('',#2671,0.381);
#2673=ORIENTED_EDGE('',*,*,#2644,.T.);
#2674=ORIENTED_EDGE('',*,*,#660,.F.);
#2675=CARTESIAN_POINT('',(5.842,-1.143,-3.683));
#2676=DIRECTION('',(-1.,0.,0.));
#2677=DIRECTION('',(0.,0.,1.));
#2678=AXIS2_PLACEMENT_3D('',#2675,#2676,#2677);
#2679=CIRCLE('',#2678,0.381);
#2680=EDGE_CURVE('E1016',#1228,#651,#2679,.T.);
#2681=ORIENTED_EDGE('',*,*,#2680,.F.);
#2682=ORIENTED_EDGE('',*,*,#1229,.F.);
#2683=EDGE_LOOP('',(#2673,#2674,#2681,#2682));
#2684=FACE_BOUND('',#2683,.T.);
#2685=ADVANCED_FACE('F1623',(#2684),#2672,.T.);
#2686=CARTESIAN_POINT('',(5.842,-1.143,-4.064));
#2687=DIRECTION('',(0.,-1.,0.));
#2688=DIRECTION('',(1.,0.,0.));
#2689=AXIS2_PLACEMENT_3D('',#2686,#2687,#2688);
#2690=DEGENERATE_TOROIDAL_SURFACE('',#2689,0.381,0.381,.T.);
#2691=ORIENTED_EDGE('',*,*,#2662,.T.);
#2692=ORIENTED_EDGE('',*,*,#1247,.F.);
#2693=CARTESIAN_POINT('',(5.461,-1.143,-4.064));
#2694=DIRECTION('',(0.,0.,1.));
#2695=DIRECTION('',(1.,0.,0.));
#2696=AXIS2_PLACEMENT_3D('',#2693,#2694,#2695);
#2697=CIRCLE('',#2696,0.381);
#2698=EDGE_CURVE('E1014',#1359,#1237,#2697,.T.);
#2699=ORIENTED_EDGE('',*,*,#2698,.F.);
#2700=ORIENTED_EDGE('',*,*,#1393,.F.);
#2701=EDGE_LOOP('',(#2691,#2692,#2699,#2700));
#2702=FACE_BOUND('',#2701,.T.);
#2703=ADVANCED_FACE('F1619',(#2702),#2690,.T.);
#2704=CARTESIAN_POINT('',(5.842,-1.143,-4.064));
#2705=DIRECTION('',(0.,-1.,0.));
#2706=DIRECTION('',(1.,0.,0.));
#2707=AXIS2_PLACEMENT_3D('',#2704,#2705,#2706);
#2708=DEGENERATE_TOROIDAL_SURFACE('',#2707,0.381,0.381,.T.);
#2709=ORIENTED_EDGE('',*,*,#2680,.T.);
#2710=ORIENTED_EDGE('',*,*,#1369,.F.);
#2711=ORIENTED_EDGE('',*,*,#2698,.T.);
#2712=ORIENTED_EDGE('',*,*,#1238,.F.);
#2713=EDGE_LOOP('',(#2709,#2710,#2711,#2712));
#2714=FACE_BOUND('',#2713,.T.);
#2715=ADVANCED_FACE('F1615',(#2714),#2708,.T.);
#2716=CARTESIAN_POINT('',(110.236,-1.143,-30.988));
#2717=DIRECTION('',(0.,1.,0.));
#2718=DIRECTION('',(-1.,0.,0.));
#2719=AXIS2_PLACEMENT_3D('',#2716,#2717,#2718);
#2720=DEGENERATE_TOROIDAL_SURFACE('',#2719,0.381,0.381,.T.);
#2721=CARTESIAN_POINT('',(110.617,-1.143,-30.988));
#2722=DIRECTION('',(0.,0.,-1.));
#2723=DIRECTION('',(0.,1.,0.));
#2724=AXIS2_PLACEMENT_3D('',#2721,#2722,#2723);
#2725=CIRCLE('',#2724,0.381);
#2726=EDGE_CURVE('E1008',#1999,#1716,#2725,.T.);
#2727=ORIENTED_EDGE('',*,*,#2726,.F.);
#2728=ORIENTED_EDGE('',*,*,#2000,.F.);
#2729=CARTESIAN_POINT('',(110.236,-1.143,-30.607));
#2730=DIRECTION('',(-1.,0.,0.));
#2731=DIRECTION('',(0.,0.,1.));
#2732=AXIS2_PLACEMENT_3D('',#2729,#2730,#2731);
#2733=CIRCLE('',#2732,0.381);
#2734=EDGE_CURVE('E1011',#1725,#1747,#2733,.T.);
#2735=ORIENTED_EDGE('',*,*,#2734,.F.);
#2736=ORIENTED_EDGE('',*,*,#1726,.F.);
#2737=EDGE_LOOP('',(#2727,#2728,#2735,#2736));
#2738=FACE_BOUND('',#2737,.T.);
#2739=ADVANCED_FACE('F1611',(#2738),#2720,.T.);
#2740=CARTESIAN_POINT('',(36.83,-1.143,-30.607));
#2741=DIRECTION('',(-1.,0.,0.));
#2742=DIRECTION('',(0.,-1.,0.));
#2743=AXIS2_PLACEMENT_3D('',#2740,#2741,#2742);
#2744=CYLINDRICAL_SURFACE('',#2743,0.381);
#2745=ORIENTED_EDGE('',*,*,#2734,.T.);
#2746=ORIENTED_EDGE('',*,*,#1823,.F.);
#2747=CARTESIAN_POINT('',(51.9587482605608,-1.143,-30.607));
#2748=DIRECTION('',(-1.,0.,0.));
#2749=DIRECTION('',(0.,0.,1.));
#2750=AXIS2_PLACEMENT_3D('',#2747,#2748,#2749);
#2751=CIRCLE('',#2750,0.381);
#2752=EDGE_CURVE('E1005',#1697,#1816,#2751,.T.);
#2753=ORIENTED_EDGE('',*,*,#2752,.F.);
#2754=ORIENTED_EDGE('',*,*,#1732,.F.);
#2755=EDGE_LOOP('',(#2745,#2746,#2753,#2754));
#2756=FACE_BOUND('',#2755,.T.);
#2757=ADVANCED_FACE('F1607',(#2756),#2744,.T.);
#2758=CARTESIAN_POINT('',(110.236,-1.143,-30.988));
#2759=DIRECTION('',(0.,1.,0.));
#2760=DIRECTION('',(-1.,0.,0.));
#2761=AXIS2_PLACEMENT_3D('',#2758,#2759,#2760);
#2762=DEGENERATE_TOROIDAL_SURFACE('',#2761,0.381,0.381,.T.);
#2763=ORIENTED_EDGE('',*,*,#2726,.T.);
#2764=ORIENTED_EDGE('',*,*,#1717,.F.);
#2765=CARTESIAN_POINT('',(110.236,-1.143,-31.369));
#2766=DIRECTION('',(-1.,0.,0.));
#2767=DIRECTION('',(0.,0.,1.));
#2768=AXIS2_PLACEMENT_3D('',#2765,#2766,#2767);
#2769=CIRCLE('',#2768,0.381);
#2770=EDGE_CURVE('E1002',#1884,#1707,#2769,.T.);
#2771=ORIENTED_EDGE('',*,*,#2770,.F.);
#2772=ORIENTED_EDGE('',*,*,#2031,.F.);
#2773=EDGE_LOOP('',(#2763,#2764,#2771,#2772));
#2774=FACE_BOUND('',#2773,.T.);
#2775=ADVANCED_FACE('F1603',(#2774),#2762,.T.);
#2776=CARTESIAN_POINT('',(51.9587482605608,-7.874,-30.607));
#2777=DIRECTION('',(0.,0.,1.));
#2778=DIRECTION('',(1.,0.,0.));
#2779=AXIS2_PLACEMENT_3D('',#2776,#2777,#2778);
#2780=TOROIDAL_SURFACE('',#2779,6.731,0.381);
#2781=ORIENTED_EDGE('',*,*,#2752,.T.);
#2782=ORIENTED_EDGE('',*,*,#1817,.F.);
#2783=CARTESIAN_POINT('',(46.1038644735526,-4.55335294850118,-30.607));
#2784=DIRECTION('',(-0.493336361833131,-0.869838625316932,0.));
#2785=DIRECTION('',(0.869838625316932,-0.493336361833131,0.));
#2786=AXIS2_PLACEMENT_3D('',#2783,#2784,#2785);
#2787=CIRCLE('',#2786,0.381);
#2788=EDGE_CURVE('E999',#1675,#1807,#2787,.T.);
#2789=ORIENTED_EDGE('',*,*,#2788,.F.);
#2790=ORIENTED_EDGE('',*,*,#2181,.F.);
#2791=EDGE_LOOP('',(#2781,#2782,#2789,#2790));
#2792=FACE_BOUND('',#2791,.T.);
#2793=ADVANCED_FACE('F1599',(#2792),#2780,.T.);
#2794=CARTESIAN_POINT('',(48.26,-1.143,-31.369));
#2795=DIRECTION('',(1.,0.,0.));
#2796=DIRECTION('',(0.,1.,0.));
#2797=AXIS2_PLACEMENT_3D('',#2794,#2795,#2796);
#2798=CYLINDRICAL_SURFACE('',#2797,0.381);
#2799=ORIENTED_EDGE('',*,*,#2770,.T.);
#2800=ORIENTED_EDGE('',*,*,#1708,.F.);
#2801=CARTESIAN_POINT('',(51.9587482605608,-1.143,-31.369));
#2802=DIRECTION('',(-1.,0.,0.));
#2803=DIRECTION('',(0.,0.,1.));
#2804=AXIS2_PLACEMENT_3D('',#2801,#2802,#2803);
#2805=CIRCLE('',#2804,0.381);
#2806=EDGE_CURVE('E996',#1892,#1699,#2805,.T.);
#2807=ORIENTED_EDGE('',*,*,#2806,.F.);
#2808=ORIENTED_EDGE('',*,*,#1893,.F.);
#2809=EDGE_LOOP('',(#2799,#2800,#2807,#2808));
#2810=FACE_BOUND('',#2809,.T.);
#2811=ADVANCED_FACE('F1595',(#2810),#2798,.T.);
#2812=CARTESIAN_POINT('',(42.574414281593,-10.776393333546,-30.607));
#2813=DIRECTION('',(-0.493336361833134,-0.86983862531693,0.));
#2814=DIRECTION('',(0.86983862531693,-0.493336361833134,0.));
#2815=AXIS2_PLACEMENT_3D('',#2812,#2813,#2814);
#2816=CYLINDRICAL_SURFACE('',#2815,0.381);
#2817=ORIENTED_EDGE('',*,*,#2788,.T.);
#2818=ORIENTED_EDGE('',*,*,#1808,.F.);
#2819=CARTESIAN_POINT('',(42.574414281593,-10.776393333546,-30.607));
#2820=DIRECTION('',(-0.493336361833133,-0.869838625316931,0.));
#2821=DIRECTION('',(0.869838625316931,-0.493336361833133,0.));
#2822=AXIS2_PLACEMENT_3D('',#2819,#2820,#2821);
#2823=CIRCLE('',#2822,0.381);
#2824=EDGE_CURVE('E993',#1643,#1799,#2823,.T.);
#2825=ORIENTED_EDGE('',*,*,#2824,.F.);
#2826=ORIENTED_EDGE('',*,*,#1682,.F.);
#2827=EDGE_LOOP('',(#2817,#2818,#2825,#2826));
#2828=FACE_BOUND('',#2827,.T.);
#2829=ADVANCED_FACE('F1591',(#2828),#2816,.T.);
#2830=CARTESIAN_POINT('',(51.9587482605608,-7.874,-31.369));
#2831=DIRECTION('',(0.,0.,1.));
#2832=DIRECTION('',(1.,0.,0.));
#2833=AXIS2_PLACEMENT_3D('',#2830,#2831,#2832);
#2834=TOROIDAL_SURFACE('',#2833,6.731,0.381);
#2835=ORIENTED_EDGE('',*,*,#2806,.T.);
#2836=ORIENTED_EDGE('',*,*,#2173,.F.);
#2837=CARTESIAN_POINT('',(46.1038644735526,-4.55335294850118,-31.369));
#2838=DIRECTION('',(-0.493336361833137,-0.869838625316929,0.));
#2839=DIRECTION('',(0.869838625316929,-0.493336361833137,0.));
#2840=AXIS2_PLACEMENT_3D('',#2837,#2838,#2839);
#2841=CIRCLE('',#2840,0.381);
#2842=EDGE_CURVE('E990',#1901,#1667,#2841,.T.);
#2843=ORIENTED_EDGE('',*,*,#2842,.F.);
#2844=ORIENTED_EDGE('',*,*,#1902,.F.);
#2845=EDGE_LOOP('',(#2835,#2836,#2843,#2844));
#2846=FACE_BOUND('',#2845,.T.);
#2847=ADVANCED_FACE('F1587',(#2846),#2834,.T.);
#2848=CARTESIAN_POINT('',(36.83,-7.5184,-30.607));
#2849=DIRECTION('',(0.,0.,1.));
#2850=DIRECTION('',(1.,0.,0.));
#2851=AXIS2_PLACEMENT_3D('',#2848,#2849,#2850);
#2852=TOROIDAL_SURFACE('',#2851,6.60399999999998,0.381);
#2853=ORIENTED_EDGE('',*,*,#2824,.T.);
#2854=ORIENTED_EDGE('',*,*,#1800,.F.);
#2855=CARTESIAN_POINT('',(31.085585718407,-10.776393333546,-30.607));
#2856=DIRECTION('',(-0.493336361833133,0.869838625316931,0.));
#2857=DIRECTION('',(-0.869838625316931,-0.493336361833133,0.));
#2858=AXIS2_PLACEMENT_3D('',#2855,#2856,#2857);
#2859=CIRCLE('',#2858,0.381);
#2860=EDGE_CURVE('E987',#1611,#1790,#2859,.T.);
#2861=ORIENTED_EDGE('',*,*,#2860,.F.);
#2862=ORIENTED_EDGE('',*,*,#1651,.F.);
#2863=EDGE_LOOP('',(#2853,#2854,#2861,#2862));
#2864=FACE_BOUND('',#2863,.T.);
#2865=ADVANCED_FACE('F1583',(#2864),#2852,.T.);
#2866=CARTESIAN_POINT('',(42.574414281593,-10.776393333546,-31.369));
#2867=DIRECTION('',(0.493336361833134,0.86983862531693,0.));
#2868=DIRECTION('',(-0.86983862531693,0.493336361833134,0.));
#2869=AXIS2_PLACEMENT_3D('',#2866,#2867,#2868);
#2870=CYLINDRICAL_SURFACE('',#2869,0.381);
#2871=ORIENTED_EDGE('',*,*,#2842,.T.);
#2872=ORIENTED_EDGE('',*,*,#1668,.F.);
#2873=CARTESIAN_POINT('',(42.574414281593,-10.776393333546,-31.369));
#2874=DIRECTION('',(-0.493336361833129,-0.869838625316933,0.));
#2875=DIRECTION('',(0.869838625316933,-0.493336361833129,0.));
#2876=AXIS2_PLACEMENT_3D('',#2873,#2874,#2875);
#2877=CIRCLE('',#2876,0.381);
#2878=EDGE_CURVE('E984',#1909,#1635,#2877,.T.);
#2879=ORIENTED_EDGE('',*,*,#2878,.F.);
#2880=ORIENTED_EDGE('',*,*,#1910,.F.);
#2881=EDGE_LOOP('',(#2871,#2872,#2879,#2880));
#2882=FACE_BOUND('',#2881,.T.);
#2883=ADVANCED_FACE('F1579',(#2882),#2870,.T.);
#2884=CARTESIAN_POINT('',(31.085585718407,-10.776393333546,-30.607));
#2885=DIRECTION('',(-0.493336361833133,0.869838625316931,0.));
#2886=DIRECTION('',(-0.869838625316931,-0.493336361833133,0.));
#2887=AXIS2_PLACEMENT_3D('',#2884,#2885,#2886);
#2888=CYLINDRICAL_SURFACE('',#2887,0.381);
#2889=ORIENTED_EDGE('',*,*,#2860,.T.);
#2890=ORIENTED_EDGE('',*,*,#1791,.F.);
#2891=CARTESIAN_POINT('',(27.5561355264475,-4.55335294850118,-30.607));
#2892=DIRECTION('',(-0.493336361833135,0.86983862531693,0.));
#2893=DIRECTION('',(-0.86983862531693,-0.493336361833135,0.));
#2894=AXIS2_PLACEMENT_3D('',#2891,#2892,#2893);
#2895=CIRCLE('',#2894,0.381);
#2896=EDGE_CURVE('E981',#1593,#1782,#2895,.T.);
#2897=ORIENTED_EDGE('',*,*,#2896,.F.);
#2898=ORIENTED_EDGE('',*,*,#1618,.F.);
#2899=EDGE_LOOP('',(#2889,#2890,#2897,#2898));
#2900=FACE_BOUND('',#2899,.T.);
#2901=ADVANCED_FACE('F1575',(#2900),#2888,.T.);
#2902=CARTESIAN_POINT('',(36.83,-7.5184,-31.369));
#2903=DIRECTION('',(0.,0.,1.));
#2904=DIRECTION('',(1.,0.,0.));
#2905=AXIS2_PLACEMENT_3D('',#2902,#2903,#2904);
#2906=TOROIDAL_SURFACE('',#2905,6.60399999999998,0.381);
#2907=ORIENTED_EDGE('',*,*,#2878,.T.);
#2908=ORIENTED_EDGE('',*,*,#1636,.F.);
#2909=CARTESIAN_POINT('',(31.085585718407,-10.776393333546,-31.369));
#2910=DIRECTION('',(-0.493336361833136,0.869838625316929,0.));
#2911=DIRECTION('',(-0.869838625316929,-0.493336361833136,0.));
#2912=AXIS2_PLACEMENT_3D('',#2909,#2910,#2911);
#2913=CIRCLE('',#2912,0.381);
#2914=EDGE_CURVE('E978',#1918,#1603,#2913,.T.);
#2915=ORIENTED_EDGE('',*,*,#2914,.F.);
#2916=ORIENTED_EDGE('',*,*,#1919,.F.);
#2917=EDGE_LOOP('',(#2907,#2908,#2915,#2916));
#2918=FACE_BOUND('',#2917,.T.);
#2919=ADVANCED_FACE('F1571',(#2918),#2906,.T.);
#2920=CARTESIAN_POINT('',(21.7012517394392,-7.874,-30.607));
#2921=DIRECTION('',(0.,0.,1.));
#2922=DIRECTION('',(1.,0.,0.));
#2923=AXIS2_PLACEMENT_3D('',#2920,#2921,#2922);
#2924=TOROIDAL_SURFACE('',#2923,6.731,0.381);
#2925=ORIENTED_EDGE('',*,*,#2896,.T.);
#2926=ORIENTED_EDGE('',*,*,#1783,.F.);
#2927=CARTESIAN_POINT('',(21.7012517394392,-1.143,-30.607));
#2928=DIRECTION('',(-1.,0.,0.));
#2929=DIRECTION('',(0.,0.,1.));
#2930=AXIS2_PLACEMENT_3D('',#2927,#2928,#2929);
#2931=CIRCLE('',#2930,0.381);
#2932=EDGE_CURVE('E975',#1562,#1773,#2931,.T.);
#2933=ORIENTED_EDGE('',*,*,#2932,.F.);
#2934=ORIENTED_EDGE('',*,*,#2157,.F.);
#2935=EDGE_LOOP('',(#2925,#2926,#2933,#2934));
#2936=FACE_BOUND('',#2935,.T.);
#2937=ADVANCED_FACE('F1567',(#2936),#2924,.T.);
#2938=CARTESIAN_POINT('',(31.085585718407,-10.776393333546,-31.369));
#2939=DIRECTION('',(0.493336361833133,-0.869838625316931,0.));
#2940=DIRECTION('',(0.869838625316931,0.493336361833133,0.));
#2941=AXIS2_PLACEMENT_3D('',#2938,#2939,#2940);
#2942=CYLINDRICAL_SURFACE('',#2941,0.381);
#2943=ORIENTED_EDGE('',*,*,#2914,.T.);
#2944=ORIENTED_EDGE('',*,*,#1604,.F.);
#2945=CARTESIAN_POINT('',(27.5561355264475,-4.55335294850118,-31.369));
#2946=DIRECTION('',(-0.493336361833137,0.869838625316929,0.));
#2947=DIRECTION('',(-0.869838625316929,-0.493336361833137,0.));
#2948=AXIS2_PLACEMENT_3D('',#2945,#2946,#2947);
#2949=CIRCLE('',#2948,0.381);
#2950=EDGE_CURVE('E972',#1850,#1595,#2949,.T.);
#2951=ORIENTED_EDGE('',*,*,#2950,.F.);
#2952=ORIENTED_EDGE('',*,*,#1925,.F.);
#2953=EDGE_LOOP('',(#2943,#2944,#2951,#2952));
#2954=FACE_BOUND('',#2953,.T.);
#2955=ADVANCED_FACE('F1563',(#2954),#2942,.T.);
#2956=CARTESIAN_POINT('',(36.83,-1.143,-30.607));
#2957=DIRECTION('',(-1.,0.,0.));
#2958=DIRECTION('',(0.,-1.,0.));
#2959=AXIS2_PLACEMENT_3D('',#2956,#2957,#2958);
#2960=CYLINDRICAL_SURFACE('',#2959,0.381);
#2961=ORIENTED_EDGE('',*,*,#2932,.T.);
#2962=ORIENTED_EDGE('',*,*,#1774,.F.);
#2963=CARTESIAN_POINT('',(5.842,-1.143,-30.607));
#2964=DIRECTION('',(-1.,0.,0.));
#2965=DIRECTION('',(0.,0.,1.));
#2966=AXIS2_PLACEMENT_3D('',#2963,#2964,#2965);
#2967=CIRCLE('',#2966,0.381);
#2968=EDGE_CURVE('E969',#1570,#1765,#2967,.T.);
#2969=ORIENTED_EDGE('',*,*,#2968,.F.);
#2970=ORIENTED_EDGE('',*,*,#1571,.F.);
#2971=EDGE_LOOP('',(#2961,#2962,#2969,#2970));
#2972=FACE_BOUND('',#2971,.T.);
#2973=ADVANCED_FACE('F1559',(#2972),#2960,.T.);
#2974=CARTESIAN_POINT('',(21.7012517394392,-7.874,-31.369));
#2975=DIRECTION('',(0.,0.,1.));
#2976=DIRECTION('',(1.,0.,0.));
#2977=AXIS2_PLACEMENT_3D('',#2974,#2975,#2976);
#2978=TOROIDAL_SURFACE('',#2977,6.731,0.381);
#2979=ORIENTED_EDGE('',*,*,#2950,.T.);
#2980=ORIENTED_EDGE('',*,*,#2149,.F.);
#2981=CARTESIAN_POINT('',(21.7012517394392,-1.143,-31.369));
#2982=DIRECTION('',(-1.,0.,0.));
#2983=DIRECTION('',(0.,0.,1.));
#2984=AXIS2_PLACEMENT_3D('',#2981,#2982,#2983);
#2985=CIRCLE('',#2984,0.381);
#2986=EDGE_CURVE('E966',#1852,#1554,#2985,.T.);
#2987=ORIENTED_EDGE('',*,*,#2986,.F.);
#2988=ORIENTED_EDGE('',*,*,#1853,.F.);
#2989=EDGE_LOOP('',(#2979,#2980,#2987,#2988));
#2990=FACE_BOUND('',#2989,.T.);
#2991=ADVANCED_FACE('F1555',(#2990),#2978,.T.);
#2992=CARTESIAN_POINT('',(5.842,-1.143,-30.988));
#2993=DIRECTION('',(0.,1.,0.));
#2994=DIRECTION('',(-1.,0.,0.));
#2995=AXIS2_PLACEMENT_3D('',#2992,#2993,#2994);
#2996=DEGENERATE_TOROIDAL_SURFACE('',#2995,0.381,0.381,.T.);
#2997=ORIENTED_EDGE('',*,*,#2968,.T.);
#2998=ORIENTED_EDGE('',*,*,#1974,.F.);
#2999=CARTESIAN_POINT('',(5.461,-1.143,-30.988));
#3000=DIRECTION('',(0.,0.,-1.));
#3001=DIRECTION('',(-1.,0.,0.));
#3002=AXIS2_PLACEMENT_3D('',#2999,#3000,#3001);
#3003=CIRCLE('',#3002,0.381);
#3004=EDGE_CURVE('E964',#1544,#1942,#3003,.T.);
#3005=ORIENTED_EDGE('',*,*,#3004,.F.);
#3006=ORIENTED_EDGE('',*,*,#1578,.F.);
#3007=EDGE_LOOP('',(#2997,#2998,#3005,#3006));
#3008=FACE_BOUND('',#3007,.T.);
#3009=ADVANCED_FACE('F1551',(#3008),#2996,.T.);
#3010=CARTESIAN_POINT('',(5.08,-1.143,-31.369));
#3011=DIRECTION('',(1.,0.,0.));
#3012=DIRECTION('',(0.,1.,0.));
#3013=AXIS2_PLACEMENT_3D('',#3010,#3011,#3012);
#3014=CYLINDRICAL_SURFACE('',#3013,0.381);
#3015=ORIENTED_EDGE('',*,*,#2986,.T.);
#3016=ORIENTED_EDGE('',*,*,#1555,.F.);
#3017=CARTESIAN_POINT('',(5.842,-1.143,-31.369));
#3018=DIRECTION('',(-1.,0.,0.));
#3019=DIRECTION('',(0.,0.,1.));
#3020=AXIS2_PLACEMENT_3D('',#3017,#3018,#3019);
#3021=CIRCLE('',#3020,0.381);
#3022=EDGE_CURVE('E962',#1860,#1546,#3021,.T.);
#3023=ORIENTED_EDGE('',*,*,#3022,.F.);
#3024=ORIENTED_EDGE('',*,*,#1861,.F.);
#3025=EDGE_LOOP('',(#3015,#3016,#3023,#3024));
#3026=FACE_BOUND('',#3025,.T.);
#3027=ADVANCED_FACE('F1547',(#3026),#3014,.T.);
#3028=CARTESIAN_POINT('',(5.842,-1.143,-30.988));
#3029=DIRECTION('',(0.,1.,0.));
#3030=DIRECTION('',(-1.,0.,0.));
#3031=AXIS2_PLACEMENT_3D('',#3028,#3029,#3030);
#3032=DEGENERATE_TOROIDAL_SURFACE('',#3031,0.381,0.381,.T.);
#3033=ORIENTED_EDGE('',*,*,#3004,.T.);
#3034=ORIENTED_EDGE('',*,*,#1943,.F.);
#3035=ORIENTED_EDGE('',*,*,#3022,.T.);
#3036=ORIENTED_EDGE('',*,*,#1547,.F.);
#3037=EDGE_LOOP('',(#3033,#3034,#3035,#3036));
#3038=FACE_BOUND('',#3037,.T.);
#3039=ADVANCED_FACE('F1543',(#3038),#3032,.T.);
#3040=CARTESIAN_POINT('',(36.83,-0.381,-5.207));
#3041=DIRECTION('',(1.,0.,0.));
#3042=DIRECTION('',(0.,0.,-1.));
#3043=AXIS2_PLACEMENT_3D('',#3040,#3041,#3042);
#3044=CYLINDRICAL_SURFACE('',#3043,0.381);
#3045=CARTESIAN_POINT('',(110.236,-0.381,-5.207));
#3046=DIRECTION('',(-1.,0.,0.));
#3047=DIRECTION('',(0.,0.,1.));
#3048=AXIS2_PLACEMENT_3D('',#3045,#3046,#3047);
#3049=CIRCLE('',#3048,0.381);
#3050=EDGE_CURVE('E956',#1295,#370,#3049,.T.);
#3051=ORIENTED_EDGE('',*,*,#3050,.F.);
#3052=ORIENTED_EDGE('',*,*,#1296,.F.);
#3053=CARTESIAN_POINT('',(5.842,-0.381,-5.207));
#3054=DIRECTION('',(1.,0.,0.));
#3055=DIRECTION('',(0.,0.,-1.));
#3056=AXIS2_PLACEMENT_3D('',#3053,#3054,#3055);
#3057=CIRCLE('',#3056,0.381);
#3058=EDGE_CURVE('E959',#378,#1287,#3057,.T.);
#3059=ORIENTED_EDGE('',*,*,#3058,.F.);
#3060=ORIENTED_EDGE('',*,*,#379,.F.);
#3061=EDGE_LOOP('',(#3051,#3052,#3059,#3060));
#3062=FACE_BOUND('',#3061,.T.);
#3063=ADVANCED_FACE('F1539',(#3062),#3044,.F.);
#3064=CARTESIAN_POINT('',(5.842,-0.381,-4.064));
#3065=DIRECTION('',(0.,1.,0.));
#3066=DIRECTION('',(0.,0.,1.));
#3067=AXIS2_PLACEMENT_3D('',#3064,#3065,#3066);
#3068=TOROIDAL_SURFACE('',#3067,1.143,0.381);
#3069=ORIENTED_EDGE('',*,*,#3058,.T.);
#3070=ORIENTED_EDGE('',*,*,#1401,.F.);
#3071=CARTESIAN_POINT('',(4.699,-0.381,-4.064));
#3072=DIRECTION('',(0.,0.,-1.));
#3073=DIRECTION('',(-1.,0.,0.));
#3074=AXIS2_PLACEMENT_3D('',#3071,#3072,#3073);
#3075=CIRCLE('',#3074,0.381);
#3076=EDGE_CURVE('E953',#342,#1361,#3075,.T.);
#3077=ORIENTED_EDGE('',*,*,#3076,.F.);
#3078=ORIENTED_EDGE('',*,*,#386,.F.);
#3079=EDGE_LOOP('',(#3069,#3070,#3077,#3078));
#3080=FACE_BOUND('',#3079,.T.);
#3081=ADVANCED_FACE('F1535',(#3080),#3068,.F.);
#3082=CARTESIAN_POINT('',(110.236,-0.381,-4.064));
#3083=DIRECTION('',(0.,1.,0.));
#3084=DIRECTION('',(0.,0.,1.));
#3085=AXIS2_PLACEMENT_3D('',#3082,#3083,#3084);
#3086=TOROIDAL_SURFACE('',#3085,1.143,0.381);
#3087=ORIENTED_EDGE('',*,*,#3050,.T.);
#3088=ORIENTED_EDGE('',*,*,#371,.F.);
#3089=CARTESIAN_POINT('',(111.379,-0.381,-4.064));
#3090=DIRECTION('',(0.,0.,-1.));
#3091=DIRECTION('',(-1.,0.,0.));
#3092=AXIS2_PLACEMENT_3D('',#3089,#3090,#3091);
#3093=CIRCLE('',#3092,0.381);
#3094=EDGE_CURVE('E950',#1418,#361,#3093,.T.);
#3095=ORIENTED_EDGE('',*,*,#3094,.F.);
#3096=ORIENTED_EDGE('',*,*,#1434,.F.);
#3097=EDGE_LOOP('',(#3087,#3088,#3095,#3096));
#3098=FACE_BOUND('',#3097,.T.);
#3099=ADVANCED_FACE('F1531',(#3098),#3086,.F.);
#3100=CARTESIAN_POINT('',(5.842,-0.381,-4.064));
#3101=DIRECTION('',(0.,1.,0.));
#3102=DIRECTION('',(0.,0.,1.));
#3103=AXIS2_PLACEMENT_3D('',#3100,#3101,#3102);
#3104=TOROIDAL_SURFACE('',#3103,1.143,0.381);
#3105=ORIENTED_EDGE('',*,*,#3076,.T.);
#3106=ORIENTED_EDGE('',*,*,#1377,.F.);
#3107=CARTESIAN_POINT('',(5.842,-0.381,-2.921));
#3108=DIRECTION('',(-1.,0.,0.));
#3109=DIRECTION('',(0.,0.,1.));
#3110=AXIS2_PLACEMENT_3D('',#3107,#3108,#3109);
#3111=CIRCLE('',#3110,0.381);
#3112=EDGE_CURVE('E948',#344,#643,#3111,.T.);
#3113=ORIENTED_EDGE('',*,*,#3112,.F.);
#3114=ORIENTED_EDGE('',*,*,#345,.F.);
#3115=EDGE_LOOP('',(#3105,#3106,#3113,#3114));
#3116=FACE_BOUND('',#3115,.T.);
#3117=ADVANCED_FACE('F1527',(#3116),#3104,.F.);
#3118=CARTESIAN_POINT('',(110.236,-0.381,-4.064));
#3119=DIRECTION('',(0.,1.,0.));
#3120=DIRECTION('',(0.,0.,1.));
#3121=AXIS2_PLACEMENT_3D('',#3118,#3119,#3120);
#3122=TOROIDAL_SURFACE('',#3121,1.143,0.381);
#3123=ORIENTED_EDGE('',*,*,#3094,.T.);
#3124=ORIENTED_EDGE('',*,*,#362,.F.);
#3125=CARTESIAN_POINT('',(110.236,-0.381,-2.921));
#3126=DIRECTION('',(1.,0.,0.));
#3127=DIRECTION('',(0.,0.,-1.));
#3128=AXIS2_PLACEMENT_3D('',#3125,#3126,#3127);
#3129=CIRCLE('',#3128,0.381);
#3130=EDGE_CURVE('E946',#635,#352,#3129,.T.);
#3131=ORIENTED_EDGE('',*,*,#3130,.F.);
#3132=ORIENTED_EDGE('',*,*,#1458,.F.);
#3133=EDGE_LOOP('',(#3123,#3124,#3131,#3132));
#3134=FACE_BOUND('',#3133,.T.);
#3135=ADVANCED_FACE('F1523',(#3134),#3122,.F.);
#3136=CARTESIAN_POINT('',(3.81,-0.381,-2.921));
#3137=DIRECTION('',(-1.,0.,0.));
#3138=DIRECTION('',(0.,0.,1.));
#3139=AXIS2_PLACEMENT_3D('',#3136,#3137,#3138);
#3140=CYLINDRICAL_SURFACE('',#3139,0.381);
#3141=ORIENTED_EDGE('',*,*,#3112,.T.);
#3142=ORIENTED_EDGE('',*,*,#644,.F.);
#3143=ORIENTED_EDGE('',*,*,#3130,.T.);
#3144=ORIENTED_EDGE('',*,*,#353,.F.);
#3145=EDGE_LOOP('',(#3141,#3142,#3143,#3144));
#3146=FACE_BOUND('',#3145,.T.);
#3147=ADVANCED_FACE('F1519',(#3146),#3140,.F.);
#3148=CARTESIAN_POINT('',(36.83,-0.381,-32.131));
#3149=DIRECTION('',(-1.,0.,0.));
#3150=DIRECTION('',(0.,0.,1.));
#3151=AXIS2_PLACEMENT_3D('',#3148,#3149,#3150);
#3152=CYLINDRICAL_SURFACE('',#3151,0.381);
#3153=CARTESIAN_POINT('',(110.236,-0.381,-32.131));
#3154=DIRECTION('',(-1.,0.,0.));
#3155=DIRECTION('',(0.,0.,1.));
#3156=AXIS2_PLACEMENT_3D('',#3153,#3154,#3155);
#3157=CIRCLE('',#3156,0.381);
#3158=EDGE_CURVE('E940',#1876,#424,#3157,.T.);
#3159=ORIENTED_EDGE('',*,*,#3158,.F.);
#3160=ORIENTED_EDGE('',*,*,#1877,.F.);
#3161=CARTESIAN_POINT('',(5.842,-0.381,-32.131));
#3162=DIRECTION('',(1.,0.,0.));
#3163=DIRECTION('',(0.,0.,-1.));
#3164=AXIS2_PLACEMENT_3D('',#3161,#3162,#3163);
#3165=CIRCLE('',#3164,0.381);
#3166=EDGE_CURVE('E943',#432,#1868,#3165,.T.);
#3167=ORIENTED_EDGE('',*,*,#3166,.F.);
#3168=ORIENTED_EDGE('',*,*,#433,.F.);
#3169=EDGE_LOOP('',(#3159,#3160,#3167,#3168));
#3170=FACE_BOUND('',#3169,.T.);
#3171=ADVANCED_FACE('F1515',(#3170),#3152,.F.);
#3172=CARTESIAN_POINT('',(5.842,-0.381,-30.988));
#3173=DIRECTION('',(0.,1.,0.));
#3174=DIRECTION('',(0.,0.,1.));
#3175=AXIS2_PLACEMENT_3D('',#3172,#3173,#3174);
#3176=TOROIDAL_SURFACE('',#3175,1.143,0.381);
#3177=ORIENTED_EDGE('',*,*,#3166,.T.);
#3178=ORIENTED_EDGE('',*,*,#1958,.F.);
#3179=CARTESIAN_POINT('',(4.699,-0.381,-30.988));
#3180=DIRECTION('',(0.,0.,-1.));
#3181=DIRECTION('',(-1.,0.,0.));
#3182=AXIS2_PLACEMENT_3D('',#3179,#3180,#3181);
#3183=CIRCLE('',#3182,0.381);
#3184=EDGE_CURVE('E937',#396,#1950,#3183,.T.);
#3185=ORIENTED_EDGE('',*,*,#3184,.F.);
#3186=ORIENTED_EDGE('',*,*,#440,.F.);
#3187=EDGE_LOOP('',(#3177,#3178,#3185,#3186));
#3188=FACE_BOUND('',#3187,.T.);
#3189=ADVANCED_FACE('F1511',(#3188),#3176,.F.);
#3190=CARTESIAN_POINT('',(110.236,-0.381,-30.988));
#3191=DIRECTION('',(0.,1.,0.));
#3192=DIRECTION('',(0.,0.,1.));
#3193=AXIS2_PLACEMENT_3D('',#3190,#3191,#3192);
#3194=TOROIDAL_SURFACE('',#3193,1.143,0.381);
#3195=ORIENTED_EDGE('',*,*,#3158,.T.);
#3196=ORIENTED_EDGE('',*,*,#425,.F.);
#3197=CARTESIAN_POINT('',(111.379,-0.381,-30.988));
#3198=DIRECTION('',(0.,0.,-1.));
#3199=DIRECTION('',(0.,1.,0.));
#3200=AXIS2_PLACEMENT_3D('',#3197,#3198,#3199);
#3201=CIRCLE('',#3200,0.381);
#3202=EDGE_CURVE('E934',#2007,#415,#3201,.T.);
#3203=ORIENTED_EDGE('',*,*,#3202,.F.);
#3204=ORIENTED_EDGE('',*,*,#2039,.F.);
#3205=EDGE_LOOP('',(#3195,#3196,#3203,#3204));
#3206=FACE_BOUND('',#3205,.T.);
#3207=ADVANCED_FACE('F1507',(#3206),#3194,.F.);
#3208=CARTESIAN_POINT('',(5.842,-0.381,-30.988));
#3209=DIRECTION('',(0.,1.,0.));
#3210=DIRECTION('',(0.,0.,1.));
#3211=AXIS2_PLACEMENT_3D('',#3208,#3209,#3210);
#3212=TOROIDAL_SURFACE('',#3211,1.143,0.381);
#3213=ORIENTED_EDGE('',*,*,#3184,.T.);
#3214=ORIENTED_EDGE('',*,*,#1982,.F.);
#3215=CARTESIAN_POINT('',(5.842,-0.381,-29.845));
#3216=DIRECTION('',(-1.,0.,0.));
#3217=DIRECTION('',(0.,0.,1.));
#3218=AXIS2_PLACEMENT_3D('',#3215,#3216,#3217);
#3219=CIRCLE('',#3218,0.381);
#3220=EDGE_CURVE('E932',#398,#1757,#3219,.T.);
#3221=ORIENTED_EDGE('',*,*,#3220,.F.);
#3222=ORIENTED_EDGE('',*,*,#399,.F.);
#3223=EDGE_LOOP('',(#3213,#3214,#3221,#3222));
#3224=FACE_BOUND('',#3223,.T.);
#3225=ADVANCED_FACE('F1503',(#3224),#3212,.F.);
#3226=CARTESIAN_POINT('',(110.236,-0.381,-30.988));
#3227=DIRECTION('',(0.,1.,0.));
#3228=DIRECTION('',(0.,0.,1.));
#3229=AXIS2_PLACEMENT_3D('',#3226,#3227,#3228);
#3230=TOROIDAL_SURFACE('',#3229,1.143,0.381);
#3231=ORIENTED_EDGE('',*,*,#3202,.T.);
#3232=ORIENTED_EDGE('',*,*,#416,.F.);
#3233=CARTESIAN_POINT('',(110.236,-0.381,-29.845));
#3234=DIRECTION('',(1.,0.,0.));
#3235=DIRECTION('',(0.,0.,-1.));
#3236=AXIS2_PLACEMENT_3D('',#3233,#3234,#3235);
#3237=CIRCLE('',#3236,0.381);
#3238=EDGE_CURVE('E923',#1749,#406,#3237,.T.);
#3239=ORIENTED_EDGE('',*,*,#3238,.F.);
#3240=ORIENTED_EDGE('',*,*,#2015,.F.);
#3241=EDGE_LOOP('',(#3231,#3232,#3239,#3240));
#3242=FACE_BOUND('',#3241,.T.);
#3243=ADVANCED_FACE('F1499',(#3242),#3230,.F.);
#3244=CARTESIAN_POINT('',(3.81,-0.381,-29.845));
#3245=DIRECTION('',(1.,0.,0.));
#3246=DIRECTION('',(0.,0.,-1.));
#3247=AXIS2_PLACEMENT_3D('',#3244,#3245,#3246);
#3248=CYLINDRICAL_SURFACE('',#3247,0.381);
#3249=ORIENTED_EDGE('',*,*,#3220,.T.);
#3250=ORIENTED_EDGE('',*,*,#1758,.F.);
#3251=ORIENTED_EDGE('',*,*,#3238,.T.);
#3252=ORIENTED_EDGE('',*,*,#407,.F.);
#3253=EDGE_LOOP('',(#3249,#3250,#3251,#3252));
#3254=FACE_BOUND('',#3253,.T.);
#3255=ADVANCED_FACE('F1495',(#3254),#3248,.F.);
#3256=CARTESIAN_POINT('',(14.605,-0.381,-17.526));
#3257=DIRECTION('',(0.,1.,0.));
#3258=DIRECTION('',(0.,0.,1.));
#3259=AXIS2_PLACEMENT_3D('',#3256,#3257,#3258);
#3260=TOROIDAL_SURFACE('',#3259,9.652,0.381);
#3261=ORIENTED_EDGE('',*,*,#332,.F.);
#3262=EDGE_LOOP('',(#3261));
#3263=FACE_BOUND('',#3262,.T.);
#3264=ORIENTED_EDGE('',*,*,#2336,.F.);
#3265=EDGE_LOOP('',(#3264));
#3266=FACE_BOUND('',#3265,.T.);
#3267=ADVANCED_FACE('F1491',(#3263,#3266),#3260,.F.);
#3268=CARTESIAN_POINT('',(14.605,-0.381,-17.526));
#3269=DIRECTION('',(0.,1.,0.));
#3270=DIRECTION('',(0.,0.,1.));
#3271=AXIS2_PLACEMENT_3D('',#3268,#3269,#3270);
#3272=TOROIDAL_SURFACE('',#3271,7.62,0.381);
#3273=ORIENTED_EDGE('',*,*,#2364,.F.);
#3274=EDGE_LOOP('',(#3273));
#3275=FACE_BOUND('',#3274,.T.);
#3276=ORIENTED_EDGE('',*,*,#2387,.F.);
#3277=EDGE_LOOP('',(#3276));
#3278=FACE_BOUND('',#3277,.T.);
#3279=ADVANCED_FACE('F1487',(#3275,#3278),#3272,.F.);
#3280=CARTESIAN_POINT('',(14.605,-1.143,-17.526));
#3281=DIRECTION('',(0.,-1.,0.));
#3282=DIRECTION('',(1.,0.,0.));
#3283=AXIS2_PLACEMENT_3D('',#3280,#3281,#3282);
#3284=TOROIDAL_SURFACE('',#3283,8.382,0.381);
#3285=ORIENTED_EDGE('',*,*,#2308,.F.);
#3286=EDGE_LOOP('',(#3285));
#3287=FACE_BOUND('',#3286,.T.);
#3288=ORIENTED_EDGE('',*,*,#2375,.F.);
#3289=EDGE_LOOP('',(#3288));
#3290=FACE_BOUND('',#3289,.T.);
#3291=ADVANCED_FACE('F1483',(#3287,#3290),#3284,.T.);
#3292=CARTESIAN_POINT('',(14.605,-1.143,-17.526));
#3293=DIRECTION('',(0.,-1.,0.));
#3294=DIRECTION('',(1.,0.,0.));
#3295=AXIS2_PLACEMENT_3D('',#3292,#3293,#3294);
#3296=TOROIDAL_SURFACE('',#3295,8.89,0.381);
#3297=ORIENTED_EDGE('',*,*,#2347,.F.);
#3298=EDGE_LOOP('',(#3297));
#3299=FACE_BOUND('',#3298,.T.);
#3300=ORIENTED_EDGE('',*,*,#2319,.F.);
#3301=EDGE_LOOP('',(#3300));
#3302=FACE_BOUND('',#3301,.T.);
#3303=ADVANCED_FACE('F1480',(#3299,#3302),#3296,.T.);
#3304=CARTESIAN_POINT('',(111.76,2.032,-3.59210244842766));
#3305=DIRECTION('',(1.,0.,0.));
#3306=DIRECTION('',(0.,0.,-1.));
#3307=AXIS2_PLACEMENT_3D('',#3304,#3305,#3306);
#3308=PLANE('',#3307);
#3309=ORIENTED_EDGE('',*,*,#283,.T.);
#3310=DIRECTION('',(0.,1.,0.));
#3311=VECTOR('',#3310,1.);
#3312=CARTESIAN_POINT('',(111.76,2.032,-31.4598975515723));
#3313=LINE('',#3312,#3311);
#3314=CARTESIAN_POINT('',(111.76,2.032,-31.4598975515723));
#3315=VERTEX_POINT('',#3314);
#3316=EDGE_CURVE('E920',#3315,#282,#3313,.T.);
#3317=ORIENTED_EDGE('',*,*,#3316,.F.);
#3318=DIRECTION('',(0.,0.,-1.));
#3319=VECTOR('',#3318,1.);
#3320=CARTESIAN_POINT('',(111.76,2.032,-3.59210244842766));
#3321=LINE('',#3320,#3319);
#3322=CARTESIAN_POINT('',(111.76,2.032,-3.59210244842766));
#3323=VERTEX_POINT('',#3322);
#3324=EDGE_CURVE('E910',#3323,#3315,#3321,.T.);
#3325=ORIENTED_EDGE('',*,*,#3324,.F.);
#3326=DIRECTION('',(0.,1.,0.));
#3327=VECTOR('',#3326,1.);
#3328=CARTESIAN_POINT('',(111.76,2.032,-3.59210244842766));
#3329=LINE('',#3328,#3327);
#3330=EDGE_CURVE('E921',#3323,#280,#3329,.T.);
#3331=ORIENTED_EDGE('',*,*,#3330,.T.);
#3332=EDGE_LOOP('',(#3309,#3317,#3325,#3331));
#3333=FACE_BOUND('',#3332,.T.);
#3334=ADVANCED_FACE('F1473',(#3333),#3308,.F.);
#3335=CARTESIAN_POINT('',(111.76,2.032,-3.59210244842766));
#3336=DIRECTION('',(0.,0.,-1.));
#3337=DIRECTION('',(-1.,0.,0.));
#3338=AXIS2_PLACEMENT_3D('',#3335,#3336,#3337);
#3339=PLANE('',#3338);
#3340=ORIENTED_EDGE('',*,*,#795,.F.);
#3341=ORIENTED_EDGE('',*,*,#3330,.F.);
#3342=DIRECTION('',(-1.,0.,0.));
#3343=VECTOR('',#3342,1.);
#3344=CARTESIAN_POINT('',(111.76,2.032,-3.59210244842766));
#3345=LINE('',#3344,#3343);
#3346=CARTESIAN_POINT('',(109.728,2.032,-3.59210244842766));
#3347=VERTEX_POINT('',#3346);
#3348=EDGE_CURVE('E918',#3323,#3347,#3345,.T.);
#3349=ORIENTED_EDGE('',*,*,#3348,.T.);
#3350=DIRECTION('',(0.,1.,0.));
#3351=VECTOR('',#3350,1.);
#3352=CARTESIAN_POINT('',(109.728,2.032,-3.59210244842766));
#3353=LINE('',#3352,#3351);
#3354=EDGE_CURVE('E924',#3347,#259,#3353,.T.);
#3355=ORIENTED_EDGE('',*,*,#3354,.T.);
#3356=EDGE_LOOP('',(#3340,#3341,#3349,#3355));
#3357=FACE_BOUND('',#3356,.T.);
#3358=ADVANCED_FACE('F1432',(#3357),#3339,.T.);
#3359=CARTESIAN_POINT('',(109.728,2.032,-31.4598975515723));
#3360=DIRECTION('',(-1.,0.,0.));
#3361=DIRECTION('',(0.,0.,1.));
#3362=AXIS2_PLACEMENT_3D('',#3359,#3360,#3361);
#3363=PLANE('',#3362);
#3364=ORIENTED_EDGE('',*,*,#268,.T.);
#3365=ORIENTED_EDGE('',*,*,#3354,.F.);
#3366=DIRECTION('',(0.,0.,1.));
#3367=VECTOR('',#3366,1.);
#3368=CARTESIAN_POINT('',(109.728,2.032,-31.4598975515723));
#3369=LINE('',#3368,#3367);
#3370=CARTESIAN_POINT('',(109.728,2.032,-31.4598975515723));
#3371=VERTEX_POINT('',#3370);
#3372=EDGE_CURVE('E915',#3371,#3347,#3369,.T.);
#3373=ORIENTED_EDGE('',*,*,#3372,.F.);
#3374=DIRECTION('',(0.,1.,0.));
#3375=VECTOR('',#3374,1.);
#3376=CARTESIAN_POINT('',(109.728,2.032,-31.4598975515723));
#3377=LINE('',#3376,#3375);
#3378=EDGE_CURVE('E927',#3371,#267,#3377,.T.);
#3379=ORIENTED_EDGE('',*,*,#3378,.T.);
#3380=EDGE_LOOP('',(#3364,#3365,#3373,#3379));
#3381=FACE_BOUND('',#3380,.T.);
#3382=ADVANCED_FACE('F1437',(#3381),#3363,.F.);
#3383=CARTESIAN_POINT('',(109.728,2.032,-31.4598975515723));
#3384=DIRECTION('',(0.,0.,1.));
#3385=DIRECTION('',(1.,0.,0.));
#3386=AXIS2_PLACEMENT_3D('',#3383,#3384,#3385);
#3387=PLANE('',#3386);
#3388=ORIENTED_EDGE('',*,*,#1048,.F.);
#3389=ORIENTED_EDGE('',*,*,#3378,.F.);
#3390=DIRECTION('',(1.,0.,0.));
#3391=VECTOR('',#3390,1.);
#3392=CARTESIAN_POINT('',(109.728,2.032,-31.4598975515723));
#3393=LINE('',#3392,#3391);
#3394=EDGE_CURVE('E913',#3371,#3315,#3393,.T.);
#3395=ORIENTED_EDGE('',*,*,#3394,.T.);
#3396=ORIENTED_EDGE('',*,*,#3316,.T.);
#3397=EDGE_LOOP('',(#3388,#3389,#3395,#3396));
#3398=FACE_BOUND('',#3397,.T.);
#3399=ADVANCED_FACE('F1469',(#3398),#3387,.T.);
#3400=CARTESIAN_POINT('',(111.76,2.032,-31.4598975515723));
#3401=DIRECTION('',(0.,-1.,0.));
#3402=DIRECTION('',(0.,0.,-1.));
#3403=AXIS2_PLACEMENT_3D('',#3400,#3401,#3402);
#3404=PLANE('',#3403);
#3405=ORIENTED_EDGE('',*,*,#3324,.T.);
#3406=ORIENTED_EDGE('',*,*,#3394,.F.);
#3407=ORIENTED_EDGE('',*,*,#3372,.T.);
#3408=ORIENTED_EDGE('',*,*,#3348,.F.);
#3409=EDGE_LOOP('',(#3405,#3406,#3407,#3408));
#3410=FACE_BOUND('',#3409,.T.);
#3411=ADVANCED_FACE('F1460',(#3410),#3404,.F.);
#3412=CARTESIAN_POINT('',(107.696,2.032,-3.59210244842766));
#3413=DIRECTION('',(1.,0.,0.));
#3414=DIRECTION('',(0.,0.,-1.));
#3415=AXIS2_PLACEMENT_3D('',#3412,#3413,#3414);
#3416=PLANE('',#3415);
#3417=ORIENTED_EDGE('',*,*,#256,.T.);
#3418=DIRECTION('',(0.,1.,0.));
#3419=VECTOR('',#3418,1.);
#3420=CARTESIAN_POINT('',(107.696,2.032,-31.4598975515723));
#3421=LINE('',#3420,#3419);
#3422=CARTESIAN_POINT('',(107.696,2.032,-31.4598975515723));
#3423=VERTEX_POINT('',#3422);
#3424=EDGE_CURVE('E889',#3423,#255,#3421,.T.);
#3425=ORIENTED_EDGE('',*,*,#3424,.F.);
#3426=DIRECTION('',(0.,0.,-1.));
#3427=VECTOR('',#3426,1.);
#3428=CARTESIAN_POINT('',(107.696,2.032,-3.59210244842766));
#3429=LINE('',#3428,#3427);
#3430=CARTESIAN_POINT('',(107.696,2.032,-3.59210244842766));
#3431=VERTEX_POINT('',#3430);
#3432=EDGE_CURVE('E879',#3431,#3423,#3429,.T.);
#3433=ORIENTED_EDGE('',*,*,#3432,.F.);
#3434=DIRECTION('',(0.,1.,0.));
#3435=VECTOR('',#3434,1.);
#3436=CARTESIAN_POINT('',(107.696,2.032,-3.59210244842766));
#3437=LINE('',#3436,#3435);
#3438=EDGE_CURVE('E890',#3431,#253,#3437,.T.);
#3439=ORIENTED_EDGE('',*,*,#3438,.T.);
#3440=EDGE_LOOP('',(#3417,#3425,#3433,#3439));
#3441=FACE_BOUND('',#3440,.T.);
#3442=ADVANCED_FACE('F1451',(#3441),#3416,.F.);
#3443=CARTESIAN_POINT('',(107.696,2.032,-3.59210244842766));
#3444=DIRECTION('',(0.,0.,-1.));
#3445=DIRECTION('',(-1.,0.,0.));
#3446=AXIS2_PLACEMENT_3D('',#3443,#3444,#3445);
#3447=PLANE('',#3446);
#3448=ORIENTED_EDGE('',*,*,#802,.F.);
#3449=ORIENTED_EDGE('',*,*,#3438,.F.);
#3450=DIRECTION('',(-1.,0.,0.));
#3451=VECTOR('',#3450,1.);
#3452=CARTESIAN_POINT('',(107.696,2.032,-3.59210244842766));
#3453=LINE('',#3452,#3451);
#3454=CARTESIAN_POINT('',(105.664,2.032,-3.59210244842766));
#3455=VERTEX_POINT('',#3454);
#3456=EDGE_CURVE('E887',#3431,#3455,#3453,.T.);
#3457=ORIENTED_EDGE('',*,*,#3456,.T.);
#3458=DIRECTION('',(0.,1.,0.));
#3459=VECTOR('',#3458,1.);
#3460=CARTESIAN_POINT('',(105.664,2.032,-3.59210244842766));
#3461=LINE('',#3460,#3459);
#3462=EDGE_CURVE('E893',#3455,#232,#3461,.T.);
#3463=ORIENTED_EDGE('',*,*,#3462,.T.);
#3464=EDGE_LOOP('',(#3448,#3449,#3457,#3463));
#3465=FACE_BOUND('',#3464,.T.);
#3466=ADVANCED_FACE('F1453',(#3465),#3447,.T.);
#3467=CARTESIAN_POINT('',(105.664,2.032,-31.4598975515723));
#3468=DIRECTION('',(-1.,0.,0.));
#3469=DIRECTION('',(0.,0.,1.));
#3470=AXIS2_PLACEMENT_3D('',#3467,#3468,#3469);
#3471=PLANE('',#3470);
#3472=ORIENTED_EDGE('',*,*,#241,.T.);
#3473=ORIENTED_EDGE('',*,*,#3462,.F.);
#3474=DIRECTION('',(0.,0.,1.));
#3475=VECTOR('',#3474,1.);
#3476=CARTESIAN_POINT('',(105.664,2.032,-31.4598975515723));
#3477=LINE('',#3476,#3475);
#3478=CARTESIAN_POINT('',(105.664,2.032,-31.4598975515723));
#3479=VERTEX_POINT('',#3478);
#3480=EDGE_CURVE('E884',#3479,#3455,#3477,.T.);
#3481=ORIENTED_EDGE('',*,*,#3480,.F.);
#3482=DIRECTION('',(0.,1.,0.));
#3483=VECTOR('',#3482,1.);
#3484=CARTESIAN_POINT('',(105.664,2.032,-31.4598975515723));
#3485=LINE('',#3484,#3483);
#3486=EDGE_CURVE('E896',#3479,#240,#3485,.T.);
#3487=ORIENTED_EDGE('',*,*,#3486,.T.);
#3488=EDGE_LOOP('',(#3472,#3473,#3481,#3487));
#3489=FACE_BOUND('',#3488,.T.);
#3490=ADVANCED_FACE('F1445',(#3489),#3471,.F.);
#3491=CARTESIAN_POINT('',(105.664,2.032,-31.4598975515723));
#3492=DIRECTION('',(0.,0.,1.));
#3493=DIRECTION('',(1.,0.,0.));
#3494=AXIS2_PLACEMENT_3D('',#3491,#3492,#3493);
#3495=PLANE('',#3494);
#3496=ORIENTED_EDGE('',*,*,#1041,.F.);
#3497=ORIENTED_EDGE('',*,*,#3486,.F.);
#3498=DIRECTION('',(1.,0.,0.));
#3499=VECTOR('',#3498,1.);
#3500=CARTESIAN_POINT('',(105.664,2.032,-31.4598975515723));
#3501=LINE('',#3500,#3499);
#3502=EDGE_CURVE('E882',#3479,#3423,#3501,.T.);
#3503=ORIENTED_EDGE('',*,*,#3502,.T.);
#3504=ORIENTED_EDGE('',*,*,#3424,.T.);
#3505=EDGE_LOOP('',(#3496,#3497,#3503,#3504));
#3506=FACE_BOUND('',#3505,.T.);
#3507=ADVANCED_FACE('F1441',(#3506),#3495,.T.);
#3508=CARTESIAN_POINT('',(107.696,2.032,-31.4598975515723));
#3509=DIRECTION('',(0.,-1.,0.));
#3510=DIRECTION('',(0.,0.,-1.));
#3511=AXIS2_PLACEMENT_3D('',#3508,#3509,#3510);
#3512=PLANE('',#3511);
#3513=ORIENTED_EDGE('',*,*,#3432,.T.);
#3514=ORIENTED_EDGE('',*,*,#3502,.F.);
#3515=ORIENTED_EDGE('',*,*,#3480,.T.);
#3516=ORIENTED_EDGE('',*,*,#3456,.F.);
#3517=EDGE_LOOP('',(#3513,#3514,#3515,#3516));
#3518=FACE_BOUND('',#3517,.T.);
#3519=ADVANCED_FACE('F1449',(#3518),#3512,.F.);
#3520=CARTESIAN_POINT('',(103.632,2.032,-3.59210244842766));
#3521=DIRECTION('',(1.,0.,0.));
#3522=DIRECTION('',(0.,0.,-1.));
#3523=AXIS2_PLACEMENT_3D('',#3520,#3521,#3522);
#3524=PLANE('',#3523);
#3525=ORIENTED_EDGE('',*,*,#229,.T.);
#3526=DIRECTION('',(0.,1.,0.));
#3527=VECTOR('',#3526,1.);
#3528=CARTESIAN_POINT('',(103.632,2.032,-31.4598975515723));
#3529=LINE('',#3528,#3527);
#3530=CARTESIAN_POINT('',(103.632,2.032,-31.4598975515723));
#3531=VERTEX_POINT('',#3530);
#3532=EDGE_CURVE('E858',#3531,#228,#3529,.T.);
#3533=ORIENTED_EDGE('',*,*,#3532,.F.);
#3534=DIRECTION('',(0.,0.,-1.));
#3535=VECTOR('',#3534,1.);
#3536=CARTESIAN_POINT('',(103.632,2.032,-3.59210244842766));
#3537=LINE('',#3536,#3535);
#3538=CARTESIAN_POINT('',(103.632,2.032,-3.59210244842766));
#3539=VERTEX_POINT('',#3538);
#3540=EDGE_CURVE('E848',#3539,#3531,#3537,.T.);
#3541=ORIENTED_EDGE('',*,*,#3540,.F.);
#3542=DIRECTION('',(0.,1.,0.));
#3543=VECTOR('',#3542,1.);
#3544=CARTESIAN_POINT('',(103.632,2.032,-3.59210244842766));
#3545=LINE('',#3544,#3543);
#3546=EDGE_CURVE('E859',#3539,#226,#3545,.T.);
#3547=ORIENTED_EDGE('',*,*,#3546,.T.);
#3548=EDGE_LOOP('',(#3525,#3533,#3541,#3547));
#3549=FACE_BOUND('',#3548,.T.);
#3550=ADVANCED_FACE('F2645',(#3549),#3524,.F.);
#3551=CARTESIAN_POINT('',(103.632,2.032,-3.59210244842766));
#3552=DIRECTION('',(0.,0.,-1.));
#3553=DIRECTION('',(-1.,0.,0.));
#3554=AXIS2_PLACEMENT_3D('',#3551,#3552,#3553);
#3555=PLANE('',#3554);
#3556=ORIENTED_EDGE('',*,*,#809,.F.);
#3557=ORIENTED_EDGE('',*,*,#3546,.F.);
#3558=DIRECTION('',(-1.,0.,0.));
#3559=VECTOR('',#3558,1.);
#3560=CARTESIAN_POINT('',(103.632,2.032,-3.59210244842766));
#3561=LINE('',#3560,#3559);
#3562=CARTESIAN_POINT('',(101.6,2.032,-3.59210244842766));
#3563=VERTEX_POINT('',#3562);
#3564=EDGE_CURVE('E856',#3539,#3563,#3561,.T.);
#3565=ORIENTED_EDGE('',*,*,#3564,.T.);
#3566=DIRECTION('',(0.,1.,0.));
#3567=VECTOR('',#3566,1.);
#3568=CARTESIAN_POINT('',(101.6,2.032,-3.59210244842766));
#3569=LINE('',#3568,#3567);
#3570=EDGE_CURVE('E862',#3563,#205,#3569,.T.);
#3571=ORIENTED_EDGE('',*,*,#3570,.T.);
#3572=EDGE_LOOP('',(#3556,#3557,#3565,#3571));
#3573=FACE_BOUND('',#3572,.T.);
#3574=ADVANCED_FACE('F2651',(#3573),#3555,.T.);
#3575=CARTESIAN_POINT('',(101.6,2.032,-31.4598975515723));
#3576=DIRECTION('',(-1.,0.,0.));
#3577=DIRECTION('',(0.,0.,1.));
#3578=AXIS2_PLACEMENT_3D('',#3575,#3576,#3577);
#3579=PLANE('',#3578);
#3580=ORIENTED_EDGE('',*,*,#214,.T.);
#3581=ORIENTED_EDGE('',*,*,#3570,.F.);
#3582=DIRECTION('',(0.,0.,1.));
#3583=VECTOR('',#3582,1.);
#3584=CARTESIAN_POINT('',(101.6,2.032,-31.4598975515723));
#3585=LINE('',#3584,#3583);
#3586=CARTESIAN_POINT('',(101.6,2.032,-31.4598975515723));
#3587=VERTEX_POINT('',#3586);
#3588=EDGE_CURVE('E853',#3587,#3563,#3585,.T.);
#3589=ORIENTED_EDGE('',*,*,#3588,.F.);
#3590=DIRECTION('',(0.,1.,0.));
#3591=VECTOR('',#3590,1.);
#3592=CARTESIAN_POINT('',(101.6,2.032,-31.4598975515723));
#3593=LINE('',#3592,#3591);
#3594=EDGE_CURVE('E865',#3587,#213,#3593,.T.);
#3595=ORIENTED_EDGE('',*,*,#3594,.T.);
#3596=EDGE_LOOP('',(#3580,#3581,#3589,#3595));
#3597=FACE_BOUND('',#3596,.T.);
#3598=ADVANCED_FACE('F2658',(#3597),#3579,.F.);
#3599=CARTESIAN_POINT('',(101.6,2.032,-31.4598975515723));
#3600=DIRECTION('',(0.,0.,1.));
#3601=DIRECTION('',(1.,0.,0.));
#3602=AXIS2_PLACEMENT_3D('',#3599,#3600,#3601);
#3603=PLANE('',#3602);
#3604=ORIENTED_EDGE('',*,*,#1034,.F.);
#3605=ORIENTED_EDGE('',*,*,#3594,.F.);
#3606=DIRECTION('',(1.,0.,0.));
#3607=VECTOR('',#3606,1.);
#3608=CARTESIAN_POINT('',(101.6,2.032,-31.4598975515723));
#3609=LINE('',#3608,#3607);
#3610=EDGE_CURVE('E851',#3587,#3531,#3609,.T.);
#3611=ORIENTED_EDGE('',*,*,#3610,.T.);
#3612=ORIENTED_EDGE('',*,*,#3532,.T.);
#3613=EDGE_LOOP('',(#3604,#3605,#3611,#3612));
#3614=FACE_BOUND('',#3613,.T.);
#3615=ADVANCED_FACE('F2666',(#3614),#3603,.T.);
#3616=CARTESIAN_POINT('',(103.632,2.032,-31.4598975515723));
#3617=DIRECTION('',(0.,-1.,0.));
#3618=DIRECTION('',(0.,0.,-1.));
#3619=AXIS2_PLACEMENT_3D('',#3616,#3617,#3618);
#3620=PLANE('',#3619);
#3621=ORIENTED_EDGE('',*,*,#3540,.T.);
#3622=ORIENTED_EDGE('',*,*,#3610,.F.);
#3623=ORIENTED_EDGE('',*,*,#3588,.T.);
#3624=ORIENTED_EDGE('',*,*,#3564,.F.);
#3625=EDGE_LOOP('',(#3621,#3622,#3623,#3624));
#3626=FACE_BOUND('',#3625,.T.);
#3627=ADVANCED_FACE('F2674',(#3626),#3620,.F.);
#3628=CARTESIAN_POINT('',(99.568,2.032,-3.59210244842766));
#3629=DIRECTION('',(1.,0.,0.));
#3630=DIRECTION('',(0.,0.,-1.));
#3631=AXIS2_PLACEMENT_3D('',#3628,#3629,#3630);
#3632=PLANE('',#3631);
#3633=ORIENTED_EDGE('',*,*,#202,.T.);
#3634=DIRECTION('',(0.,1.,0.));
#3635=VECTOR('',#3634,1.);
#3636=CARTESIAN_POINT('',(99.568,2.032,-31.4598975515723));
#3637=LINE('',#3636,#3635);
#3638=CARTESIAN_POINT('',(99.568,2.032,-31.4598975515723));
#3639=VERTEX_POINT('',#3638);
#3640=EDGE_CURVE('E827',#3639,#201,#3637,.T.);
#3641=ORIENTED_EDGE('',*,*,#3640,.F.);
#3642=DIRECTION('',(0.,0.,-1.));
#3643=VECTOR('',#3642,1.);
#3644=CARTESIAN_POINT('',(99.568,2.032,-3.59210244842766));
#3645=LINE('',#3644,#3643);
#3646=CARTESIAN_POINT('',(99.568,2.032,-3.59210244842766));
#3647=VERTEX_POINT('',#3646);
#3648=EDGE_CURVE('E817',#3647,#3639,#3645,.T.);
#3649=ORIENTED_EDGE('',*,*,#3648,.F.);
#3650=DIRECTION('',(0.,1.,0.));
#3651=VECTOR('',#3650,1.);
#3652=CARTESIAN_POINT('',(99.568,2.032,-3.59210244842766));
#3653=LINE('',#3652,#3651);
#3654=EDGE_CURVE('E828',#3647,#199,#3653,.T.);
#3655=ORIENTED_EDGE('',*,*,#3654,.T.);
#3656=EDGE_LOOP('',(#3633,#3641,#3649,#3655));
#3657=FACE_BOUND('',#3656,.T.);
#3658=ADVANCED_FACE('F2682',(#3657),#3632,.F.);
#3659=CARTESIAN_POINT('',(99.568,2.032,-3.59210244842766));
#3660=DIRECTION('',(0.,0.,-1.));
#3661=DIRECTION('',(-1.,0.,0.));
#3662=AXIS2_PLACEMENT_3D('',#3659,#3660,#3661);
#3663=PLANE('',#3662);
#3664=ORIENTED_EDGE('',*,*,#816,.F.);
#3665=ORIENTED_EDGE('',*,*,#3654,.F.);
#3666=DIRECTION('',(-1.,0.,0.));
#3667=VECTOR('',#3666,1.);
#3668=CARTESIAN_POINT('',(99.568,2.032,-3.59210244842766));
#3669=LINE('',#3668,#3667);
#3670=CARTESIAN_POINT('',(97.536,2.032,-3.59210244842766));
#3671=VERTEX_POINT('',#3670);
#3672=EDGE_CURVE('E825',#3647,#3671,#3669,.T.);
#3673=ORIENTED_EDGE('',*,*,#3672,.T.);
#3674=DIRECTION('',(0.,1.,0.));
#3675=VECTOR('',#3674,1.);
#3676=CARTESIAN_POINT('',(97.536,2.032,-3.59210244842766));
#3677=LINE('',#3676,#3675);
#3678=EDGE_CURVE('E831',#3671,#178,#3677,.T.);
#3679=ORIENTED_EDGE('',*,*,#3678,.T.);
#3680=EDGE_LOOP('',(#3664,#3665,#3673,#3679));
#3681=FACE_BOUND('',#3680,.T.);
#3682=ADVANCED_FACE('F2690',(#3681),#3663,.T.);
#3683=CARTESIAN_POINT('',(97.536,2.032,-31.4598975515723));
#3684=DIRECTION('',(-1.,0.,0.));
#3685=DIRECTION('',(0.,0.,1.));
#3686=AXIS2_PLACEMENT_3D('',#3683,#3684,#3685);
#3687=PLANE('',#3686);
#3688=ORIENTED_EDGE('',*,*,#187,.T.);
#3689=ORIENTED_EDGE('',*,*,#3678,.F.);
#3690=DIRECTION('',(0.,0.,1.));
#3691=VECTOR('',#3690,1.);
#3692=CARTESIAN_POINT('',(97.536,2.032,-31.4598975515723));
#3693=LINE('',#3692,#3691);
#3694=CARTESIAN_POINT('',(97.536,2.032,-31.4598975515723));
#3695=VERTEX_POINT('',#3694);
#3696=EDGE_CURVE('E822',#3695,#3671,#3693,.T.);
#3697=ORIENTED_EDGE('',*,*,#3696,.F.);
#3698=DIRECTION('',(0.,1.,0.));
#3699=VECTOR('',#3698,1.);
#3700=CARTESIAN_POINT('',(97.536,2.032,-31.4598975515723));
#3701=LINE('',#3700,#3699);
#3702=EDGE_CURVE('E834',#3695,#186,#3701,.T.);
#3703=ORIENTED_EDGE('',*,*,#3702,.T.);
#3704=EDGE_LOOP('',(#3688,#3689,#3697,#3703));
#3705=FACE_BOUND('',#3704,.T.);
#3706=ADVANCED_FACE('F2698',(#3705),#3687,.F.);
#3707=CARTESIAN_POINT('',(97.536,2.032,-31.4598975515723));
#3708=DIRECTION('',(0.,0.,1.));
#3709=DIRECTION('',(1.,0.,0.));
#3710=AXIS2_PLACEMENT_3D('',#3707,#3708,#3709);
#3711=PLANE('',#3710);
#3712=ORIENTED_EDGE('',*,*,#1027,.F.);
#3713=ORIENTED_EDGE('',*,*,#3702,.F.);
#3714=DIRECTION('',(1.,0.,0.));
#3715=VECTOR('',#3714,1.);
#3716=CARTESIAN_POINT('',(97.536,2.032,-31.4598975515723));
#3717=LINE('',#3716,#3715);
#3718=EDGE_CURVE('E820',#3695,#3639,#3717,.T.);
#3719=ORIENTED_EDGE('',*,*,#3718,.T.);
#3720=ORIENTED_EDGE('',*,*,#3640,.T.);
#3721=EDGE_LOOP('',(#3712,#3713,#3719,#3720));
#3722=FACE_BOUND('',#3721,.T.);
#3723=ADVANCED_FACE('F2706',(#3722),#3711,.T.);
#3724=CARTESIAN_POINT('',(99.568,2.032,-31.4598975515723));
#3725=DIRECTION('',(0.,-1.,0.));
#3726=DIRECTION('',(0.,0.,-1.));
#3727=AXIS2_PLACEMENT_3D('',#3724,#3725,#3726);
#3728=PLANE('',#3727);
#3729=ORIENTED_EDGE('',*,*,#3648,.T.);
#3730=ORIENTED_EDGE('',*,*,#3718,.F.);
#3731=ORIENTED_EDGE('',*,*,#3696,.T.);
#3732=ORIENTED_EDGE('',*,*,#3672,.F.);
#3733=EDGE_LOOP('',(#3729,#3730,#3731,#3732));
#3734=FACE_BOUND('',#3733,.T.);
#3735=ADVANCED_FACE('F2714',(#3734),#3728,.F.);
#3736=CARTESIAN_POINT('',(95.504,2.032,-3.59210244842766));
#3737=DIRECTION('',(1.,0.,0.));
#3738=DIRECTION('',(0.,0.,-1.));
#3739=AXIS2_PLACEMENT_3D('',#3736,#3737,#3738);
#3740=PLANE('',#3739);
#3741=ORIENTED_EDGE('',*,*,#175,.T.);
#3742=DIRECTION('',(0.,1.,0.));
#3743=VECTOR('',#3742,1.);
#3744=CARTESIAN_POINT('',(95.504,2.032,-31.4598975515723));
#3745=LINE('',#3744,#3743);
#3746=CARTESIAN_POINT('',(95.504,2.032,-31.4598975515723));
#3747=VERTEX_POINT('',#3746);
#3748=EDGE_CURVE('E796',#3747,#174,#3745,.T.);
#3749=ORIENTED_EDGE('',*,*,#3748,.F.);
#3750=DIRECTION('',(0.,0.,-1.));
#3751=VECTOR('',#3750,1.);
#3752=CARTESIAN_POINT('',(95.504,2.032,-3.59210244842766));
#3753=LINE('',#3752,#3751);
#3754=CARTESIAN_POINT('',(95.504,2.032,-3.59210244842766));
#3755=VERTEX_POINT('',#3754);
#3756=EDGE_CURVE('E786',#3755,#3747,#3753,.T.);
#3757=ORIENTED_EDGE('',*,*,#3756,.F.);
#3758=DIRECTION('',(0.,1.,0.));
#3759=VECTOR('',#3758,1.);
#3760=CARTESIAN_POINT('',(95.504,2.032,-3.59210244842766));
#3761=LINE('',#3760,#3759);
#3762=EDGE_CURVE('E797',#3755,#172,#3761,.T.);
#3763=ORIENTED_EDGE('',*,*,#3762,.T.);
#3764=EDGE_LOOP('',(#3741,#3749,#3757,#3763));
#3765=FACE_BOUND('',#3764,.T.);
#3766=ADVANCED_FACE('F2722',(#3765),#3740,.F.);
#3767=CARTESIAN_POINT('',(95.504,2.032,-3.59210244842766));
#3768=DIRECTION('',(0.,0.,-1.));
#3769=DIRECTION('',(-1.,0.,0.));
#3770=AXIS2_PLACEMENT_3D('',#3767,#3768,#3769);
#3771=PLANE('',#3770);
#3772=ORIENTED_EDGE('',*,*,#823,.F.);
#3773=ORIENTED_EDGE('',*,*,#3762,.F.);
#3774=DIRECTION('',(-1.,0.,0.));
#3775=VECTOR('',#3774,1.);
#3776=CARTESIAN_POINT('',(95.504,2.032,-3.59210244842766));
#3777=LINE('',#3776,#3775);
#3778=CARTESIAN_POINT('',(93.472,2.032,-3.59210244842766));
#3779=VERTEX_POINT('',#3778);
#3780=EDGE_CURVE('E794',#3755,#3779,#3777,.T.);
#3781=ORIENTED_EDGE('',*,*,#3780,.T.);
#3782=DIRECTION('',(0.,1.,0.));
#3783=VECTOR('',#3782,1.);
#3784=CARTESIAN_POINT('',(93.472,2.032,-3.59210244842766));
#3785=LINE('',#3784,#3783);
#3786=EDGE_CURVE('E800',#3779,#151,#3785,.T.);
#3787=ORIENTED_EDGE('',*,*,#3786,.T.);
#3788=EDGE_LOOP('',(#3772,#3773,#3781,#3787));
#3789=FACE_BOUND('',#3788,.T.);
#3790=ADVANCED_FACE('F2730',(#3789),#3771,.T.);
#3791=CARTESIAN_POINT('',(93.472,2.032,-31.4598975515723));
#3792=DIRECTION('',(-1.,0.,0.));
#3793=DIRECTION('',(0.,0.,1.));
#3794=AXIS2_PLACEMENT_3D('',#3791,#3792,#3793);
#3795=PLANE('',#3794);
#3796=ORIENTED_EDGE('',*,*,#160,.T.);
#3797=ORIENTED_EDGE('',*,*,#3786,.F.);
#3798=DIRECTION('',(0.,0.,1.));
#3799=VECTOR('',#3798,1.);
#3800=CARTESIAN_POINT('',(93.472,2.032,-31.4598975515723));
#3801=LINE('',#3800,#3799);
#3802=CARTESIAN_POINT('',(93.472,2.032,-31.4598975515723));
#3803=VERTEX_POINT('',#3802);
#3804=EDGE_CURVE('E791',#3803,#3779,#3801,.T.);
#3805=ORIENTED_EDGE('',*,*,#3804,.F.);
#3806=DIRECTION('',(0.,1.,0.));
#3807=VECTOR('',#3806,1.);
#3808=CARTESIAN_POINT('',(93.472,2.032,-31.4598975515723));
#3809=LINE('',#3808,#3807);
#3810=EDGE_CURVE('E803',#3803,#159,#3809,.T.);
#3811=ORIENTED_EDGE('',*,*,#3810,.T.);
#3812=EDGE_LOOP('',(#3796,#3797,#3805,#3811));
#3813=FACE_BOUND('',#3812,.T.);
#3814=ADVANCED_FACE('F2738',(#3813),#3795,.F.);
#3815=CARTESIAN_POINT('',(93.472,2.032,-31.4598975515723));
#3816=DIRECTION('',(0.,0.,1.));
#3817=DIRECTION('',(1.,0.,0.));
#3818=AXIS2_PLACEMENT_3D('',#3815,#3816,#3817);
#3819=PLANE('',#3818);
#3820=ORIENTED_EDGE('',*,*,#1020,.F.);
#3821=ORIENTED_EDGE('',*,*,#3810,.F.);
#3822=DIRECTION('',(1.,0.,0.));
#3823=VECTOR('',#3822,1.);
#3824=CARTESIAN_POINT('',(93.472,2.032,-31.4598975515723));
#3825=LINE('',#3824,#3823);
#3826=EDGE_CURVE('E789',#3803,#3747,#3825,.T.);
#3827=ORIENTED_EDGE('',*,*,#3826,.T.);
#3828=ORIENTED_EDGE('',*,*,#3748,.T.);
#3829=EDGE_LOOP('',(#3820,#3821,#3827,#3828));
#3830=FACE_BOUND('',#3829,.T.);
#3831=ADVANCED_FACE('F2746',(#3830),#3819,.T.);
#3832=CARTESIAN_POINT('',(95.504,2.032,-31.4598975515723));
#3833=DIRECTION('',(0.,-1.,0.));
#3834=DIRECTION('',(0.,0.,-1.));
#3835=AXIS2_PLACEMENT_3D('',#3832,#3833,#3834);
#3836=PLANE('',#3835);
#3837=ORIENTED_EDGE('',*,*,#3756,.T.);
#3838=ORIENTED_EDGE('',*,*,#3826,.F.);
#3839=ORIENTED_EDGE('',*,*,#3804,.T.);
#3840=ORIENTED_EDGE('',*,*,#3780,.F.);
#3841=EDGE_LOOP('',(#3837,#3838,#3839,#3840));
#3842=FACE_BOUND('',#3841,.T.);
#3843=ADVANCED_FACE('F2754',(#3842),#3836,.F.);
#3844=CARTESIAN_POINT('',(91.44,2.032,-3.59210244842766));
#3845=DIRECTION('',(1.,0.,0.));
#3846=DIRECTION('',(0.,0.,-1.));
#3847=AXIS2_PLACEMENT_3D('',#3844,#3845,#3846);
#3848=PLANE('',#3847);
#3849=ORIENTED_EDGE('',*,*,#148,.T.);
#3850=DIRECTION('',(0.,1.,0.));
#3851=VECTOR('',#3850,1.);
#3852=CARTESIAN_POINT('',(91.44,2.032,-31.4598975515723));
#3853=LINE('',#3852,#3851);
#3854=CARTESIAN_POINT('',(91.44,2.032,-31.4598975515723));
#3855=VERTEX_POINT('',#3854);
#3856=EDGE_CURVE('E770',#3855,#147,#3853,.T.);
#3857=ORIENTED_EDGE('',*,*,#3856,.F.);
#3858=DIRECTION('',(0.,0.,-1.));
#3859=VECTOR('',#3858,1.);
#3860=CARTESIAN_POINT('',(91.44,2.032,-3.59210244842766));
#3861=LINE('',#3860,#3859);
#3862=CARTESIAN_POINT('',(91.44,2.032,-3.59210244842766));
#3863=VERTEX_POINT('',#3862);
#3864=EDGE_CURVE('E760',#3863,#3855,#3861,.T.);
#3865=ORIENTED_EDGE('',*,*,#3864,.F.);
#3866=DIRECTION('',(0.,1.,0.));
#3867=VECTOR('',#3866,1.);
#3868=CARTESIAN_POINT('',(91.44,2.032,-3.59210244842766));
#3869=LINE('',#3868,#3867);
#3870=EDGE_CURVE('E771',#3863,#145,#3869,.T.);
#3871=ORIENTED_EDGE('',*,*,#3870,.T.);
#3872=EDGE_LOOP('',(#3849,#3857,#3865,#3871));
#3873=FACE_BOUND('',#3872,.T.);
#3874=ADVANCED_FACE('F2762',(#3873),#3848,.F.);
#3875=CARTESIAN_POINT('',(91.44,2.032,-3.59210244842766));
#3876=DIRECTION('',(0.,0.,-1.));
#3877=DIRECTION('',(-1.,0.,0.));
#3878=AXIS2_PLACEMENT_3D('',#3875,#3876,#3877);
#3879=PLANE('',#3878);
#3880=ORIENTED_EDGE('',*,*,#830,.F.);
#3881=ORIENTED_EDGE('',*,*,#3870,.F.);
#3882=DIRECTION('',(-1.,0.,0.));
#3883=VECTOR('',#3882,1.);
#3884=CARTESIAN_POINT('',(91.44,2.032,-3.59210244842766));
#3885=LINE('',#3884,#3883);
#3886=CARTESIAN_POINT('',(89.408,2.032,-3.59210244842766));
#3887=VERTEX_POINT('',#3886);
#3888=EDGE_CURVE('E768',#3863,#3887,#3885,.T.);
#3889=ORIENTED_EDGE('',*,*,#3888,.T.);
#3890=DIRECTION('',(0.,1.,0.));
#3891=VECTOR('',#3890,1.);
#3892=CARTESIAN_POINT('',(89.408,2.032,-3.59210244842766));
#3893=LINE('',#3892,#3891);
#3894=EDGE_CURVE('E774',#3887,#39,#3893,.T.);
#3895=ORIENTED_EDGE('',*,*,#3894,.T.);
#3896=EDGE_LOOP('',(#3880,#3881,#3889,#3895));
#3897=FACE_BOUND('',#3896,.T.);
#3898=ADVANCED_FACE('F2770',(#3897),#3879,.T.);
#3899=CARTESIAN_POINT('',(89.408,2.032,-31.4598975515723));
#3900=DIRECTION('',(-1.,0.,0.));
#3901=DIRECTION('',(0.,0.,1.));
#3902=AXIS2_PLACEMENT_3D('',#3899,#3900,#3901);
#3903=PLANE('',#3902);
#3904=ORIENTED_EDGE('',*,*,#48,.T.);
#3905=ORIENTED_EDGE('',*,*,#3894,.F.);
#3906=DIRECTION('',(0.,0.,1.));
#3907=VECTOR('',#3906,1.);
#3908=CARTESIAN_POINT('',(89.408,2.032,-31.4598975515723));
#3909=LINE('',#3908,#3907);
#3910=CARTESIAN_POINT('',(89.408,2.032,-31.4598975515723));
#3911=VERTEX_POINT('',#3910);
#3912=EDGE_CURVE('E765',#3911,#3887,#3909,.T.);
#3913=ORIENTED_EDGE('',*,*,#3912,.F.);
#3914=DIRECTION('',(0.,1.,0.));
#3915=VECTOR('',#3914,1.);
#3916=CARTESIAN_POINT('',(89.408,2.032,-31.4598975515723));
#3917=LINE('',#3916,#3915);
#3918=EDGE_CURVE('E777',#3911,#47,#3917,.T.);
#3919=ORIENTED_EDGE('',*,*,#3918,.T.);
#3920=EDGE_LOOP('',(#3904,#3905,#3913,#3919));
#3921=FACE_BOUND('',#3920,.T.);
#3922=ADVANCED_FACE('F2778',(#3921),#3903,.F.);
#3923=CARTESIAN_POINT('',(89.408,2.032,-31.4598975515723));
#3924=DIRECTION('',(0.,0.,1.));
#3925=DIRECTION('',(1.,0.,0.));
#3926=AXIS2_PLACEMENT_3D('',#3923,#3924,#3925);
#3927=PLANE('',#3926);
#3928=ORIENTED_EDGE('',*,*,#1013,.F.);
#3929=ORIENTED_EDGE('',*,*,#3918,.F.);
#3930=DIRECTION('',(1.,0.,0.));
#3931=VECTOR('',#3930,1.);
#3932=CARTESIAN_POINT('',(89.408,2.032,-31.4598975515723));
#3933=LINE('',#3932,#3931);
#3934=EDGE_CURVE('E763',#3911,#3855,#3933,.T.);
#3935=ORIENTED_EDGE('',*,*,#3934,.T.);
#3936=ORIENTED_EDGE('',*,*,#3856,.T.);
#3937=EDGE_LOOP('',(#3928,#3929,#3935,#3936));
#3938=FACE_BOUND('',#3937,.T.);
#3939=ADVANCED_FACE('F2786',(#3938),#3927,.T.);
#3940=CARTESIAN_POINT('',(91.44,2.032,-31.4598975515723));
#3941=DIRECTION('',(0.,-1.,0.));
#3942=DIRECTION('',(0.,0.,-1.));
#3943=AXIS2_PLACEMENT_3D('',#3940,#3941,#3942);
#3944=PLANE('',#3943);
#3945=ORIENTED_EDGE('',*,*,#3864,.T.);
#3946=ORIENTED_EDGE('',*,*,#3934,.F.);
#3947=ORIENTED_EDGE('',*,*,#3912,.T.);
#3948=ORIENTED_EDGE('',*,*,#3888,.F.);
#3949=EDGE_LOOP('',(#3945,#3946,#3947,#3948));
#3950=FACE_BOUND('',#3949,.T.);
#3951=ADVANCED_FACE('F2794',(#3950),#3944,.F.);
#3952=CARTESIAN_POINT('',(10.287,2.032,-3.59210244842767));
#3953=DIRECTION('',(1.,0.,0.));
#3954=DIRECTION('',(0.,0.,-1.));
#3955=AXIS2_PLACEMENT_3D('',#3952,#3953,#3954);
#3956=PLANE('',#3955);
#3957=ORIENTED_EDGE('',*,*,#133,.T.);
#3958=DIRECTION('',(0.,1.,0.));
#3959=VECTOR('',#3958,1.);
#3960=CARTESIAN_POINT('',(10.287,2.032,-31.4598975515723));
#3961=LINE('',#3960,#3959);
#3962=CARTESIAN_POINT('',(10.287,2.032,-31.4598975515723));
#3963=VERTEX_POINT('',#3962);
#3964=EDGE_CURVE('E1226',#3963,#124,#3961,.T.);
#3965=ORIENTED_EDGE('',*,*,#3964,.F.);
#3966=DIRECTION('',(0.,0.,-1.));
#3967=VECTOR('',#3966,1.);
#3968=CARTESIAN_POINT('',(10.287,2.032,-3.59210244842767));
#3969=LINE('',#3968,#3967);
#3970=CARTESIAN_POINT('',(10.287,2.032,-3.59210244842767));
#3971=VERTEX_POINT('',#3970);
#3972=EDGE_CURVE('E1248',#3971,#3963,#3969,.T.);
#3973=ORIENTED_EDGE('',*,*,#3972,.F.);
#3974=DIRECTION('',(0.,1.,0.));
#3975=VECTOR('',#3974,1.);
#3976=CARTESIAN_POINT('',(10.287,2.032,-3.59210244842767));
#3977=LINE('',#3976,#3975);
#3978=EDGE_CURVE('E754',#3971,#132,#3977,.T.);
#3979=ORIENTED_EDGE('',*,*,#3978,.T.);
#3980=EDGE_LOOP('',(#3957,#3965,#3973,#3979));
#3981=FACE_BOUND('',#3980,.T.);
#3982=ADVANCED_FACE('F1224',(#3981),#3956,.F.);
#3983=CARTESIAN_POINT('',(10.287,2.032,-3.59210244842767));
#3984=DIRECTION('',(0.,0.,-1.));
#3985=DIRECTION('',(-1.,0.,0.));
#3986=AXIS2_PLACEMENT_3D('',#3983,#3984,#3985);
#3987=PLANE('',#3986);
#3988=ORIENTED_EDGE('',*,*,#858,.F.);
#3989=ORIENTED_EDGE('',*,*,#3978,.F.);
#3990=DIRECTION('',(-1.,0.,0.));
#3991=VECTOR('',#3990,1.);
#3992=CARTESIAN_POINT('',(10.287,2.032,-3.59210244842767));
#3993=LINE('',#3992,#3991);
#3994=CARTESIAN_POINT('',(8.255,2.032,-3.59210244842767));
#3995=VERTEX_POINT('',#3994);
#3996=EDGE_CURVE('E1238',#3971,#3995,#3993,.T.);
#3997=ORIENTED_EDGE('',*,*,#3996,.T.);
#3998=DIRECTION('',(0.,1.,0.));
#3999=VECTOR('',#3998,1.);
#4000=CARTESIAN_POINT('',(8.255,2.032,-3.59210244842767));
#4001=LINE('',#4000,#3999);
#4002=EDGE_CURVE('E1256',#3995,#732,#4001,.T.);
#4003=ORIENTED_EDGE('',*,*,#4002,.T.);
#4004=EDGE_LOOP('',(#3988,#3989,#3997,#4003));
#4005=FACE_BOUND('',#4004,.T.);
#4006=ADVANCED_FACE('F1266',(#4005),#3987,.T.);
#4007=CARTESIAN_POINT('',(8.255,2.032,-31.4598975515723));
#4008=DIRECTION('',(-1.,0.,0.));
#4009=DIRECTION('',(0.,0.,1.));
#4010=AXIS2_PLACEMENT_3D('',#4007,#4008,#4009);
#4011=PLANE('',#4010);
#4012=ORIENTED_EDGE('',*,*,#733,.T.);
#4013=ORIENTED_EDGE('',*,*,#4002,.F.);
#4014=DIRECTION('',(0.,0.,1.));
#4015=VECTOR('',#4014,1.);
#4016=CARTESIAN_POINT('',(8.255,2.032,-31.4598975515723));
#4017=LINE('',#4016,#4015);
#4018=CARTESIAN_POINT('',(8.255,2.032,-31.4598975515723));
#4019=VERTEX_POINT('',#4018);
#4020=EDGE_CURVE('E1251',#4019,#3995,#4017,.T.);
#4021=ORIENTED_EDGE('',*,*,#4020,.F.);
#4022=DIRECTION('',(0.,1.,0.));
#4023=VECTOR('',#4022,1.);
#4024=CARTESIAN_POINT('',(8.255,2.032,-31.4598975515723));
#4025=LINE('',#4024,#4023);
#4026=EDGE_CURVE('E1237',#4019,#730,#4025,.T.);
#4027=ORIENTED_EDGE('',*,*,#4026,.T.);
#4028=EDGE_LOOP('',(#4012,#4013,#4021,#4027));
#4029=FACE_BOUND('',#4028,.T.);
#4030=ADVANCED_FACE('F1260',(#4029),#4011,.F.);
#4031=CARTESIAN_POINT('',(8.255,2.032,-31.4598975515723));
#4032=DIRECTION('',(0.,0.,1.));
#4033=DIRECTION('',(1.,0.,0.));
#4034=AXIS2_PLACEMENT_3D('',#4031,#4032,#4033);
#4035=PLANE('',#4034);
#4036=ORIENTED_EDGE('',*,*,#985,.F.);
#4037=ORIENTED_EDGE('',*,*,#4026,.F.);
#4038=DIRECTION('',(1.,0.,0.));
#4039=VECTOR('',#4038,1.);
#4040=CARTESIAN_POINT('',(8.255,2.032,-31.4598975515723));
#4041=LINE('',#4040,#4039);
#4042=EDGE_CURVE('E1236',#4019,#3963,#4041,.T.);
#4043=ORIENTED_EDGE('',*,*,#4042,.T.);
#4044=ORIENTED_EDGE('',*,*,#3964,.T.);
#4045=EDGE_LOOP('',(#4036,#4037,#4043,#4044));
#4046=FACE_BOUND('',#4045,.T.);
#4047=ADVANCED_FACE('F1234',(#4046),#4035,.T.);
#4048=CARTESIAN_POINT('',(10.287,2.032,-31.4598975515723));
#4049=DIRECTION('',(0.,-1.,0.));
#4050=DIRECTION('',(0.,0.,-1.));
#4051=AXIS2_PLACEMENT_3D('',#4048,#4049,#4050);
#4052=PLANE('',#4051);
#4053=ORIENTED_EDGE('',*,*,#3972,.T.);
#4054=ORIENTED_EDGE('',*,*,#4042,.F.);
#4055=ORIENTED_EDGE('',*,*,#4020,.T.);
#4056=ORIENTED_EDGE('',*,*,#3996,.F.);
#4057=EDGE_LOOP('',(#4053,#4054,#4055,#4056));
#4058=FACE_BOUND('',#4057,.T.);
#4059=ADVANCED_FACE('F1263',(#4058),#4052,.F.);
#4060=CARTESIAN_POINT('',(14.351,2.032,-3.59210244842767));
#4061=DIRECTION('',(1.,0.,0.));
#4062=DIRECTION('',(0.,0.,-1.));
#4063=AXIS2_PLACEMENT_3D('',#4060,#4061,#4062);
#4064=PLANE('',#4063);
#4065=ORIENTED_EDGE('',*,*,#106,.T.);
#4066=DIRECTION('',(0.,1.,0.));
#4067=VECTOR('',#4066,1.);
#4068=CARTESIAN_POINT('',(14.351,2.032,-31.4598975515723));
#4069=LINE('',#4068,#4067);
#4070=CARTESIAN_POINT('',(14.351,2.032,-31.4598975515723));
#4071=VERTEX_POINT('',#4070);
#4072=EDGE_CURVE('E1357',#4071,#97,#4069,.T.);
#4073=ORIENTED_EDGE('',*,*,#4072,.F.);
#4074=DIRECTION('',(0.,0.,-1.));
#4075=VECTOR('',#4074,1.);
#4076=CARTESIAN_POINT('',(14.351,2.032,-3.59210244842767));
#4077=LINE('',#4076,#4075);
#4078=CARTESIAN_POINT('',(14.351,2.032,-3.59210244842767));
#4079=VERTEX_POINT('',#4078);
#4080=EDGE_CURVE('E1347',#4079,#4071,#4077,.T.);
#4081=ORIENTED_EDGE('',*,*,#4080,.F.);
#4082=DIRECTION('',(0.,1.,0.));
#4083=VECTOR('',#4082,1.);
#4084=CARTESIAN_POINT('',(14.351,2.032,-3.59210244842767));
#4085=LINE('',#4084,#4083);
#4086=EDGE_CURVE('E1230',#4079,#105,#4085,.T.);
#4087=ORIENTED_EDGE('',*,*,#4086,.T.);
#4088=EDGE_LOOP('',(#4065,#4073,#4081,#4087));
#4089=FACE_BOUND('',#4088,.T.);
#4090=ADVANCED_FACE('F1370',(#4089),#4064,.F.);
#4091=CARTESIAN_POINT('',(14.351,2.032,-3.59210244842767));
#4092=DIRECTION('',(0.,0.,-1.));
#4093=DIRECTION('',(-1.,0.,0.));
#4094=AXIS2_PLACEMENT_3D('',#4091,#4092,#4093);
#4095=PLANE('',#4094);
#4096=ORIENTED_EDGE('',*,*,#851,.F.);
#4097=ORIENTED_EDGE('',*,*,#4086,.F.);
#4098=DIRECTION('',(-1.,0.,0.));
#4099=VECTOR('',#4098,1.);
#4100=CARTESIAN_POINT('',(14.351,2.032,-3.59210244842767));
#4101=LINE('',#4100,#4099);
#4102=CARTESIAN_POINT('',(12.319,2.032,-3.59210244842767));
#4103=VERTEX_POINT('',#4102);
#4104=EDGE_CURVE('E1355',#4079,#4103,#4101,.T.);
#4105=ORIENTED_EDGE('',*,*,#4104,.T.);
#4106=DIRECTION('',(0.,1.,0.));
#4107=VECTOR('',#4106,1.);
#4108=CARTESIAN_POINT('',(12.319,2.032,-3.59210244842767));
#4109=LINE('',#4108,#4107);
#4110=EDGE_CURVE('E1359',#4103,#120,#4109,.T.);
#4111=ORIENTED_EDGE('',*,*,#4110,.T.);
#4112=EDGE_LOOP('',(#4096,#4097,#4105,#4111));
#4113=FACE_BOUND('',#4112,.T.);
#4114=ADVANCED_FACE('F1373',(#4113),#4095,.T.);
#4115=CARTESIAN_POINT('',(12.319,2.032,-31.4598975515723));
#4116=DIRECTION('',(-1.,0.,0.));
#4117=DIRECTION('',(0.,0.,1.));
#4118=AXIS2_PLACEMENT_3D('',#4115,#4116,#4117);
#4119=PLANE('',#4118);
#4120=ORIENTED_EDGE('',*,*,#121,.T.);
#4121=ORIENTED_EDGE('',*,*,#4110,.F.);
#4122=DIRECTION('',(0.,0.,1.));
#4123=VECTOR('',#4122,1.);
#4124=CARTESIAN_POINT('',(12.319,2.032,-31.4598975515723));
#4125=LINE('',#4124,#4123);
#4126=CARTESIAN_POINT('',(12.319,2.032,-31.4598975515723));
#4127=VERTEX_POINT('',#4126);
#4128=EDGE_CURVE('E1352',#4127,#4103,#4125,.T.);
#4129=ORIENTED_EDGE('',*,*,#4128,.F.);
#4130=DIRECTION('',(0.,1.,0.));
#4131=VECTOR('',#4130,1.);
#4132=CARTESIAN_POINT('',(12.319,2.032,-31.4598975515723));
#4133=LINE('',#4132,#4131);
#4134=EDGE_CURVE('E1361',#4127,#118,#4133,.T.);
#4135=ORIENTED_EDGE('',*,*,#4134,.T.);
#4136=EDGE_LOOP('',(#4120,#4121,#4129,#4135));
#4137=FACE_BOUND('',#4136,.T.);
#4138=ADVANCED_FACE('F1377',(#4137),#4119,.F.);
#4139=CARTESIAN_POINT('',(12.319,2.032,-31.4598975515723));
#4140=DIRECTION('',(0.,0.,1.));
#4141=DIRECTION('',(1.,0.,0.));
#4142=AXIS2_PLACEMENT_3D('',#4139,#4140,#4141);
#4143=PLANE('',#4142);
#4144=ORIENTED_EDGE('',*,*,#992,.F.);
#4145=ORIENTED_EDGE('',*,*,#4134,.F.);
#4146=DIRECTION('',(1.,0.,0.));
#4147=VECTOR('',#4146,1.);
#4148=CARTESIAN_POINT('',(12.319,2.032,-31.4598975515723));
#4149=LINE('',#4148,#4147);
#4150=EDGE_CURVE('E1350',#4127,#4071,#4149,.T.);
#4151=ORIENTED_EDGE('',*,*,#4150,.T.);
#4152=ORIENTED_EDGE('',*,*,#4072,.T.);
#4153=EDGE_LOOP('',(#4144,#4145,#4151,#4152));
#4154=FACE_BOUND('',#4153,.T.);
#4155=ADVANCED_FACE('F1366',(#4154),#4143,.T.);
#4156=CARTESIAN_POINT('',(14.351,2.032,-31.4598975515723));
#4157=DIRECTION('',(0.,-1.,0.));
#4158=DIRECTION('',(0.,0.,-1.));
#4159=AXIS2_PLACEMENT_3D('',#4156,#4157,#4158);
#4160=PLANE('',#4159);
#4161=ORIENTED_EDGE('',*,*,#4080,.T.);
#4162=ORIENTED_EDGE('',*,*,#4150,.F.);
#4163=ORIENTED_EDGE('',*,*,#4128,.T.);
#4164=ORIENTED_EDGE('',*,*,#4104,.F.);
#4165=EDGE_LOOP('',(#4161,#4162,#4163,#4164));
#4166=FACE_BOUND('',#4165,.T.);
#4167=ADVANCED_FACE('F1379',(#4166),#4160,.F.);
#4168=CARTESIAN_POINT('',(18.415,2.032,-3.59210244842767));
#4169=DIRECTION('',(1.,0.,0.));
#4170=DIRECTION('',(0.,0.,-1.));
#4171=AXIS2_PLACEMENT_3D('',#4168,#4169,#4170);
#4172=PLANE('',#4171);
#4173=ORIENTED_EDGE('',*,*,#79,.T.);
#4174=DIRECTION('',(0.,1.,0.));
#4175=VECTOR('',#4174,1.);
#4176=CARTESIAN_POINT('',(18.415,2.032,-31.4598975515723));
#4177=LINE('',#4176,#4175);
#4178=CARTESIAN_POINT('',(18.415,2.032,-31.4598975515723));
#4179=VERTEX_POINT('',#4178);
#4180=EDGE_CURVE('E1333',#4179,#70,#4177,.T.);
#4181=ORIENTED_EDGE('',*,*,#4180,.F.);
#4182=DIRECTION('',(0.,0.,-1.));
#4183=VECTOR('',#4182,1.);
#4184=CARTESIAN_POINT('',(18.415,2.032,-3.59210244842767));
#4185=LINE('',#4184,#4183);
#4186=CARTESIAN_POINT('',(18.415,2.032,-3.59210244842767));
#4187=VERTEX_POINT('',#4186);
#4188=EDGE_CURVE('E1319',#4187,#4179,#4185,.T.);
#4189=ORIENTED_EDGE('',*,*,#4188,.F.);
#4190=DIRECTION('',(0.,1.,0.));
#4191=VECTOR('',#4190,1.);
#4192=CARTESIAN_POINT('',(18.415,2.032,-3.59210244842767));
#4193=LINE('',#4192,#4191);
#4194=EDGE_CURVE('E1334',#4187,#78,#4193,.T.);
#4195=ORIENTED_EDGE('',*,*,#4194,.T.);
#4196=EDGE_LOOP('',(#4173,#4181,#4189,#4195));
#4197=FACE_BOUND('',#4196,.T.);
#4198=ADVANCED_FACE('F1381',(#4197),#4172,.F.);
#4199=CARTESIAN_POINT('',(18.415,2.032,-3.59210244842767));
#4200=DIRECTION('',(0.,0.,-1.));
#4201=DIRECTION('',(-1.,0.,0.));
#4202=AXIS2_PLACEMENT_3D('',#4199,#4200,#4201);
#4203=PLANE('',#4202);
#4204=ORIENTED_EDGE('',*,*,#844,.F.);
#4205=ORIENTED_EDGE('',*,*,#4194,.F.);
#4206=DIRECTION('',(-1.,0.,0.));
#4207=VECTOR('',#4206,1.);
#4208=CARTESIAN_POINT('',(18.415,2.032,-3.59210244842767));
#4209=LINE('',#4208,#4207);
#4210=CARTESIAN_POINT('',(16.383,2.032,-3.59210244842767));
#4211=VERTEX_POINT('',#4210);
#4212=EDGE_CURVE('E1331',#4187,#4211,#4209,.T.);
#4213=ORIENTED_EDGE('',*,*,#4212,.T.);
#4214=DIRECTION('',(0.,1.,0.));
#4215=VECTOR('',#4214,1.);
#4216=CARTESIAN_POINT('',(16.383,2.032,-3.59210244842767));
#4217=LINE('',#4216,#4215);
#4218=EDGE_CURVE('E1336',#4211,#93,#4217,.T.);
#4219=ORIENTED_EDGE('',*,*,#4218,.T.);
#4220=EDGE_LOOP('',(#4204,#4205,#4213,#4219));
#4221=FACE_BOUND('',#4220,.T.);
#4222=ADVANCED_FACE('F1387',(#4221),#4203,.T.);
#4223=CARTESIAN_POINT('',(16.383,2.032,-31.4598975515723));
#4224=DIRECTION('',(-1.,0.,0.));
#4225=DIRECTION('',(0.,0.,1.));
#4226=AXIS2_PLACEMENT_3D('',#4223,#4224,#4225);
#4227=PLANE('',#4226);
#4228=ORIENTED_EDGE('',*,*,#94,.T.);
#4229=ORIENTED_EDGE('',*,*,#4218,.F.);
#4230=DIRECTION('',(0.,0.,1.));
#4231=VECTOR('',#4230,1.);
#4232=CARTESIAN_POINT('',(16.383,2.032,-31.4598975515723));
#4233=LINE('',#4232,#4231);
#4234=CARTESIAN_POINT('',(16.383,2.032,-31.4598975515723));
#4235=VERTEX_POINT('',#4234);
#4236=EDGE_CURVE('E1328',#4235,#4211,#4233,.T.);
#4237=ORIENTED_EDGE('',*,*,#4236,.F.);
#4238=DIRECTION('',(0.,1.,0.));
#4239=VECTOR('',#4238,1.);
#4240=CARTESIAN_POINT('',(16.383,2.032,-31.4598975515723));
#4241=LINE('',#4240,#4239);
#4242=EDGE_CURVE('E1338',#4235,#91,#4241,.T.);
#4243=ORIENTED_EDGE('',*,*,#4242,.T.);
#4244=EDGE_LOOP('',(#4228,#4229,#4237,#4243));
#4245=FACE_BOUND('',#4244,.T.);
#4246=ADVANCED_FACE('F2878',(#4245),#4227,.F.);
#4247=CARTESIAN_POINT('',(16.383,2.032,-31.4598975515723));
#4248=DIRECTION('',(0.,0.,1.));
#4249=DIRECTION('',(1.,0.,0.));
#4250=AXIS2_PLACEMENT_3D('',#4247,#4248,#4249);
#4251=PLANE('',#4250);
#4252=ORIENTED_EDGE('',*,*,#999,.F.);
#4253=ORIENTED_EDGE('',*,*,#4242,.F.);
#4254=DIRECTION('',(1.,0.,0.));
#4255=VECTOR('',#4254,1.);
#4256=CARTESIAN_POINT('',(16.383,2.032,-31.4598975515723));
#4257=LINE('',#4256,#4255);
#4258=EDGE_CURVE('E1322',#4235,#4179,#4257,.T.);
#4259=ORIENTED_EDGE('',*,*,#4258,.T.);
#4260=ORIENTED_EDGE('',*,*,#4180,.T.);
#4261=EDGE_LOOP('',(#4252,#4253,#4259,#4260));
#4262=FACE_BOUND('',#4261,.T.);
#4263=ADVANCED_FACE('F2885',(#4262),#4251,.T.);
#4264=CARTESIAN_POINT('',(18.415,2.032,-31.4598975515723));
#4265=DIRECTION('',(0.,-1.,0.));
#4266=DIRECTION('',(0.,0.,-1.));
#4267=AXIS2_PLACEMENT_3D('',#4264,#4265,#4266);
#4268=PLANE('',#4267);
#4269=ORIENTED_EDGE('',*,*,#4188,.T.);
#4270=ORIENTED_EDGE('',*,*,#4258,.F.);
#4271=ORIENTED_EDGE('',*,*,#4236,.T.);
#4272=ORIENTED_EDGE('',*,*,#4212,.F.);
#4273=EDGE_LOOP('',(#4269,#4270,#4271,#4272));
#4274=FACE_BOUND('',#4273,.T.);
#4275=ADVANCED_FACE('F2893',(#4274),#4268,.F.);
#4276=CARTESIAN_POINT('',(22.479,2.032,-3.59210244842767));
#4277=DIRECTION('',(1.,0.,0.));
#4278=DIRECTION('',(0.,0.,-1.));
#4279=AXIS2_PLACEMENT_3D('',#4276,#4277,#4278);
#4280=PLANE('',#4279);
#4281=ORIENTED_EDGE('',*,*,#32,.T.);
#4282=DIRECTION('',(0.,1.,0.));
#4283=VECTOR('',#4282,1.);
#4284=CARTESIAN_POINT('',(22.479,2.032,-31.4598975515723));
#4285=LINE('',#4284,#4283);
#4286=CARTESIAN_POINT('',(22.479,2.032,-31.4598975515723));
#4287=VERTEX_POINT('',#4286);
#4288=EDGE_CURVE('E670',#4287,#31,#4285,.T.);
#4289=ORIENTED_EDGE('',*,*,#4288,.F.);
#4290=DIRECTION('',(0.,0.,-1.));
#4291=VECTOR('',#4290,1.);
#4292=CARTESIAN_POINT('',(22.479,2.032,-3.59210244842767));
#4293=LINE('',#4292,#4291);
#4294=CARTESIAN_POINT('',(22.479,2.032,-3.59210244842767));
#4295=VERTEX_POINT('',#4294);
#4296=EDGE_CURVE('E2941',#4295,#4287,#4293,.T.);
#4297=ORIENTED_EDGE('',*,*,#4296,.F.);
#4298=DIRECTION('',(0.,1.,0.));
#4299=VECTOR('',#4298,1.);
#4300=CARTESIAN_POINT('',(22.479,2.032,-3.59210244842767));
#4301=LINE('',#4300,#4299);
#4302=EDGE_CURVE('E2950',#4295,#29,#4301,.T.);
#4303=ORIENTED_EDGE('',*,*,#4302,.T.);
#4304=EDGE_LOOP('',(#4281,#4289,#4297,#4303));
#4305=FACE_BOUND('',#4304,.T.);
#4306=ADVANCED_FACE('F2901',(#4305),#4280,.F.);
#4307=CARTESIAN_POINT('',(22.479,2.032,-3.59210244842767));
#4308=DIRECTION('',(0.,0.,-1.));
#4309=DIRECTION('',(-1.,0.,0.));
#4310=AXIS2_PLACEMENT_3D('',#4307,#4308,#4309);
#4311=PLANE('',#4310);
#4312=ORIENTED_EDGE('',*,*,#837,.F.);
#4313=ORIENTED_EDGE('',*,*,#4302,.F.);
#4314=DIRECTION('',(-1.,0.,0.));
#4315=VECTOR('',#4314,1.);
#4316=CARTESIAN_POINT('',(22.479,2.032,-3.59210244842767));
#4317=LINE('',#4316,#4315);
#4318=CARTESIAN_POINT('',(20.447,2.032,-3.59210244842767));
#4319=VERTEX_POINT('',#4318);
#4320=EDGE_CURVE('E2943',#4295,#4319,#4317,.T.);
#4321=ORIENTED_EDGE('',*,*,#4320,.T.);
#4322=DIRECTION('',(0.,1.,0.));
#4323=VECTOR('',#4322,1.);
#4324=CARTESIAN_POINT('',(20.447,2.032,-3.59210244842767));
#4325=LINE('',#4324,#4323);
#4326=EDGE_CURVE('E669',#4319,#66,#4325,.T.);
#4327=ORIENTED_EDGE('',*,*,#4326,.T.);
#4328=EDGE_LOOP('',(#4312,#4313,#4321,#4327));
#4329=FACE_BOUND('',#4328,.T.);
#4330=ADVANCED_FACE('F2909',(#4329),#4311,.T.);
#4331=CARTESIAN_POINT('',(20.447,2.032,-31.4598975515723));
#4332=DIRECTION('',(-1.,0.,0.));
#4333=DIRECTION('',(0.,0.,1.));
#4334=AXIS2_PLACEMENT_3D('',#4331,#4332,#4333);
#4335=PLANE('',#4334);
#4336=ORIENTED_EDGE('',*,*,#67,.T.);
#4337=ORIENTED_EDGE('',*,*,#4326,.F.);
#4338=DIRECTION('',(0.,0.,1.));
#4339=VECTOR('',#4338,1.);
#4340=CARTESIAN_POINT('',(20.447,2.032,-31.4598975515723));
#4341=LINE('',#4340,#4339);
#4342=CARTESIAN_POINT('',(20.447,2.032,-31.4598975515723));
#4343=VERTEX_POINT('',#4342);
#4344=EDGE_CURVE('E666',#4343,#4319,#4341,.T.);
#4345=ORIENTED_EDGE('',*,*,#4344,.F.);
#4346=DIRECTION('',(0.,1.,0.));
#4347=VECTOR('',#4346,1.);
#4348=CARTESIAN_POINT('',(20.447,2.032,-31.4598975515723));
#4349=LINE('',#4348,#4347);
#4350=EDGE_CURVE('E659',#4343,#64,#4349,.T.);
#4351=ORIENTED_EDGE('',*,*,#4350,.T.);
#4352=EDGE_LOOP('',(#4336,#4337,#4345,#4351));
#4353=FACE_BOUND('',#4352,.T.);
#4354=ADVANCED_FACE('F661',(#4353),#4335,.F.);
#4355=CARTESIAN_POINT('',(20.447,2.032,-31.4598975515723));
#4356=DIRECTION('',(0.,0.,1.));
#4357=DIRECTION('',(1.,0.,0.));
#4358=AXIS2_PLACEMENT_3D('',#4355,#4356,#4357);
#4359=PLANE('',#4358);
#4360=ORIENTED_EDGE('',*,*,#1006,.F.);
#4361=ORIENTED_EDGE('',*,*,#4350,.F.);
#4362=DIRECTION('',(1.,0.,0.));
#4363=VECTOR('',#4362,1.);
#4364=CARTESIAN_POINT('',(20.447,2.032,-31.4598975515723));
#4365=LINE('',#4364,#4363);
#4366=EDGE_CURVE('E2942',#4343,#4287,#4365,.T.);
#4367=ORIENTED_EDGE('',*,*,#4366,.T.);
#4368=ORIENTED_EDGE('',*,*,#4288,.T.);
#4369=EDGE_LOOP('',(#4360,#4361,#4367,#4368));
#4370=FACE_BOUND('',#4369,.T.);
#4371=ADVANCED_FACE('F674',(#4370),#4359,.T.);
#4372=CARTESIAN_POINT('',(22.479,2.032,-31.4598975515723));
#4373=DIRECTION('',(0.,-1.,0.));
#4374=DIRECTION('',(0.,0.,-1.));
#4375=AXIS2_PLACEMENT_3D('',#4372,#4373,#4374);
#4376=PLANE('',#4375);
#4377=ORIENTED_EDGE('',*,*,#4296,.T.);
#4378=ORIENTED_EDGE('',*,*,#4366,.F.);
#4379=ORIENTED_EDGE('',*,*,#4344,.T.);
#4380=ORIENTED_EDGE('',*,*,#4320,.F.);
#4381=EDGE_LOOP('',(#4377,#4378,#4379,#4380));
#4382=FACE_BOUND('',#4381,.T.);
#4383=ADVANCED_FACE('F2929',(#4382),#4376,.F.);
#4384=CLOSED_SHELL('',(#58,#85,#112,#139,#166,#193,#220,#247,#274,#319,#550,#587,#602,#622,#724,
#769,#863,#881,#899,#917,#935,#953,#971,#1053,#1103,#1143,#1176,#1207,#1257,#1348,#1381,#1405,
#1438,#1462,#1474,#1484,#1508,#1532,#1582,#1622,#1655,#1686,#1736,#1827,#1929,#1962,#1986,#2019,
#2043,#2063,#2083,#2112,#2127,#2137,#2161,#2185,#2217,#2241,#2266,#2283,#2295,#2323,#2351,#2379,
#2391,#2415,#2433,#2451,#2469,#2487,#2505,#2523,#2541,#2559,#2577,#2595,#2613,#2631,#2649,#2667,
#2685,#2703,#2715,#2739,#2757,#2775,#2793,#2811,#2829,#2847,#2865,#2883,#2901,#2919,#2937,#2955,
#2973,#2991,#3009,#3027,#3039,#3063,#3081,#3099,#3117,#3135,#3147,#3171,#3189,#3207,#3225,#3243,
#3255,#3267,#3279,#3291,#3303,#3334,#3358,#3382,#3399,#3411,#3442,#3466,#3490,#3507,#3519,#3550,
#3574,#3598,#3615,#3627,#3658,#3682,#3706,#3723,#3735,#3766,#3790,#3814,#3831,#3843,#3874,#3898,
#3922,#3939,#3951,#3982,#4006,#4030,#4047,#4059,#4090,#4114,#4138,#4155,#4167,#4198,#4222,#4246,
#4263,#4275,#4306,#4330,#4354,#4371,#4383));
#4385=MANIFOLD_SOLID_BREP('B2',#4384);
#4386=ADVANCED_BREP_SHAPE_REPRESENTATION('',(#18,#4385),#14);
#4387=SHAPE_DEFINITION_REPRESENTATION(#9,#4386);
ENDSEC;
END-ISO-10303-21;
